VERSION 5.8 ;
BUSBITCHARS "[]" ;
DIVIDERCHAR "/" ;
UNITS
    DATABASE MICRONS 1000 ;
END UNITS

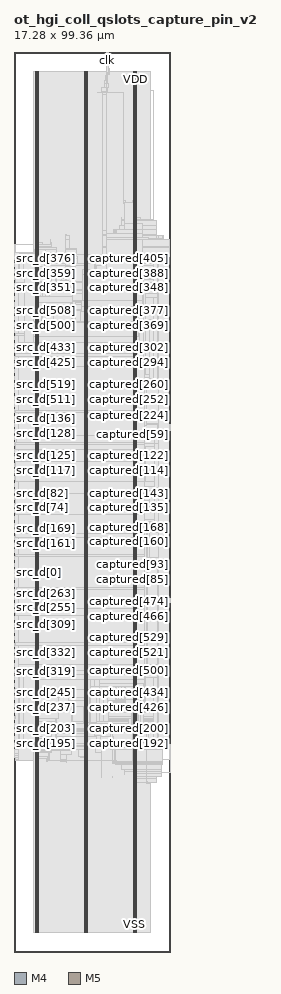
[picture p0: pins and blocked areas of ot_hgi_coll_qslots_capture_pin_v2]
MACRO ot_hgi_coll_qslots_capture_pin_v2
  FOREIGN ot_hgi_coll_qslots_capture_pin_v2 0 0 ;
  CLASS BLOCK ;
  SIZE 17.28 BY 99.36 ;
  PIN capture_slot[0]
    DIRECTION INPUT ;
    USE SIGNAL ;
    PORT
      LAYER M4 ;
        RECT  0 41.808 0.084 41.832 ;
    END
  END capture_slot[0]
  PIN captured[0]
    DIRECTION OUTPUT ;
    USE SIGNAL ;
    PORT
      LAYER M4 ;
        RECT  17.196 42.192 17.28 42.216 ;
    END
  END captured[0]
  PIN captured[100]
    DIRECTION OUTPUT ;
    USE SIGNAL ;
    PORT
      LAYER M4 ;
        RECT  17.196 51.792 17.28 51.816 ;
    END
  END captured[100]
  PIN captured[101]
    DIRECTION OUTPUT ;
    USE SIGNAL ;
    PORT
      LAYER M4 ;
        RECT  17.196 51.888 17.28 51.912 ;
    END
  END captured[101]
  PIN captured[102]
    DIRECTION OUTPUT ;
    USE SIGNAL ;
    PORT
      LAYER M4 ;
        RECT  17.196 51.984 17.28 52.008 ;
    END
  END captured[102]
  PIN captured[103]
    DIRECTION OUTPUT ;
    USE SIGNAL ;
    PORT
      LAYER M4 ;
        RECT  17.196 52.08 17.28 52.104 ;
    END
  END captured[103]
  PIN captured[104]
    DIRECTION OUTPUT ;
    USE SIGNAL ;
    PORT
      LAYER M4 ;
        RECT  17.196 52.176 17.28 52.2 ;
    END
  END captured[104]
  PIN captured[105]
    DIRECTION OUTPUT ;
    USE SIGNAL ;
    PORT
      LAYER M4 ;
        RECT  17.196 52.272 17.28 52.296 ;
    END
  END captured[105]
  PIN captured[106]
    DIRECTION OUTPUT ;
    USE SIGNAL ;
    PORT
      LAYER M4 ;
        RECT  17.196 52.368 17.28 52.392 ;
    END
  END captured[106]
  PIN captured[107]
    DIRECTION OUTPUT ;
    USE SIGNAL ;
    PORT
      LAYER M4 ;
        RECT  17.196 52.464 17.28 52.488 ;
    END
  END captured[107]
  PIN captured[108]
    DIRECTION OUTPUT ;
    USE SIGNAL ;
    PORT
      LAYER M4 ;
        RECT  17.196 52.56 17.28 52.584 ;
    END
  END captured[108]
  PIN captured[109]
    DIRECTION OUTPUT ;
    USE SIGNAL ;
    PORT
      LAYER M4 ;
        RECT  17.196 52.656 17.28 52.68 ;
    END
  END captured[109]
  PIN captured[10]
    DIRECTION OUTPUT ;
    USE SIGNAL ;
    PORT
      LAYER M4 ;
        RECT  17.196 43.152 17.28 43.176 ;
    END
  END captured[10]
  PIN captured[110]
    DIRECTION OUTPUT ;
    USE SIGNAL ;
    PORT
      LAYER M4 ;
        RECT  17.196 52.752 17.28 52.776 ;
    END
  END captured[110]
  PIN captured[111]
    DIRECTION OUTPUT ;
    USE SIGNAL ;
    PORT
      LAYER M4 ;
        RECT  17.196 52.848 17.28 52.872 ;
    END
  END captured[111]
  PIN captured[112]
    DIRECTION OUTPUT ;
    USE SIGNAL ;
    PORT
      LAYER M4 ;
        RECT  17.196 52.944 17.28 52.968 ;
    END
  END captured[112]
  PIN captured[113]
    DIRECTION OUTPUT ;
    USE SIGNAL ;
    PORT
      LAYER M4 ;
        RECT  17.196 53.04 17.28 53.064 ;
    END
  END captured[113]
  PIN captured[114]
    DIRECTION OUTPUT ;
    USE SIGNAL ;
    PORT
      LAYER M4 ;
        RECT  17.196 53.136 17.28 53.16 ;
    END
  END captured[114]
  PIN captured[115]
    DIRECTION OUTPUT ;
    USE SIGNAL ;
    PORT
      LAYER M4 ;
        RECT  17.196 53.232 17.28 53.256 ;
    END
  END captured[115]
  PIN captured[116]
    DIRECTION OUTPUT ;
    USE SIGNAL ;
    PORT
      LAYER M4 ;
        RECT  17.196 53.328 17.28 53.352 ;
    END
  END captured[116]
  PIN captured[117]
    DIRECTION OUTPUT ;
    USE SIGNAL ;
    PORT
      LAYER M4 ;
        RECT  17.196 53.424 17.28 53.448 ;
    END
  END captured[117]
  PIN captured[118]
    DIRECTION OUTPUT ;
    USE SIGNAL ;
    PORT
      LAYER M4 ;
        RECT  17.196 53.52 17.28 53.544 ;
    END
  END captured[118]
  PIN captured[119]
    DIRECTION OUTPUT ;
    USE SIGNAL ;
    PORT
      LAYER M4 ;
        RECT  17.196 53.616 17.28 53.64 ;
    END
  END captured[119]
  PIN captured[11]
    DIRECTION OUTPUT ;
    USE SIGNAL ;
    PORT
      LAYER M4 ;
        RECT  17.196 43.248 17.28 43.272 ;
    END
  END captured[11]
  PIN captured[120]
    DIRECTION OUTPUT ;
    USE SIGNAL ;
    PORT
      LAYER M4 ;
        RECT  17.196 53.712 17.28 53.736 ;
    END
  END captured[120]
  PIN captured[121]
    DIRECTION OUTPUT ;
    USE SIGNAL ;
    PORT
      LAYER M4 ;
        RECT  17.196 53.808 17.28 53.832 ;
    END
  END captured[121]
  PIN captured[122]
    DIRECTION OUTPUT ;
    USE SIGNAL ;
    PORT
      LAYER M4 ;
        RECT  17.196 53.904 17.28 53.928 ;
    END
  END captured[122]
  PIN captured[123]
    DIRECTION OUTPUT ;
    USE SIGNAL ;
    PORT
      LAYER M4 ;
        RECT  17.196 54 17.28 54.024 ;
    END
  END captured[123]
  PIN captured[124]
    DIRECTION OUTPUT ;
    USE SIGNAL ;
    PORT
      LAYER M4 ;
        RECT  17.196 54.096 17.28 54.12 ;
    END
  END captured[124]
  PIN captured[125]
    DIRECTION OUTPUT ;
    USE SIGNAL ;
    PORT
      LAYER M4 ;
        RECT  17.196 54.192 17.28 54.216 ;
    END
  END captured[125]
  PIN captured[126]
    DIRECTION OUTPUT ;
    USE SIGNAL ;
    PORT
      LAYER M4 ;
        RECT  17.196 54.288 17.28 54.312 ;
    END
  END captured[126]
  PIN captured[127]
    DIRECTION OUTPUT ;
    USE SIGNAL ;
    PORT
      LAYER M4 ;
        RECT  17.196 54.384 17.28 54.408 ;
    END
  END captured[127]
  PIN captured[128]
    DIRECTION OUTPUT ;
    USE SIGNAL ;
    PORT
      LAYER M4 ;
        RECT  17.196 48.336 17.28 48.36 ;
    END
  END captured[128]
  PIN captured[129]
    DIRECTION OUTPUT ;
    USE SIGNAL ;
    PORT
      LAYER M4 ;
        RECT  17.196 48.432 17.28 48.456 ;
    END
  END captured[129]
  PIN captured[12]
    DIRECTION OUTPUT ;
    USE SIGNAL ;
    PORT
      LAYER M4 ;
        RECT  17.196 43.344 17.28 43.368 ;
    END
  END captured[12]
  PIN captured[130]
    DIRECTION OUTPUT ;
    USE SIGNAL ;
    PORT
      LAYER M4 ;
        RECT  17.196 48.528 17.28 48.552 ;
    END
  END captured[130]
  PIN captured[131]
    DIRECTION OUTPUT ;
    USE SIGNAL ;
    PORT
      LAYER M4 ;
        RECT  17.196 48.624 17.28 48.648 ;
    END
  END captured[131]
  PIN captured[132]
    DIRECTION OUTPUT ;
    USE SIGNAL ;
    PORT
      LAYER M4 ;
        RECT  17.196 48.72 17.28 48.744 ;
    END
  END captured[132]
  PIN captured[133]
    DIRECTION OUTPUT ;
    USE SIGNAL ;
    PORT
      LAYER M4 ;
        RECT  17.196 48.816 17.28 48.84 ;
    END
  END captured[133]
  PIN captured[134]
    DIRECTION OUTPUT ;
    USE SIGNAL ;
    PORT
      LAYER M4 ;
        RECT  17.196 48.912 17.28 48.936 ;
    END
  END captured[134]
  PIN captured[135]
    DIRECTION OUTPUT ;
    USE SIGNAL ;
    PORT
      LAYER M4 ;
        RECT  17.196 49.008 17.28 49.032 ;
    END
  END captured[135]
  PIN captured[136]
    DIRECTION OUTPUT ;
    USE SIGNAL ;
    PORT
      LAYER M4 ;
        RECT  17.196 49.104 17.28 49.128 ;
    END
  END captured[136]
  PIN captured[137]
    DIRECTION OUTPUT ;
    USE SIGNAL ;
    PORT
      LAYER M4 ;
        RECT  17.196 49.2 17.28 49.224 ;
    END
  END captured[137]
  PIN captured[138]
    DIRECTION OUTPUT ;
    USE SIGNAL ;
    PORT
      LAYER M4 ;
        RECT  17.196 49.296 17.28 49.32 ;
    END
  END captured[138]
  PIN captured[139]
    DIRECTION OUTPUT ;
    USE SIGNAL ;
    PORT
      LAYER M4 ;
        RECT  17.196 49.392 17.28 49.416 ;
    END
  END captured[139]
  PIN captured[13]
    DIRECTION OUTPUT ;
    USE SIGNAL ;
    PORT
      LAYER M4 ;
        RECT  17.196 43.44 17.28 43.464 ;
    END
  END captured[13]
  PIN captured[140]
    DIRECTION OUTPUT ;
    USE SIGNAL ;
    PORT
      LAYER M4 ;
        RECT  17.196 49.488 17.28 49.512 ;
    END
  END captured[140]
  PIN captured[141]
    DIRECTION OUTPUT ;
    USE SIGNAL ;
    PORT
      LAYER M4 ;
        RECT  17.196 49.584 17.28 49.608 ;
    END
  END captured[141]
  PIN captured[142]
    DIRECTION OUTPUT ;
    USE SIGNAL ;
    PORT
      LAYER M4 ;
        RECT  17.196 49.68 17.28 49.704 ;
    END
  END captured[142]
  PIN captured[143]
    DIRECTION OUTPUT ;
    USE SIGNAL ;
    PORT
      LAYER M4 ;
        RECT  17.196 49.776 17.28 49.8 ;
    END
  END captured[143]
  PIN captured[144]
    DIRECTION OUTPUT ;
    USE SIGNAL ;
    PORT
      LAYER M4 ;
        RECT  17.196 49.872 17.28 49.896 ;
    END
  END captured[144]
  PIN captured[145]
    DIRECTION OUTPUT ;
    USE SIGNAL ;
    PORT
      LAYER M4 ;
        RECT  17.196 49.968 17.28 49.992 ;
    END
  END captured[145]
  PIN captured[146]
    DIRECTION OUTPUT ;
    USE SIGNAL ;
    PORT
      LAYER M4 ;
        RECT  17.196 50.064 17.28 50.088 ;
    END
  END captured[146]
  PIN captured[147]
    DIRECTION OUTPUT ;
    USE SIGNAL ;
    PORT
      LAYER M4 ;
        RECT  17.196 50.16 17.28 50.184 ;
    END
  END captured[147]
  PIN captured[148]
    DIRECTION OUTPUT ;
    USE SIGNAL ;
    PORT
      LAYER M4 ;
        RECT  17.196 50.256 17.28 50.28 ;
    END
  END captured[148]
  PIN captured[149]
    DIRECTION OUTPUT ;
    USE SIGNAL ;
    PORT
      LAYER M4 ;
        RECT  17.196 50.352 17.28 50.376 ;
    END
  END captured[149]
  PIN captured[14]
    DIRECTION OUTPUT ;
    USE SIGNAL ;
    PORT
      LAYER M4 ;
        RECT  17.196 43.536 17.28 43.56 ;
    END
  END captured[14]
  PIN captured[150]
    DIRECTION OUTPUT ;
    USE SIGNAL ;
    PORT
      LAYER M4 ;
        RECT  17.196 50.448 17.28 50.472 ;
    END
  END captured[150]
  PIN captured[151]
    DIRECTION OUTPUT ;
    USE SIGNAL ;
    PORT
      LAYER M4 ;
        RECT  17.196 50.544 17.28 50.568 ;
    END
  END captured[151]
  PIN captured[152]
    DIRECTION OUTPUT ;
    USE SIGNAL ;
    PORT
      LAYER M4 ;
        RECT  17.196 50.64 17.28 50.664 ;
    END
  END captured[152]
  PIN captured[153]
    DIRECTION OUTPUT ;
    USE SIGNAL ;
    PORT
      LAYER M4 ;
        RECT  17.196 50.736 17.28 50.76 ;
    END
  END captured[153]
  PIN captured[154]
    DIRECTION OUTPUT ;
    USE SIGNAL ;
    PORT
      LAYER M4 ;
        RECT  17.196 50.832 17.28 50.856 ;
    END
  END captured[154]
  PIN captured[155]
    DIRECTION OUTPUT ;
    USE SIGNAL ;
    PORT
      LAYER M4 ;
        RECT  17.196 50.928 17.28 50.952 ;
    END
  END captured[155]
  PIN captured[156]
    DIRECTION OUTPUT ;
    USE SIGNAL ;
    PORT
      LAYER M4 ;
        RECT  17.196 51.024 17.28 51.048 ;
    END
  END captured[156]
  PIN captured[157]
    DIRECTION OUTPUT ;
    USE SIGNAL ;
    PORT
      LAYER M4 ;
        RECT  17.196 51.12 17.28 51.144 ;
    END
  END captured[157]
  PIN captured[158]
    DIRECTION OUTPUT ;
    USE SIGNAL ;
    PORT
      LAYER M4 ;
        RECT  17.196 51.216 17.28 51.24 ;
    END
  END captured[158]
  PIN captured[159]
    DIRECTION OUTPUT ;
    USE SIGNAL ;
    PORT
      LAYER M4 ;
        RECT  17.196 51.312 17.28 51.336 ;
    END
  END captured[159]
  PIN captured[15]
    DIRECTION OUTPUT ;
    USE SIGNAL ;
    PORT
      LAYER M4 ;
        RECT  17.196 43.632 17.28 43.656 ;
    END
  END captured[15]
  PIN captured[160]
    DIRECTION OUTPUT ;
    USE SIGNAL ;
    PORT
      LAYER M4 ;
        RECT  17.196 45.264 17.28 45.288 ;
    END
  END captured[160]
  PIN captured[161]
    DIRECTION OUTPUT ;
    USE SIGNAL ;
    PORT
      LAYER M4 ;
        RECT  17.196 45.36 17.28 45.384 ;
    END
  END captured[161]
  PIN captured[162]
    DIRECTION OUTPUT ;
    USE SIGNAL ;
    PORT
      LAYER M4 ;
        RECT  17.196 45.456 17.28 45.48 ;
    END
  END captured[162]
  PIN captured[163]
    DIRECTION OUTPUT ;
    USE SIGNAL ;
    PORT
      LAYER M4 ;
        RECT  17.196 45.552 17.28 45.576 ;
    END
  END captured[163]
  PIN captured[164]
    DIRECTION OUTPUT ;
    USE SIGNAL ;
    PORT
      LAYER M4 ;
        RECT  17.196 45.648 17.28 45.672 ;
    END
  END captured[164]
  PIN captured[165]
    DIRECTION OUTPUT ;
    USE SIGNAL ;
    PORT
      LAYER M4 ;
        RECT  17.196 45.744 17.28 45.768 ;
    END
  END captured[165]
  PIN captured[166]
    DIRECTION OUTPUT ;
    USE SIGNAL ;
    PORT
      LAYER M4 ;
        RECT  17.196 45.84 17.28 45.864 ;
    END
  END captured[166]
  PIN captured[167]
    DIRECTION OUTPUT ;
    USE SIGNAL ;
    PORT
      LAYER M4 ;
        RECT  17.196 45.936 17.28 45.96 ;
    END
  END captured[167]
  PIN captured[168]
    DIRECTION OUTPUT ;
    USE SIGNAL ;
    PORT
      LAYER M4 ;
        RECT  17.196 46.032 17.28 46.056 ;
    END
  END captured[168]
  PIN captured[169]
    DIRECTION OUTPUT ;
    USE SIGNAL ;
    PORT
      LAYER M4 ;
        RECT  17.196 46.128 17.28 46.152 ;
    END
  END captured[169]
  PIN captured[16]
    DIRECTION OUTPUT ;
    USE SIGNAL ;
    PORT
      LAYER M4 ;
        RECT  17.196 43.728 17.28 43.752 ;
    END
  END captured[16]
  PIN captured[170]
    DIRECTION OUTPUT ;
    USE SIGNAL ;
    PORT
      LAYER M4 ;
        RECT  17.196 46.224 17.28 46.248 ;
    END
  END captured[170]
  PIN captured[171]
    DIRECTION OUTPUT ;
    USE SIGNAL ;
    PORT
      LAYER M4 ;
        RECT  17.196 46.32 17.28 46.344 ;
    END
  END captured[171]
  PIN captured[172]
    DIRECTION OUTPUT ;
    USE SIGNAL ;
    PORT
      LAYER M4 ;
        RECT  17.196 46.416 17.28 46.44 ;
    END
  END captured[172]
  PIN captured[173]
    DIRECTION OUTPUT ;
    USE SIGNAL ;
    PORT
      LAYER M4 ;
        RECT  17.196 46.512 17.28 46.536 ;
    END
  END captured[173]
  PIN captured[174]
    DIRECTION OUTPUT ;
    USE SIGNAL ;
    PORT
      LAYER M4 ;
        RECT  17.196 46.608 17.28 46.632 ;
    END
  END captured[174]
  PIN captured[175]
    DIRECTION OUTPUT ;
    USE SIGNAL ;
    PORT
      LAYER M4 ;
        RECT  17.196 46.704 17.28 46.728 ;
    END
  END captured[175]
  PIN captured[176]
    DIRECTION OUTPUT ;
    USE SIGNAL ;
    PORT
      LAYER M4 ;
        RECT  17.196 46.8 17.28 46.824 ;
    END
  END captured[176]
  PIN captured[177]
    DIRECTION OUTPUT ;
    USE SIGNAL ;
    PORT
      LAYER M4 ;
        RECT  17.196 46.896 17.28 46.92 ;
    END
  END captured[177]
  PIN captured[178]
    DIRECTION OUTPUT ;
    USE SIGNAL ;
    PORT
      LAYER M4 ;
        RECT  17.196 46.992 17.28 47.016 ;
    END
  END captured[178]
  PIN captured[179]
    DIRECTION OUTPUT ;
    USE SIGNAL ;
    PORT
      LAYER M4 ;
        RECT  17.196 47.088 17.28 47.112 ;
    END
  END captured[179]
  PIN captured[17]
    DIRECTION OUTPUT ;
    USE SIGNAL ;
    PORT
      LAYER M4 ;
        RECT  17.196 43.824 17.28 43.848 ;
    END
  END captured[17]
  PIN captured[180]
    DIRECTION OUTPUT ;
    USE SIGNAL ;
    PORT
      LAYER M4 ;
        RECT  17.196 47.184 17.28 47.208 ;
    END
  END captured[180]
  PIN captured[181]
    DIRECTION OUTPUT ;
    USE SIGNAL ;
    PORT
      LAYER M4 ;
        RECT  17.196 47.28 17.28 47.304 ;
    END
  END captured[181]
  PIN captured[182]
    DIRECTION OUTPUT ;
    USE SIGNAL ;
    PORT
      LAYER M4 ;
        RECT  17.196 47.376 17.28 47.4 ;
    END
  END captured[182]
  PIN captured[183]
    DIRECTION OUTPUT ;
    USE SIGNAL ;
    PORT
      LAYER M4 ;
        RECT  17.196 47.472 17.28 47.496 ;
    END
  END captured[183]
  PIN captured[184]
    DIRECTION OUTPUT ;
    USE SIGNAL ;
    PORT
      LAYER M4 ;
        RECT  17.196 47.568 17.28 47.592 ;
    END
  END captured[184]
  PIN captured[185]
    DIRECTION OUTPUT ;
    USE SIGNAL ;
    PORT
      LAYER M4 ;
        RECT  17.196 47.664 17.28 47.688 ;
    END
  END captured[185]
  PIN captured[186]
    DIRECTION OUTPUT ;
    USE SIGNAL ;
    PORT
      LAYER M4 ;
        RECT  17.196 47.76 17.28 47.784 ;
    END
  END captured[186]
  PIN captured[187]
    DIRECTION OUTPUT ;
    USE SIGNAL ;
    PORT
      LAYER M4 ;
        RECT  17.196 47.856 17.28 47.88 ;
    END
  END captured[187]
  PIN captured[188]
    DIRECTION OUTPUT ;
    USE SIGNAL ;
    PORT
      LAYER M4 ;
        RECT  17.196 47.952 17.28 47.976 ;
    END
  END captured[188]
  PIN captured[189]
    DIRECTION OUTPUT ;
    USE SIGNAL ;
    PORT
      LAYER M4 ;
        RECT  17.196 48.048 17.28 48.072 ;
    END
  END captured[189]
  PIN captured[18]
    DIRECTION OUTPUT ;
    USE SIGNAL ;
    PORT
      LAYER M4 ;
        RECT  17.196 43.92 17.28 43.944 ;
    END
  END captured[18]
  PIN captured[190]
    DIRECTION OUTPUT ;
    USE SIGNAL ;
    PORT
      LAYER M4 ;
        RECT  17.196 48.144 17.28 48.168 ;
    END
  END captured[190]
  PIN captured[191]
    DIRECTION OUTPUT ;
    USE SIGNAL ;
    PORT
      LAYER M4 ;
        RECT  17.196 48.24 17.28 48.264 ;
    END
  END captured[191]
  PIN captured[192]
    DIRECTION OUTPUT ;
    USE SIGNAL ;
    PORT
      LAYER M4 ;
        RECT  17.196 22.992 17.28 23.016 ;
    END
  END captured[192]
  PIN captured[193]
    DIRECTION OUTPUT ;
    USE SIGNAL ;
    PORT
      LAYER M4 ;
        RECT  17.196 23.088 17.28 23.112 ;
    END
  END captured[193]
  PIN captured[194]
    DIRECTION OUTPUT ;
    USE SIGNAL ;
    PORT
      LAYER M4 ;
        RECT  17.196 23.184 17.28 23.208 ;
    END
  END captured[194]
  PIN captured[195]
    DIRECTION OUTPUT ;
    USE SIGNAL ;
    PORT
      LAYER M4 ;
        RECT  17.196 23.28 17.28 23.304 ;
    END
  END captured[195]
  PIN captured[196]
    DIRECTION OUTPUT ;
    USE SIGNAL ;
    PORT
      LAYER M4 ;
        RECT  17.196 23.376 17.28 23.4 ;
    END
  END captured[196]
  PIN captured[197]
    DIRECTION OUTPUT ;
    USE SIGNAL ;
    PORT
      LAYER M4 ;
        RECT  17.196 23.472 17.28 23.496 ;
    END
  END captured[197]
  PIN captured[198]
    DIRECTION OUTPUT ;
    USE SIGNAL ;
    PORT
      LAYER M4 ;
        RECT  17.196 23.568 17.28 23.592 ;
    END
  END captured[198]
  PIN captured[199]
    DIRECTION OUTPUT ;
    USE SIGNAL ;
    PORT
      LAYER M4 ;
        RECT  17.196 23.664 17.28 23.688 ;
    END
  END captured[199]
  PIN captured[19]
    DIRECTION OUTPUT ;
    USE SIGNAL ;
    PORT
      LAYER M4 ;
        RECT  17.196 44.016 17.28 44.04 ;
    END
  END captured[19]
  PIN captured[1]
    DIRECTION OUTPUT ;
    USE SIGNAL ;
    PORT
      LAYER M4 ;
        RECT  17.196 42.288 17.28 42.312 ;
    END
  END captured[1]
  PIN captured[200]
    DIRECTION OUTPUT ;
    USE SIGNAL ;
    PORT
      LAYER M4 ;
        RECT  17.196 23.76 17.28 23.784 ;
    END
  END captured[200]
  PIN captured[201]
    DIRECTION OUTPUT ;
    USE SIGNAL ;
    PORT
      LAYER M4 ;
        RECT  17.196 23.856 17.28 23.88 ;
    END
  END captured[201]
  PIN captured[202]
    DIRECTION OUTPUT ;
    USE SIGNAL ;
    PORT
      LAYER M4 ;
        RECT  17.196 23.952 17.28 23.976 ;
    END
  END captured[202]
  PIN captured[203]
    DIRECTION OUTPUT ;
    USE SIGNAL ;
    PORT
      LAYER M4 ;
        RECT  17.196 24.048 17.28 24.072 ;
    END
  END captured[203]
  PIN captured[204]
    DIRECTION OUTPUT ;
    USE SIGNAL ;
    PORT
      LAYER M4 ;
        RECT  17.196 24.144 17.28 24.168 ;
    END
  END captured[204]
  PIN captured[205]
    DIRECTION OUTPUT ;
    USE SIGNAL ;
    PORT
      LAYER M4 ;
        RECT  17.196 24.24 17.28 24.264 ;
    END
  END captured[205]
  PIN captured[206]
    DIRECTION OUTPUT ;
    USE SIGNAL ;
    PORT
      LAYER M4 ;
        RECT  17.196 24.336 17.28 24.36 ;
    END
  END captured[206]
  PIN captured[207]
    DIRECTION OUTPUT ;
    USE SIGNAL ;
    PORT
      LAYER M4 ;
        RECT  17.196 24.432 17.28 24.456 ;
    END
  END captured[207]
  PIN captured[208]
    DIRECTION OUTPUT ;
    USE SIGNAL ;
    PORT
      LAYER M4 ;
        RECT  17.196 24.528 17.28 24.552 ;
    END
  END captured[208]
  PIN captured[209]
    DIRECTION OUTPUT ;
    USE SIGNAL ;
    PORT
      LAYER M4 ;
        RECT  17.196 24.624 17.28 24.648 ;
    END
  END captured[209]
  PIN captured[20]
    DIRECTION OUTPUT ;
    USE SIGNAL ;
    PORT
      LAYER M4 ;
        RECT  17.196 44.112 17.28 44.136 ;
    END
  END captured[20]
  PIN captured[210]
    DIRECTION OUTPUT ;
    USE SIGNAL ;
    PORT
      LAYER M4 ;
        RECT  17.196 24.72 17.28 24.744 ;
    END
  END captured[210]
  PIN captured[211]
    DIRECTION OUTPUT ;
    USE SIGNAL ;
    PORT
      LAYER M4 ;
        RECT  17.196 24.816 17.28 24.84 ;
    END
  END captured[211]
  PIN captured[212]
    DIRECTION OUTPUT ;
    USE SIGNAL ;
    PORT
      LAYER M4 ;
        RECT  17.196 24.912 17.28 24.936 ;
    END
  END captured[212]
  PIN captured[213]
    DIRECTION OUTPUT ;
    USE SIGNAL ;
    PORT
      LAYER M4 ;
        RECT  17.196 25.008 17.28 25.032 ;
    END
  END captured[213]
  PIN captured[214]
    DIRECTION OUTPUT ;
    USE SIGNAL ;
    PORT
      LAYER M4 ;
        RECT  17.196 25.104 17.28 25.128 ;
    END
  END captured[214]
  PIN captured[215]
    DIRECTION OUTPUT ;
    USE SIGNAL ;
    PORT
      LAYER M4 ;
        RECT  17.196 25.2 17.28 25.224 ;
    END
  END captured[215]
  PIN captured[216]
    DIRECTION OUTPUT ;
    USE SIGNAL ;
    PORT
      LAYER M4 ;
        RECT  17.196 25.296 17.28 25.32 ;
    END
  END captured[216]
  PIN captured[217]
    DIRECTION OUTPUT ;
    USE SIGNAL ;
    PORT
      LAYER M4 ;
        RECT  17.196 25.392 17.28 25.416 ;
    END
  END captured[217]
  PIN captured[218]
    DIRECTION OUTPUT ;
    USE SIGNAL ;
    PORT
      LAYER M4 ;
        RECT  17.196 25.488 17.28 25.512 ;
    END
  END captured[218]
  PIN captured[219]
    DIRECTION OUTPUT ;
    USE SIGNAL ;
    PORT
      LAYER M4 ;
        RECT  17.196 25.584 17.28 25.608 ;
    END
  END captured[219]
  PIN captured[21]
    DIRECTION OUTPUT ;
    USE SIGNAL ;
    PORT
      LAYER M4 ;
        RECT  17.196 44.208 17.28 44.232 ;
    END
  END captured[21]
  PIN captured[220]
    DIRECTION OUTPUT ;
    USE SIGNAL ;
    PORT
      LAYER M4 ;
        RECT  17.196 25.68 17.28 25.704 ;
    END
  END captured[220]
  PIN captured[221]
    DIRECTION OUTPUT ;
    USE SIGNAL ;
    PORT
      LAYER M4 ;
        RECT  17.196 25.776 17.28 25.8 ;
    END
  END captured[221]
  PIN captured[222]
    DIRECTION OUTPUT ;
    USE SIGNAL ;
    PORT
      LAYER M4 ;
        RECT  17.196 25.872 17.28 25.896 ;
    END
  END captured[222]
  PIN captured[223]
    DIRECTION OUTPUT ;
    USE SIGNAL ;
    PORT
      LAYER M4 ;
        RECT  17.196 25.968 17.28 25.992 ;
    END
  END captured[223]
  PIN captured[224]
    DIRECTION OUTPUT ;
    USE SIGNAL ;
    PORT
      LAYER M4 ;
        RECT  17.196 58.32 17.28 58.344 ;
    END
  END captured[224]
  PIN captured[225]
    DIRECTION OUTPUT ;
    USE SIGNAL ;
    PORT
      LAYER M4 ;
        RECT  17.196 58.416 17.28 58.44 ;
    END
  END captured[225]
  PIN captured[226]
    DIRECTION OUTPUT ;
    USE SIGNAL ;
    PORT
      LAYER M4 ;
        RECT  17.196 58.512 17.28 58.536 ;
    END
  END captured[226]
  PIN captured[227]
    DIRECTION OUTPUT ;
    USE SIGNAL ;
    PORT
      LAYER M4 ;
        RECT  17.196 58.608 17.28 58.632 ;
    END
  END captured[227]
  PIN captured[228]
    DIRECTION OUTPUT ;
    USE SIGNAL ;
    PORT
      LAYER M4 ;
        RECT  17.196 58.704 17.28 58.728 ;
    END
  END captured[228]
  PIN captured[229]
    DIRECTION OUTPUT ;
    USE SIGNAL ;
    PORT
      LAYER M4 ;
        RECT  17.196 58.8 17.28 58.824 ;
    END
  END captured[229]
  PIN captured[22]
    DIRECTION OUTPUT ;
    USE SIGNAL ;
    PORT
      LAYER M4 ;
        RECT  17.196 44.304 17.28 44.328 ;
    END
  END captured[22]
  PIN captured[230]
    DIRECTION OUTPUT ;
    USE SIGNAL ;
    PORT
      LAYER M4 ;
        RECT  17.196 58.896 17.28 58.92 ;
    END
  END captured[230]
  PIN captured[231]
    DIRECTION OUTPUT ;
    USE SIGNAL ;
    PORT
      LAYER M4 ;
        RECT  17.196 58.992 17.28 59.016 ;
    END
  END captured[231]
  PIN captured[232]
    DIRECTION OUTPUT ;
    USE SIGNAL ;
    PORT
      LAYER M4 ;
        RECT  17.196 59.088 17.28 59.112 ;
    END
  END captured[232]
  PIN captured[233]
    DIRECTION OUTPUT ;
    USE SIGNAL ;
    PORT
      LAYER M4 ;
        RECT  17.196 59.184 17.28 59.208 ;
    END
  END captured[233]
  PIN captured[234]
    DIRECTION OUTPUT ;
    USE SIGNAL ;
    PORT
      LAYER M4 ;
        RECT  17.196 59.28 17.28 59.304 ;
    END
  END captured[234]
  PIN captured[235]
    DIRECTION OUTPUT ;
    USE SIGNAL ;
    PORT
      LAYER M4 ;
        RECT  17.196 59.376 17.28 59.4 ;
    END
  END captured[235]
  PIN captured[236]
    DIRECTION OUTPUT ;
    USE SIGNAL ;
    PORT
      LAYER M4 ;
        RECT  17.196 59.472 17.28 59.496 ;
    END
  END captured[236]
  PIN captured[237]
    DIRECTION OUTPUT ;
    USE SIGNAL ;
    PORT
      LAYER M4 ;
        RECT  17.196 59.568 17.28 59.592 ;
    END
  END captured[237]
  PIN captured[238]
    DIRECTION OUTPUT ;
    USE SIGNAL ;
    PORT
      LAYER M4 ;
        RECT  17.196 59.664 17.28 59.688 ;
    END
  END captured[238]
  PIN captured[239]
    DIRECTION OUTPUT ;
    USE SIGNAL ;
    PORT
      LAYER M4 ;
        RECT  17.196 59.76 17.28 59.784 ;
    END
  END captured[239]
  PIN captured[23]
    DIRECTION OUTPUT ;
    USE SIGNAL ;
    PORT
      LAYER M4 ;
        RECT  17.196 44.4 17.28 44.424 ;
    END
  END captured[23]
  PIN captured[240]
    DIRECTION OUTPUT ;
    USE SIGNAL ;
    PORT
      LAYER M4 ;
        RECT  17.196 59.856 17.28 59.88 ;
    END
  END captured[240]
  PIN captured[241]
    DIRECTION OUTPUT ;
    USE SIGNAL ;
    PORT
      LAYER M4 ;
        RECT  17.196 59.952 17.28 59.976 ;
    END
  END captured[241]
  PIN captured[242]
    DIRECTION OUTPUT ;
    USE SIGNAL ;
    PORT
      LAYER M4 ;
        RECT  17.196 60.048 17.28 60.072 ;
    END
  END captured[242]
  PIN captured[243]
    DIRECTION OUTPUT ;
    USE SIGNAL ;
    PORT
      LAYER M4 ;
        RECT  17.196 60.144 17.28 60.168 ;
    END
  END captured[243]
  PIN captured[244]
    DIRECTION OUTPUT ;
    USE SIGNAL ;
    PORT
      LAYER M4 ;
        RECT  17.196 60.24 17.28 60.264 ;
    END
  END captured[244]
  PIN captured[245]
    DIRECTION OUTPUT ;
    USE SIGNAL ;
    PORT
      LAYER M4 ;
        RECT  17.196 60.336 17.28 60.36 ;
    END
  END captured[245]
  PIN captured[246]
    DIRECTION OUTPUT ;
    USE SIGNAL ;
    PORT
      LAYER M4 ;
        RECT  17.196 60.432 17.28 60.456 ;
    END
  END captured[246]
  PIN captured[247]
    DIRECTION OUTPUT ;
    USE SIGNAL ;
    PORT
      LAYER M4 ;
        RECT  17.196 60.528 17.28 60.552 ;
    END
  END captured[247]
  PIN captured[248]
    DIRECTION OUTPUT ;
    USE SIGNAL ;
    PORT
      LAYER M4 ;
        RECT  17.196 60.624 17.28 60.648 ;
    END
  END captured[248]
  PIN captured[249]
    DIRECTION OUTPUT ;
    USE SIGNAL ;
    PORT
      LAYER M4 ;
        RECT  17.196 60.72 17.28 60.744 ;
    END
  END captured[249]
  PIN captured[24]
    DIRECTION OUTPUT ;
    USE SIGNAL ;
    PORT
      LAYER M4 ;
        RECT  17.196 44.496 17.28 44.52 ;
    END
  END captured[24]
  PIN captured[250]
    DIRECTION OUTPUT ;
    USE SIGNAL ;
    PORT
      LAYER M4 ;
        RECT  17.196 60.816 17.28 60.84 ;
    END
  END captured[250]
  PIN captured[251]
    DIRECTION OUTPUT ;
    USE SIGNAL ;
    PORT
      LAYER M4 ;
        RECT  17.196 60.912 17.28 60.936 ;
    END
  END captured[251]
  PIN captured[252]
    DIRECTION OUTPUT ;
    USE SIGNAL ;
    PORT
      LAYER M4 ;
        RECT  17.196 61.008 17.28 61.032 ;
    END
  END captured[252]
  PIN captured[253]
    DIRECTION OUTPUT ;
    USE SIGNAL ;
    PORT
      LAYER M4 ;
        RECT  17.196 61.104 17.28 61.128 ;
    END
  END captured[253]
  PIN captured[254]
    DIRECTION OUTPUT ;
    USE SIGNAL ;
    PORT
      LAYER M4 ;
        RECT  17.196 61.2 17.28 61.224 ;
    END
  END captured[254]
  PIN captured[255]
    DIRECTION OUTPUT ;
    USE SIGNAL ;
    PORT
      LAYER M4 ;
        RECT  17.196 61.296 17.28 61.32 ;
    END
  END captured[255]
  PIN captured[256]
    DIRECTION OUTPUT ;
    USE SIGNAL ;
    PORT
      LAYER M4 ;
        RECT  17.196 61.392 17.28 61.416 ;
    END
  END captured[256]
  PIN captured[257]
    DIRECTION OUTPUT ;
    USE SIGNAL ;
    PORT
      LAYER M4 ;
        RECT  17.196 61.488 17.28 61.512 ;
    END
  END captured[257]
  PIN captured[258]
    DIRECTION OUTPUT ;
    USE SIGNAL ;
    PORT
      LAYER M4 ;
        RECT  17.196 61.584 17.28 61.608 ;
    END
  END captured[258]
  PIN captured[259]
    DIRECTION OUTPUT ;
    USE SIGNAL ;
    PORT
      LAYER M4 ;
        RECT  17.196 61.68 17.28 61.704 ;
    END
  END captured[259]
  PIN captured[25]
    DIRECTION OUTPUT ;
    USE SIGNAL ;
    PORT
      LAYER M4 ;
        RECT  17.196 44.592 17.28 44.616 ;
    END
  END captured[25]
  PIN captured[260]
    DIRECTION OUTPUT ;
    USE SIGNAL ;
    PORT
      LAYER M4 ;
        RECT  17.196 61.776 17.28 61.8 ;
    END
  END captured[260]
  PIN captured[261]
    DIRECTION OUTPUT ;
    USE SIGNAL ;
    PORT
      LAYER M4 ;
        RECT  17.196 61.872 17.28 61.896 ;
    END
  END captured[261]
  PIN captured[262]
    DIRECTION OUTPUT ;
    USE SIGNAL ;
    PORT
      LAYER M4 ;
        RECT  17.196 61.968 17.28 61.992 ;
    END
  END captured[262]
  PIN captured[263]
    DIRECTION OUTPUT ;
    USE SIGNAL ;
    PORT
      LAYER M4 ;
        RECT  17.196 62.064 17.28 62.088 ;
    END
  END captured[263]
  PIN captured[264]
    DIRECTION OUTPUT ;
    USE SIGNAL ;
    PORT
      LAYER M4 ;
        RECT  17.196 62.16 17.28 62.184 ;
    END
  END captured[264]
  PIN captured[265]
    DIRECTION OUTPUT ;
    USE SIGNAL ;
    PORT
      LAYER M4 ;
        RECT  17.196 62.256 17.28 62.28 ;
    END
  END captured[265]
  PIN captured[266]
    DIRECTION OUTPUT ;
    USE SIGNAL ;
    PORT
      LAYER M4 ;
        RECT  17.196 62.352 17.28 62.376 ;
    END
  END captured[266]
  PIN captured[267]
    DIRECTION OUTPUT ;
    USE SIGNAL ;
    PORT
      LAYER M4 ;
        RECT  17.196 62.448 17.28 62.472 ;
    END
  END captured[267]
  PIN captured[268]
    DIRECTION OUTPUT ;
    USE SIGNAL ;
    PORT
      LAYER M4 ;
        RECT  17.196 62.544 17.28 62.568 ;
    END
  END captured[268]
  PIN captured[269]
    DIRECTION OUTPUT ;
    USE SIGNAL ;
    PORT
      LAYER M4 ;
        RECT  17.196 62.64 17.28 62.664 ;
    END
  END captured[269]
  PIN captured[26]
    DIRECTION OUTPUT ;
    USE SIGNAL ;
    PORT
      LAYER M4 ;
        RECT  17.196 44.688 17.28 44.712 ;
    END
  END captured[26]
  PIN captured[270]
    DIRECTION OUTPUT ;
    USE SIGNAL ;
    PORT
      LAYER M4 ;
        RECT  17.196 62.736 17.28 62.76 ;
    END
  END captured[270]
  PIN captured[271]
    DIRECTION OUTPUT ;
    USE SIGNAL ;
    PORT
      LAYER M4 ;
        RECT  17.196 62.832 17.28 62.856 ;
    END
  END captured[271]
  PIN captured[272]
    DIRECTION OUTPUT ;
    USE SIGNAL ;
    PORT
      LAYER M4 ;
        RECT  17.196 62.928 17.28 62.952 ;
    END
  END captured[272]
  PIN captured[273]
    DIRECTION OUTPUT ;
    USE SIGNAL ;
    PORT
      LAYER M4 ;
        RECT  17.196 63.024 17.28 63.048 ;
    END
  END captured[273]
  PIN captured[274]
    DIRECTION OUTPUT ;
    USE SIGNAL ;
    PORT
      LAYER M4 ;
        RECT  17.196 63.12 17.28 63.144 ;
    END
  END captured[274]
  PIN captured[275]
    DIRECTION OUTPUT ;
    USE SIGNAL ;
    PORT
      LAYER M4 ;
        RECT  17.196 63.216 17.28 63.24 ;
    END
  END captured[275]
  PIN captured[276]
    DIRECTION OUTPUT ;
    USE SIGNAL ;
    PORT
      LAYER M4 ;
        RECT  17.196 63.312 17.28 63.336 ;
    END
  END captured[276]
  PIN captured[277]
    DIRECTION OUTPUT ;
    USE SIGNAL ;
    PORT
      LAYER M4 ;
        RECT  17.196 63.408 17.28 63.432 ;
    END
  END captured[277]
  PIN captured[278]
    DIRECTION OUTPUT ;
    USE SIGNAL ;
    PORT
      LAYER M4 ;
        RECT  17.196 63.504 17.28 63.528 ;
    END
  END captured[278]
  PIN captured[279]
    DIRECTION OUTPUT ;
    USE SIGNAL ;
    PORT
      LAYER M4 ;
        RECT  17.196 63.6 17.28 63.624 ;
    END
  END captured[279]
  PIN captured[27]
    DIRECTION OUTPUT ;
    USE SIGNAL ;
    PORT
      LAYER M4 ;
        RECT  17.196 44.784 17.28 44.808 ;
    END
  END captured[27]
  PIN captured[280]
    DIRECTION OUTPUT ;
    USE SIGNAL ;
    PORT
      LAYER M4 ;
        RECT  17.196 63.696 17.28 63.72 ;
    END
  END captured[280]
  PIN captured[281]
    DIRECTION OUTPUT ;
    USE SIGNAL ;
    PORT
      LAYER M4 ;
        RECT  17.196 63.792 17.28 63.816 ;
    END
  END captured[281]
  PIN captured[282]
    DIRECTION OUTPUT ;
    USE SIGNAL ;
    PORT
      LAYER M4 ;
        RECT  17.196 63.888 17.28 63.912 ;
    END
  END captured[282]
  PIN captured[283]
    DIRECTION OUTPUT ;
    USE SIGNAL ;
    PORT
      LAYER M4 ;
        RECT  17.196 63.984 17.28 64.008 ;
    END
  END captured[283]
  PIN captured[284]
    DIRECTION OUTPUT ;
    USE SIGNAL ;
    PORT
      LAYER M4 ;
        RECT  17.196 64.08 17.28 64.104 ;
    END
  END captured[284]
  PIN captured[285]
    DIRECTION OUTPUT ;
    USE SIGNAL ;
    PORT
      LAYER M4 ;
        RECT  17.196 64.176 17.28 64.2 ;
    END
  END captured[285]
  PIN captured[286]
    DIRECTION OUTPUT ;
    USE SIGNAL ;
    PORT
      LAYER M4 ;
        RECT  17.196 64.272 17.28 64.296 ;
    END
  END captured[286]
  PIN captured[287]
    DIRECTION OUTPUT ;
    USE SIGNAL ;
    PORT
      LAYER M4 ;
        RECT  17.196 64.368 17.28 64.392 ;
    END
  END captured[287]
  PIN captured[288]
    DIRECTION OUTPUT ;
    USE SIGNAL ;
    PORT
      LAYER M4 ;
        RECT  17.196 64.464 17.28 64.488 ;
    END
  END captured[288]
  PIN captured[289]
    DIRECTION OUTPUT ;
    USE SIGNAL ;
    PORT
      LAYER M4 ;
        RECT  17.196 64.56 17.28 64.584 ;
    END
  END captured[289]
  PIN captured[28]
    DIRECTION OUTPUT ;
    USE SIGNAL ;
    PORT
      LAYER M4 ;
        RECT  17.196 44.88 17.28 44.904 ;
    END
  END captured[28]
  PIN captured[290]
    DIRECTION OUTPUT ;
    USE SIGNAL ;
    PORT
      LAYER M4 ;
        RECT  17.196 64.656 17.28 64.68 ;
    END
  END captured[290]
  PIN captured[291]
    DIRECTION OUTPUT ;
    USE SIGNAL ;
    PORT
      LAYER M4 ;
        RECT  17.196 64.752 17.28 64.776 ;
    END
  END captured[291]
  PIN captured[292]
    DIRECTION OUTPUT ;
    USE SIGNAL ;
    PORT
      LAYER M4 ;
        RECT  17.196 64.848 17.28 64.872 ;
    END
  END captured[292]
  PIN captured[293]
    DIRECTION OUTPUT ;
    USE SIGNAL ;
    PORT
      LAYER M4 ;
        RECT  17.196 64.944 17.28 64.968 ;
    END
  END captured[293]
  PIN captured[294]
    DIRECTION OUTPUT ;
    USE SIGNAL ;
    PORT
      LAYER M4 ;
        RECT  17.196 65.04 17.28 65.064 ;
    END
  END captured[294]
  PIN captured[295]
    DIRECTION OUTPUT ;
    USE SIGNAL ;
    PORT
      LAYER M4 ;
        RECT  17.196 65.136 17.28 65.16 ;
    END
  END captured[295]
  PIN captured[296]
    DIRECTION OUTPUT ;
    USE SIGNAL ;
    PORT
      LAYER M4 ;
        RECT  17.196 65.232 17.28 65.256 ;
    END
  END captured[296]
  PIN captured[297]
    DIRECTION OUTPUT ;
    USE SIGNAL ;
    PORT
      LAYER M4 ;
        RECT  17.196 65.328 17.28 65.352 ;
    END
  END captured[297]
  PIN captured[298]
    DIRECTION OUTPUT ;
    USE SIGNAL ;
    PORT
      LAYER M4 ;
        RECT  17.196 65.424 17.28 65.448 ;
    END
  END captured[298]
  PIN captured[299]
    DIRECTION OUTPUT ;
    USE SIGNAL ;
    PORT
      LAYER M4 ;
        RECT  17.196 65.52 17.28 65.544 ;
    END
  END captured[299]
  PIN captured[29]
    DIRECTION OUTPUT ;
    USE SIGNAL ;
    PORT
      LAYER M4 ;
        RECT  17.196 44.976 17.28 45 ;
    END
  END captured[29]
  PIN captured[2]
    DIRECTION OUTPUT ;
    USE SIGNAL ;
    PORT
      LAYER M4 ;
        RECT  17.196 42.384 17.28 42.408 ;
    END
  END captured[2]
  PIN captured[300]
    DIRECTION OUTPUT ;
    USE SIGNAL ;
    PORT
      LAYER M4 ;
        RECT  17.196 65.616 17.28 65.64 ;
    END
  END captured[300]
  PIN captured[301]
    DIRECTION OUTPUT ;
    USE SIGNAL ;
    PORT
      LAYER M4 ;
        RECT  17.196 65.712 17.28 65.736 ;
    END
  END captured[301]
  PIN captured[302]
    DIRECTION OUTPUT ;
    USE SIGNAL ;
    PORT
      LAYER M4 ;
        RECT  17.196 65.808 17.28 65.832 ;
    END
  END captured[302]
  PIN captured[303]
    DIRECTION OUTPUT ;
    USE SIGNAL ;
    PORT
      LAYER M4 ;
        RECT  17.196 65.904 17.28 65.928 ;
    END
  END captured[303]
  PIN captured[304]
    DIRECTION OUTPUT ;
    USE SIGNAL ;
    PORT
      LAYER M4 ;
        RECT  17.196 66 17.28 66.024 ;
    END
  END captured[304]
  PIN captured[305]
    DIRECTION OUTPUT ;
    USE SIGNAL ;
    PORT
      LAYER M4 ;
        RECT  17.196 66.096 17.28 66.12 ;
    END
  END captured[305]
  PIN captured[306]
    DIRECTION OUTPUT ;
    USE SIGNAL ;
    PORT
      LAYER M4 ;
        RECT  17.196 66.192 17.28 66.216 ;
    END
  END captured[306]
  PIN captured[307]
    DIRECTION OUTPUT ;
    USE SIGNAL ;
    PORT
      LAYER M4 ;
        RECT  17.196 66.288 17.28 66.312 ;
    END
  END captured[307]
  PIN captured[308]
    DIRECTION OUTPUT ;
    USE SIGNAL ;
    PORT
      LAYER M4 ;
        RECT  17.196 66.384 17.28 66.408 ;
    END
  END captured[308]
  PIN captured[309]
    DIRECTION OUTPUT ;
    USE SIGNAL ;
    PORT
      LAYER M4 ;
        RECT  17.196 66.48 17.28 66.504 ;
    END
  END captured[309]
  PIN captured[30]
    DIRECTION OUTPUT ;
    USE SIGNAL ;
    PORT
      LAYER M4 ;
        RECT  17.196 45.072 17.28 45.096 ;
    END
  END captured[30]
  PIN captured[310]
    DIRECTION OUTPUT ;
    USE SIGNAL ;
    PORT
      LAYER M4 ;
        RECT  17.196 66.576 17.28 66.6 ;
    END
  END captured[310]
  PIN captured[311]
    DIRECTION OUTPUT ;
    USE SIGNAL ;
    PORT
      LAYER M4 ;
        RECT  17.196 66.672 17.28 66.696 ;
    END
  END captured[311]
  PIN captured[312]
    DIRECTION OUTPUT ;
    USE SIGNAL ;
    PORT
      LAYER M4 ;
        RECT  17.196 66.768 17.28 66.792 ;
    END
  END captured[312]
  PIN captured[313]
    DIRECTION OUTPUT ;
    USE SIGNAL ;
    PORT
      LAYER M4 ;
        RECT  17.196 66.864 17.28 66.888 ;
    END
  END captured[313]
  PIN captured[314]
    DIRECTION OUTPUT ;
    USE SIGNAL ;
    PORT
      LAYER M4 ;
        RECT  17.196 66.96 17.28 66.984 ;
    END
  END captured[314]
  PIN captured[315]
    DIRECTION OUTPUT ;
    USE SIGNAL ;
    PORT
      LAYER M4 ;
        RECT  17.196 67.056 17.28 67.08 ;
    END
  END captured[315]
  PIN captured[316]
    DIRECTION OUTPUT ;
    USE SIGNAL ;
    PORT
      LAYER M4 ;
        RECT  17.196 67.152 17.28 67.176 ;
    END
  END captured[316]
  PIN captured[317]
    DIRECTION OUTPUT ;
    USE SIGNAL ;
    PORT
      LAYER M4 ;
        RECT  17.196 67.248 17.28 67.272 ;
    END
  END captured[317]
  PIN captured[318]
    DIRECTION OUTPUT ;
    USE SIGNAL ;
    PORT
      LAYER M4 ;
        RECT  17.196 67.344 17.28 67.368 ;
    END
  END captured[318]
  PIN captured[319]
    DIRECTION OUTPUT ;
    USE SIGNAL ;
    PORT
      LAYER M4 ;
        RECT  17.196 67.44 17.28 67.464 ;
    END
  END captured[319]
  PIN captured[31]
    DIRECTION OUTPUT ;
    USE SIGNAL ;
    PORT
      LAYER M4 ;
        RECT  17.196 45.168 17.28 45.192 ;
    END
  END captured[31]
  PIN captured[320]
    DIRECTION OUTPUT ;
    USE SIGNAL ;
    PORT
      LAYER M4 ;
        RECT  17.196 70.608 17.28 70.632 ;
    END
  END captured[320]
  PIN captured[321]
    DIRECTION OUTPUT ;
    USE SIGNAL ;
    PORT
      LAYER M4 ;
        RECT  17.196 70.704 17.28 70.728 ;
    END
  END captured[321]
  PIN captured[322]
    DIRECTION OUTPUT ;
    USE SIGNAL ;
    PORT
      LAYER M4 ;
        RECT  17.196 70.8 17.28 70.824 ;
    END
  END captured[322]
  PIN captured[323]
    DIRECTION OUTPUT ;
    USE SIGNAL ;
    PORT
      LAYER M4 ;
        RECT  17.196 70.896 17.28 70.92 ;
    END
  END captured[323]
  PIN captured[324]
    DIRECTION OUTPUT ;
    USE SIGNAL ;
    PORT
      LAYER M4 ;
        RECT  17.196 70.992 17.28 71.016 ;
    END
  END captured[324]
  PIN captured[325]
    DIRECTION OUTPUT ;
    USE SIGNAL ;
    PORT
      LAYER M4 ;
        RECT  17.196 71.088 17.28 71.112 ;
    END
  END captured[325]
  PIN captured[326]
    DIRECTION OUTPUT ;
    USE SIGNAL ;
    PORT
      LAYER M4 ;
        RECT  17.196 71.184 17.28 71.208 ;
    END
  END captured[326]
  PIN captured[327]
    DIRECTION OUTPUT ;
    USE SIGNAL ;
    PORT
      LAYER M4 ;
        RECT  17.196 71.28 17.28 71.304 ;
    END
  END captured[327]
  PIN captured[328]
    DIRECTION OUTPUT ;
    USE SIGNAL ;
    PORT
      LAYER M4 ;
        RECT  17.196 71.376 17.28 71.4 ;
    END
  END captured[328]
  PIN captured[329]
    DIRECTION OUTPUT ;
    USE SIGNAL ;
    PORT
      LAYER M4 ;
        RECT  17.196 71.472 17.28 71.496 ;
    END
  END captured[329]
  PIN captured[32]
    DIRECTION OUTPUT ;
    USE SIGNAL ;
    PORT
      LAYER M4 ;
        RECT  17.196 54.48 17.28 54.504 ;
    END
  END captured[32]
  PIN captured[330]
    DIRECTION OUTPUT ;
    USE SIGNAL ;
    PORT
      LAYER M4 ;
        RECT  17.196 71.568 17.28 71.592 ;
    END
  END captured[330]
  PIN captured[331]
    DIRECTION OUTPUT ;
    USE SIGNAL ;
    PORT
      LAYER M4 ;
        RECT  17.196 71.664 17.28 71.688 ;
    END
  END captured[331]
  PIN captured[332]
    DIRECTION OUTPUT ;
    USE SIGNAL ;
    PORT
      LAYER M4 ;
        RECT  17.196 71.76 17.28 71.784 ;
    END
  END captured[332]
  PIN captured[333]
    DIRECTION OUTPUT ;
    USE SIGNAL ;
    PORT
      LAYER M4 ;
        RECT  17.196 71.856 17.28 71.88 ;
    END
  END captured[333]
  PIN captured[334]
    DIRECTION OUTPUT ;
    USE SIGNAL ;
    PORT
      LAYER M4 ;
        RECT  17.196 71.952 17.28 71.976 ;
    END
  END captured[334]
  PIN captured[335]
    DIRECTION OUTPUT ;
    USE SIGNAL ;
    PORT
      LAYER M4 ;
        RECT  17.196 72.048 17.28 72.072 ;
    END
  END captured[335]
  PIN captured[336]
    DIRECTION OUTPUT ;
    USE SIGNAL ;
    PORT
      LAYER M4 ;
        RECT  17.196 72.144 17.28 72.168 ;
    END
  END captured[336]
  PIN captured[337]
    DIRECTION OUTPUT ;
    USE SIGNAL ;
    PORT
      LAYER M4 ;
        RECT  17.196 72.24 17.28 72.264 ;
    END
  END captured[337]
  PIN captured[338]
    DIRECTION OUTPUT ;
    USE SIGNAL ;
    PORT
      LAYER M4 ;
        RECT  17.196 72.336 17.28 72.36 ;
    END
  END captured[338]
  PIN captured[339]
    DIRECTION OUTPUT ;
    USE SIGNAL ;
    PORT
      LAYER M4 ;
        RECT  17.196 72.432 17.28 72.456 ;
    END
  END captured[339]
  PIN captured[33]
    DIRECTION OUTPUT ;
    USE SIGNAL ;
    PORT
      LAYER M4 ;
        RECT  17.196 54.576 17.28 54.6 ;
    END
  END captured[33]
  PIN captured[340]
    DIRECTION OUTPUT ;
    USE SIGNAL ;
    PORT
      LAYER M4 ;
        RECT  17.196 72.528 17.28 72.552 ;
    END
  END captured[340]
  PIN captured[341]
    DIRECTION OUTPUT ;
    USE SIGNAL ;
    PORT
      LAYER M4 ;
        RECT  17.196 72.624 17.28 72.648 ;
    END
  END captured[341]
  PIN captured[342]
    DIRECTION OUTPUT ;
    USE SIGNAL ;
    PORT
      LAYER M4 ;
        RECT  17.196 72.72 17.28 72.744 ;
    END
  END captured[342]
  PIN captured[343]
    DIRECTION OUTPUT ;
    USE SIGNAL ;
    PORT
      LAYER M4 ;
        RECT  17.196 72.816 17.28 72.84 ;
    END
  END captured[343]
  PIN captured[344]
    DIRECTION OUTPUT ;
    USE SIGNAL ;
    PORT
      LAYER M4 ;
        RECT  17.196 72.912 17.28 72.936 ;
    END
  END captured[344]
  PIN captured[345]
    DIRECTION OUTPUT ;
    USE SIGNAL ;
    PORT
      LAYER M4 ;
        RECT  17.196 73.008 17.28 73.032 ;
    END
  END captured[345]
  PIN captured[346]
    DIRECTION OUTPUT ;
    USE SIGNAL ;
    PORT
      LAYER M4 ;
        RECT  17.196 73.104 17.28 73.128 ;
    END
  END captured[346]
  PIN captured[347]
    DIRECTION OUTPUT ;
    USE SIGNAL ;
    PORT
      LAYER M4 ;
        RECT  17.196 73.2 17.28 73.224 ;
    END
  END captured[347]
  PIN captured[348]
    DIRECTION OUTPUT ;
    USE SIGNAL ;
    PORT
      LAYER M4 ;
        RECT  17.196 73.296 17.28 73.32 ;
    END
  END captured[348]
  PIN captured[349]
    DIRECTION OUTPUT ;
    USE SIGNAL ;
    PORT
      LAYER M4 ;
        RECT  17.196 73.392 17.28 73.416 ;
    END
  END captured[349]
  PIN captured[34]
    DIRECTION OUTPUT ;
    USE SIGNAL ;
    PORT
      LAYER M4 ;
        RECT  17.196 54.672 17.28 54.696 ;
    END
  END captured[34]
  PIN captured[350]
    DIRECTION OUTPUT ;
    USE SIGNAL ;
    PORT
      LAYER M4 ;
        RECT  17.196 73.488 17.28 73.512 ;
    END
  END captured[350]
  PIN captured[351]
    DIRECTION OUTPUT ;
    USE SIGNAL ;
    PORT
      LAYER M4 ;
        RECT  17.196 73.584 17.28 73.608 ;
    END
  END captured[351]
  PIN captured[352]
    DIRECTION OUTPUT ;
    USE SIGNAL ;
    PORT
      LAYER M4 ;
        RECT  17.196 67.536 17.28 67.56 ;
    END
  END captured[352]
  PIN captured[353]
    DIRECTION OUTPUT ;
    USE SIGNAL ;
    PORT
      LAYER M4 ;
        RECT  17.196 67.632 17.28 67.656 ;
    END
  END captured[353]
  PIN captured[354]
    DIRECTION OUTPUT ;
    USE SIGNAL ;
    PORT
      LAYER M4 ;
        RECT  17.196 67.728 17.28 67.752 ;
    END
  END captured[354]
  PIN captured[355]
    DIRECTION OUTPUT ;
    USE SIGNAL ;
    PORT
      LAYER M4 ;
        RECT  17.196 67.824 17.28 67.848 ;
    END
  END captured[355]
  PIN captured[356]
    DIRECTION OUTPUT ;
    USE SIGNAL ;
    PORT
      LAYER M4 ;
        RECT  17.196 67.92 17.28 67.944 ;
    END
  END captured[356]
  PIN captured[357]
    DIRECTION OUTPUT ;
    USE SIGNAL ;
    PORT
      LAYER M4 ;
        RECT  17.196 68.016 17.28 68.04 ;
    END
  END captured[357]
  PIN captured[358]
    DIRECTION OUTPUT ;
    USE SIGNAL ;
    PORT
      LAYER M4 ;
        RECT  17.196 68.112 17.28 68.136 ;
    END
  END captured[358]
  PIN captured[359]
    DIRECTION OUTPUT ;
    USE SIGNAL ;
    PORT
      LAYER M4 ;
        RECT  17.196 68.208 17.28 68.232 ;
    END
  END captured[359]
  PIN captured[35]
    DIRECTION OUTPUT ;
    USE SIGNAL ;
    PORT
      LAYER M4 ;
        RECT  17.196 54.768 17.28 54.792 ;
    END
  END captured[35]
  PIN captured[360]
    DIRECTION OUTPUT ;
    USE SIGNAL ;
    PORT
      LAYER M4 ;
        RECT  17.196 68.304 17.28 68.328 ;
    END
  END captured[360]
  PIN captured[361]
    DIRECTION OUTPUT ;
    USE SIGNAL ;
    PORT
      LAYER M4 ;
        RECT  17.196 68.4 17.28 68.424 ;
    END
  END captured[361]
  PIN captured[362]
    DIRECTION OUTPUT ;
    USE SIGNAL ;
    PORT
      LAYER M4 ;
        RECT  17.196 68.496 17.28 68.52 ;
    END
  END captured[362]
  PIN captured[363]
    DIRECTION OUTPUT ;
    USE SIGNAL ;
    PORT
      LAYER M4 ;
        RECT  17.196 68.592 17.28 68.616 ;
    END
  END captured[363]
  PIN captured[364]
    DIRECTION OUTPUT ;
    USE SIGNAL ;
    PORT
      LAYER M4 ;
        RECT  17.196 68.688 17.28 68.712 ;
    END
  END captured[364]
  PIN captured[365]
    DIRECTION OUTPUT ;
    USE SIGNAL ;
    PORT
      LAYER M4 ;
        RECT  17.196 68.784 17.28 68.808 ;
    END
  END captured[365]
  PIN captured[366]
    DIRECTION OUTPUT ;
    USE SIGNAL ;
    PORT
      LAYER M4 ;
        RECT  17.196 68.88 17.28 68.904 ;
    END
  END captured[366]
  PIN captured[367]
    DIRECTION OUTPUT ;
    USE SIGNAL ;
    PORT
      LAYER M4 ;
        RECT  17.196 68.976 17.28 69 ;
    END
  END captured[367]
  PIN captured[368]
    DIRECTION OUTPUT ;
    USE SIGNAL ;
    PORT
      LAYER M4 ;
        RECT  17.196 69.072 17.28 69.096 ;
    END
  END captured[368]
  PIN captured[369]
    DIRECTION OUTPUT ;
    USE SIGNAL ;
    PORT
      LAYER M4 ;
        RECT  17.196 69.168 17.28 69.192 ;
    END
  END captured[369]
  PIN captured[36]
    DIRECTION OUTPUT ;
    USE SIGNAL ;
    PORT
      LAYER M4 ;
        RECT  17.196 54.864 17.28 54.888 ;
    END
  END captured[36]
  PIN captured[370]
    DIRECTION OUTPUT ;
    USE SIGNAL ;
    PORT
      LAYER M4 ;
        RECT  17.196 69.264 17.28 69.288 ;
    END
  END captured[370]
  PIN captured[371]
    DIRECTION OUTPUT ;
    USE SIGNAL ;
    PORT
      LAYER M4 ;
        RECT  17.196 69.36 17.28 69.384 ;
    END
  END captured[371]
  PIN captured[372]
    DIRECTION OUTPUT ;
    USE SIGNAL ;
    PORT
      LAYER M4 ;
        RECT  17.196 69.456 17.28 69.48 ;
    END
  END captured[372]
  PIN captured[373]
    DIRECTION OUTPUT ;
    USE SIGNAL ;
    PORT
      LAYER M4 ;
        RECT  17.196 69.552 17.28 69.576 ;
    END
  END captured[373]
  PIN captured[374]
    DIRECTION OUTPUT ;
    USE SIGNAL ;
    PORT
      LAYER M4 ;
        RECT  17.196 69.648 17.28 69.672 ;
    END
  END captured[374]
  PIN captured[375]
    DIRECTION OUTPUT ;
    USE SIGNAL ;
    PORT
      LAYER M4 ;
        RECT  17.196 69.744 17.28 69.768 ;
    END
  END captured[375]
  PIN captured[376]
    DIRECTION OUTPUT ;
    USE SIGNAL ;
    PORT
      LAYER M4 ;
        RECT  17.196 69.84 17.28 69.864 ;
    END
  END captured[376]
  PIN captured[377]
    DIRECTION OUTPUT ;
    USE SIGNAL ;
    PORT
      LAYER M4 ;
        RECT  17.196 69.936 17.28 69.96 ;
    END
  END captured[377]
  PIN captured[378]
    DIRECTION OUTPUT ;
    USE SIGNAL ;
    PORT
      LAYER M4 ;
        RECT  17.196 70.032 17.28 70.056 ;
    END
  END captured[378]
  PIN captured[379]
    DIRECTION OUTPUT ;
    USE SIGNAL ;
    PORT
      LAYER M4 ;
        RECT  17.196 70.128 17.28 70.152 ;
    END
  END captured[379]
  PIN captured[37]
    DIRECTION OUTPUT ;
    USE SIGNAL ;
    PORT
      LAYER M4 ;
        RECT  17.196 54.96 17.28 54.984 ;
    END
  END captured[37]
  PIN captured[380]
    DIRECTION OUTPUT ;
    USE SIGNAL ;
    PORT
      LAYER M4 ;
        RECT  17.196 70.224 17.28 70.248 ;
    END
  END captured[380]
  PIN captured[381]
    DIRECTION OUTPUT ;
    USE SIGNAL ;
    PORT
      LAYER M4 ;
        RECT  17.196 70.32 17.28 70.344 ;
    END
  END captured[381]
  PIN captured[382]
    DIRECTION OUTPUT ;
    USE SIGNAL ;
    PORT
      LAYER M4 ;
        RECT  17.196 70.416 17.28 70.44 ;
    END
  END captured[382]
  PIN captured[383]
    DIRECTION OUTPUT ;
    USE SIGNAL ;
    PORT
      LAYER M4 ;
        RECT  17.196 70.512 17.28 70.536 ;
    END
  END captured[383]
  PIN captured[384]
    DIRECTION OUTPUT ;
    USE SIGNAL ;
    PORT
      LAYER M4 ;
        RECT  17.196 73.68 17.28 73.704 ;
    END
  END captured[384]
  PIN captured[385]
    DIRECTION OUTPUT ;
    USE SIGNAL ;
    PORT
      LAYER M4 ;
        RECT  17.196 73.776 17.28 73.8 ;
    END
  END captured[385]
  PIN captured[386]
    DIRECTION OUTPUT ;
    USE SIGNAL ;
    PORT
      LAYER M4 ;
        RECT  17.196 73.872 17.28 73.896 ;
    END
  END captured[386]
  PIN captured[387]
    DIRECTION OUTPUT ;
    USE SIGNAL ;
    PORT
      LAYER M4 ;
        RECT  17.196 73.968 17.28 73.992 ;
    END
  END captured[387]
  PIN captured[388]
    DIRECTION OUTPUT ;
    USE SIGNAL ;
    PORT
      LAYER M4 ;
        RECT  17.196 74.064 17.28 74.088 ;
    END
  END captured[388]
  PIN captured[389]
    DIRECTION OUTPUT ;
    USE SIGNAL ;
    PORT
      LAYER M4 ;
        RECT  17.196 74.16 17.28 74.184 ;
    END
  END captured[389]
  PIN captured[38]
    DIRECTION OUTPUT ;
    USE SIGNAL ;
    PORT
      LAYER M4 ;
        RECT  17.196 55.056 17.28 55.08 ;
    END
  END captured[38]
  PIN captured[390]
    DIRECTION OUTPUT ;
    USE SIGNAL ;
    PORT
      LAYER M4 ;
        RECT  17.196 74.256 17.28 74.28 ;
    END
  END captured[390]
  PIN captured[391]
    DIRECTION OUTPUT ;
    USE SIGNAL ;
    PORT
      LAYER M4 ;
        RECT  17.196 74.352 17.28 74.376 ;
    END
  END captured[391]
  PIN captured[392]
    DIRECTION OUTPUT ;
    USE SIGNAL ;
    PORT
      LAYER M4 ;
        RECT  17.196 74.448 17.28 74.472 ;
    END
  END captured[392]
  PIN captured[393]
    DIRECTION OUTPUT ;
    USE SIGNAL ;
    PORT
      LAYER M4 ;
        RECT  17.196 74.544 17.28 74.568 ;
    END
  END captured[393]
  PIN captured[394]
    DIRECTION OUTPUT ;
    USE SIGNAL ;
    PORT
      LAYER M4 ;
        RECT  17.196 74.64 17.28 74.664 ;
    END
  END captured[394]
  PIN captured[395]
    DIRECTION OUTPUT ;
    USE SIGNAL ;
    PORT
      LAYER M4 ;
        RECT  17.196 74.736 17.28 74.76 ;
    END
  END captured[395]
  PIN captured[396]
    DIRECTION OUTPUT ;
    USE SIGNAL ;
    PORT
      LAYER M4 ;
        RECT  17.196 74.832 17.28 74.856 ;
    END
  END captured[396]
  PIN captured[397]
    DIRECTION OUTPUT ;
    USE SIGNAL ;
    PORT
      LAYER M4 ;
        RECT  17.196 74.928 17.28 74.952 ;
    END
  END captured[397]
  PIN captured[398]
    DIRECTION OUTPUT ;
    USE SIGNAL ;
    PORT
      LAYER M4 ;
        RECT  17.196 75.024 17.28 75.048 ;
    END
  END captured[398]
  PIN captured[399]
    DIRECTION OUTPUT ;
    USE SIGNAL ;
    PORT
      LAYER M4 ;
        RECT  17.196 75.12 17.28 75.144 ;
    END
  END captured[399]
  PIN captured[39]
    DIRECTION OUTPUT ;
    USE SIGNAL ;
    PORT
      LAYER M4 ;
        RECT  17.196 55.152 17.28 55.176 ;
    END
  END captured[39]
  PIN captured[3]
    DIRECTION OUTPUT ;
    USE SIGNAL ;
    PORT
      LAYER M4 ;
        RECT  17.196 42.48 17.28 42.504 ;
    END
  END captured[3]
  PIN captured[400]
    DIRECTION OUTPUT ;
    USE SIGNAL ;
    PORT
      LAYER M4 ;
        RECT  17.196 75.216 17.28 75.24 ;
    END
  END captured[400]
  PIN captured[401]
    DIRECTION OUTPUT ;
    USE SIGNAL ;
    PORT
      LAYER M4 ;
        RECT  17.196 75.312 17.28 75.336 ;
    END
  END captured[401]
  PIN captured[402]
    DIRECTION OUTPUT ;
    USE SIGNAL ;
    PORT
      LAYER M4 ;
        RECT  17.196 75.408 17.28 75.432 ;
    END
  END captured[402]
  PIN captured[403]
    DIRECTION OUTPUT ;
    USE SIGNAL ;
    PORT
      LAYER M4 ;
        RECT  17.196 75.504 17.28 75.528 ;
    END
  END captured[403]
  PIN captured[404]
    DIRECTION OUTPUT ;
    USE SIGNAL ;
    PORT
      LAYER M4 ;
        RECT  17.196 75.6 17.28 75.624 ;
    END
  END captured[404]
  PIN captured[405]
    DIRECTION OUTPUT ;
    USE SIGNAL ;
    PORT
      LAYER M4 ;
        RECT  17.196 75.696 17.28 75.72 ;
    END
  END captured[405]
  PIN captured[406]
    DIRECTION OUTPUT ;
    USE SIGNAL ;
    PORT
      LAYER M4 ;
        RECT  17.196 75.792 17.28 75.816 ;
    END
  END captured[406]
  PIN captured[407]
    DIRECTION OUTPUT ;
    USE SIGNAL ;
    PORT
      LAYER M4 ;
        RECT  17.196 75.888 17.28 75.912 ;
    END
  END captured[407]
  PIN captured[408]
    DIRECTION OUTPUT ;
    USE SIGNAL ;
    PORT
      LAYER M4 ;
        RECT  17.196 75.984 17.28 76.008 ;
    END
  END captured[408]
  PIN captured[409]
    DIRECTION OUTPUT ;
    USE SIGNAL ;
    PORT
      LAYER M4 ;
        RECT  17.196 76.08 17.28 76.104 ;
    END
  END captured[409]
  PIN captured[40]
    DIRECTION OUTPUT ;
    USE SIGNAL ;
    PORT
      LAYER M4 ;
        RECT  17.196 55.248 17.28 55.272 ;
    END
  END captured[40]
  PIN captured[410]
    DIRECTION OUTPUT ;
    USE SIGNAL ;
    PORT
      LAYER M4 ;
        RECT  17.196 76.176 17.28 76.2 ;
    END
  END captured[410]
  PIN captured[411]
    DIRECTION OUTPUT ;
    USE SIGNAL ;
    PORT
      LAYER M4 ;
        RECT  17.196 76.272 17.28 76.296 ;
    END
  END captured[411]
  PIN captured[412]
    DIRECTION OUTPUT ;
    USE SIGNAL ;
    PORT
      LAYER M4 ;
        RECT  17.196 76.368 17.28 76.392 ;
    END
  END captured[412]
  PIN captured[413]
    DIRECTION OUTPUT ;
    USE SIGNAL ;
    PORT
      LAYER M4 ;
        RECT  17.196 76.464 17.28 76.488 ;
    END
  END captured[413]
  PIN captured[414]
    DIRECTION OUTPUT ;
    USE SIGNAL ;
    PORT
      LAYER M4 ;
        RECT  17.196 76.56 17.28 76.584 ;
    END
  END captured[414]
  PIN captured[415]
    DIRECTION OUTPUT ;
    USE SIGNAL ;
    PORT
      LAYER M4 ;
        RECT  17.196 76.656 17.28 76.68 ;
    END
  END captured[415]
  PIN captured[416]
    DIRECTION OUTPUT ;
    USE SIGNAL ;
    PORT
      LAYER M4 ;
        RECT  17.196 26.064 17.28 26.088 ;
    END
  END captured[416]
  PIN captured[417]
    DIRECTION OUTPUT ;
    USE SIGNAL ;
    PORT
      LAYER M4 ;
        RECT  17.196 26.16 17.28 26.184 ;
    END
  END captured[417]
  PIN captured[418]
    DIRECTION OUTPUT ;
    USE SIGNAL ;
    PORT
      LAYER M4 ;
        RECT  17.196 26.256 17.28 26.28 ;
    END
  END captured[418]
  PIN captured[419]
    DIRECTION OUTPUT ;
    USE SIGNAL ;
    PORT
      LAYER M4 ;
        RECT  17.196 26.352 17.28 26.376 ;
    END
  END captured[419]
  PIN captured[41]
    DIRECTION OUTPUT ;
    USE SIGNAL ;
    PORT
      LAYER M4 ;
        RECT  17.196 55.344 17.28 55.368 ;
    END
  END captured[41]
  PIN captured[420]
    DIRECTION OUTPUT ;
    USE SIGNAL ;
    PORT
      LAYER M4 ;
        RECT  17.196 26.448 17.28 26.472 ;
    END
  END captured[420]
  PIN captured[421]
    DIRECTION OUTPUT ;
    USE SIGNAL ;
    PORT
      LAYER M4 ;
        RECT  17.196 26.544 17.28 26.568 ;
    END
  END captured[421]
  PIN captured[422]
    DIRECTION OUTPUT ;
    USE SIGNAL ;
    PORT
      LAYER M4 ;
        RECT  17.196 26.64 17.28 26.664 ;
    END
  END captured[422]
  PIN captured[423]
    DIRECTION OUTPUT ;
    USE SIGNAL ;
    PORT
      LAYER M4 ;
        RECT  17.196 26.736 17.28 26.76 ;
    END
  END captured[423]
  PIN captured[424]
    DIRECTION OUTPUT ;
    USE SIGNAL ;
    PORT
      LAYER M4 ;
        RECT  17.196 26.832 17.28 26.856 ;
    END
  END captured[424]
  PIN captured[425]
    DIRECTION OUTPUT ;
    USE SIGNAL ;
    PORT
      LAYER M4 ;
        RECT  17.196 26.928 17.28 26.952 ;
    END
  END captured[425]
  PIN captured[426]
    DIRECTION OUTPUT ;
    USE SIGNAL ;
    PORT
      LAYER M4 ;
        RECT  17.196 27.024 17.28 27.048 ;
    END
  END captured[426]
  PIN captured[427]
    DIRECTION OUTPUT ;
    USE SIGNAL ;
    PORT
      LAYER M4 ;
        RECT  17.196 27.12 17.28 27.144 ;
    END
  END captured[427]
  PIN captured[428]
    DIRECTION OUTPUT ;
    USE SIGNAL ;
    PORT
      LAYER M4 ;
        RECT  17.196 27.216 17.28 27.24 ;
    END
  END captured[428]
  PIN captured[429]
    DIRECTION OUTPUT ;
    USE SIGNAL ;
    PORT
      LAYER M4 ;
        RECT  17.196 27.312 17.28 27.336 ;
    END
  END captured[429]
  PIN captured[42]
    DIRECTION OUTPUT ;
    USE SIGNAL ;
    PORT
      LAYER M4 ;
        RECT  17.196 55.44 17.28 55.464 ;
    END
  END captured[42]
  PIN captured[430]
    DIRECTION OUTPUT ;
    USE SIGNAL ;
    PORT
      LAYER M4 ;
        RECT  17.196 27.408 17.28 27.432 ;
    END
  END captured[430]
  PIN captured[431]
    DIRECTION OUTPUT ;
    USE SIGNAL ;
    PORT
      LAYER M4 ;
        RECT  17.196 27.504 17.28 27.528 ;
    END
  END captured[431]
  PIN captured[432]
    DIRECTION OUTPUT ;
    USE SIGNAL ;
    PORT
      LAYER M4 ;
        RECT  17.196 27.6 17.28 27.624 ;
    END
  END captured[432]
  PIN captured[433]
    DIRECTION OUTPUT ;
    USE SIGNAL ;
    PORT
      LAYER M4 ;
        RECT  17.196 27.696 17.28 27.72 ;
    END
  END captured[433]
  PIN captured[434]
    DIRECTION OUTPUT ;
    USE SIGNAL ;
    PORT
      LAYER M4 ;
        RECT  17.196 27.792 17.28 27.816 ;
    END
  END captured[434]
  PIN captured[435]
    DIRECTION OUTPUT ;
    USE SIGNAL ;
    PORT
      LAYER M4 ;
        RECT  17.196 27.888 17.28 27.912 ;
    END
  END captured[435]
  PIN captured[436]
    DIRECTION OUTPUT ;
    USE SIGNAL ;
    PORT
      LAYER M4 ;
        RECT  17.196 27.984 17.28 28.008 ;
    END
  END captured[436]
  PIN captured[437]
    DIRECTION OUTPUT ;
    USE SIGNAL ;
    PORT
      LAYER M4 ;
        RECT  17.196 28.08 17.28 28.104 ;
    END
  END captured[437]
  PIN captured[438]
    DIRECTION OUTPUT ;
    USE SIGNAL ;
    PORT
      LAYER M4 ;
        RECT  17.196 28.176 17.28 28.2 ;
    END
  END captured[438]
  PIN captured[439]
    DIRECTION OUTPUT ;
    USE SIGNAL ;
    PORT
      LAYER M4 ;
        RECT  17.196 28.272 17.28 28.296 ;
    END
  END captured[439]
  PIN captured[43]
    DIRECTION OUTPUT ;
    USE SIGNAL ;
    PORT
      LAYER M4 ;
        RECT  17.196 55.536 17.28 55.56 ;
    END
  END captured[43]
  PIN captured[440]
    DIRECTION OUTPUT ;
    USE SIGNAL ;
    PORT
      LAYER M4 ;
        RECT  17.196 28.368 17.28 28.392 ;
    END
  END captured[440]
  PIN captured[441]
    DIRECTION OUTPUT ;
    USE SIGNAL ;
    PORT
      LAYER M4 ;
        RECT  17.196 28.464 17.28 28.488 ;
    END
  END captured[441]
  PIN captured[442]
    DIRECTION OUTPUT ;
    USE SIGNAL ;
    PORT
      LAYER M4 ;
        RECT  17.196 28.56 17.28 28.584 ;
    END
  END captured[442]
  PIN captured[443]
    DIRECTION OUTPUT ;
    USE SIGNAL ;
    PORT
      LAYER M4 ;
        RECT  17.196 28.656 17.28 28.68 ;
    END
  END captured[443]
  PIN captured[444]
    DIRECTION OUTPUT ;
    USE SIGNAL ;
    PORT
      LAYER M4 ;
        RECT  17.196 28.752 17.28 28.776 ;
    END
  END captured[444]
  PIN captured[445]
    DIRECTION OUTPUT ;
    USE SIGNAL ;
    PORT
      LAYER M4 ;
        RECT  17.196 28.848 17.28 28.872 ;
    END
  END captured[445]
  PIN captured[446]
    DIRECTION OUTPUT ;
    USE SIGNAL ;
    PORT
      LAYER M4 ;
        RECT  17.196 28.944 17.28 28.968 ;
    END
  END captured[446]
  PIN captured[447]
    DIRECTION OUTPUT ;
    USE SIGNAL ;
    PORT
      LAYER M4 ;
        RECT  17.196 29.04 17.28 29.064 ;
    END
  END captured[447]
  PIN captured[448]
    DIRECTION OUTPUT ;
    USE SIGNAL ;
    PORT
      LAYER M4 ;
        RECT  17.196 35.28 17.28 35.304 ;
    END
  END captured[448]
  PIN captured[449]
    DIRECTION OUTPUT ;
    USE SIGNAL ;
    PORT
      LAYER M4 ;
        RECT  17.196 35.376 17.28 35.4 ;
    END
  END captured[449]
  PIN captured[44]
    DIRECTION OUTPUT ;
    USE SIGNAL ;
    PORT
      LAYER M4 ;
        RECT  17.196 55.632 17.28 55.656 ;
    END
  END captured[44]
  PIN captured[450]
    DIRECTION OUTPUT ;
    USE SIGNAL ;
    PORT
      LAYER M4 ;
        RECT  17.196 35.472 17.28 35.496 ;
    END
  END captured[450]
  PIN captured[451]
    DIRECTION OUTPUT ;
    USE SIGNAL ;
    PORT
      LAYER M4 ;
        RECT  17.196 35.568 17.28 35.592 ;
    END
  END captured[451]
  PIN captured[452]
    DIRECTION OUTPUT ;
    USE SIGNAL ;
    PORT
      LAYER M4 ;
        RECT  17.196 35.664 17.28 35.688 ;
    END
  END captured[452]
  PIN captured[453]
    DIRECTION OUTPUT ;
    USE SIGNAL ;
    PORT
      LAYER M4 ;
        RECT  17.196 35.76 17.28 35.784 ;
    END
  END captured[453]
  PIN captured[454]
    DIRECTION OUTPUT ;
    USE SIGNAL ;
    PORT
      LAYER M4 ;
        RECT  17.196 35.856 17.28 35.88 ;
    END
  END captured[454]
  PIN captured[455]
    DIRECTION OUTPUT ;
    USE SIGNAL ;
    PORT
      LAYER M4 ;
        RECT  17.196 35.952 17.28 35.976 ;
    END
  END captured[455]
  PIN captured[456]
    DIRECTION OUTPUT ;
    USE SIGNAL ;
    PORT
      LAYER M4 ;
        RECT  17.196 36.048 17.28 36.072 ;
    END
  END captured[456]
  PIN captured[457]
    DIRECTION OUTPUT ;
    USE SIGNAL ;
    PORT
      LAYER M4 ;
        RECT  17.196 36.144 17.28 36.168 ;
    END
  END captured[457]
  PIN captured[458]
    DIRECTION OUTPUT ;
    USE SIGNAL ;
    PORT
      LAYER M4 ;
        RECT  17.196 36.24 17.28 36.264 ;
    END
  END captured[458]
  PIN captured[459]
    DIRECTION OUTPUT ;
    USE SIGNAL ;
    PORT
      LAYER M4 ;
        RECT  17.196 36.336 17.28 36.36 ;
    END
  END captured[459]
  PIN captured[45]
    DIRECTION OUTPUT ;
    USE SIGNAL ;
    PORT
      LAYER M4 ;
        RECT  17.196 55.728 17.28 55.752 ;
    END
  END captured[45]
  PIN captured[460]
    DIRECTION OUTPUT ;
    USE SIGNAL ;
    PORT
      LAYER M4 ;
        RECT  17.196 36.432 17.28 36.456 ;
    END
  END captured[460]
  PIN captured[461]
    DIRECTION OUTPUT ;
    USE SIGNAL ;
    PORT
      LAYER M4 ;
        RECT  17.196 36.528 17.28 36.552 ;
    END
  END captured[461]
  PIN captured[462]
    DIRECTION OUTPUT ;
    USE SIGNAL ;
    PORT
      LAYER M4 ;
        RECT  17.196 36.624 17.28 36.648 ;
    END
  END captured[462]
  PIN captured[463]
    DIRECTION OUTPUT ;
    USE SIGNAL ;
    PORT
      LAYER M4 ;
        RECT  17.196 36.72 17.28 36.744 ;
    END
  END captured[463]
  PIN captured[464]
    DIRECTION OUTPUT ;
    USE SIGNAL ;
    PORT
      LAYER M4 ;
        RECT  17.196 36.816 17.28 36.84 ;
    END
  END captured[464]
  PIN captured[465]
    DIRECTION OUTPUT ;
    USE SIGNAL ;
    PORT
      LAYER M4 ;
        RECT  17.196 36.912 17.28 36.936 ;
    END
  END captured[465]
  PIN captured[466]
    DIRECTION OUTPUT ;
    USE SIGNAL ;
    PORT
      LAYER M4 ;
        RECT  17.196 37.008 17.28 37.032 ;
    END
  END captured[466]
  PIN captured[467]
    DIRECTION OUTPUT ;
    USE SIGNAL ;
    PORT
      LAYER M4 ;
        RECT  17.196 37.104 17.28 37.128 ;
    END
  END captured[467]
  PIN captured[468]
    DIRECTION OUTPUT ;
    USE SIGNAL ;
    PORT
      LAYER M4 ;
        RECT  17.196 37.2 17.28 37.224 ;
    END
  END captured[468]
  PIN captured[469]
    DIRECTION OUTPUT ;
    USE SIGNAL ;
    PORT
      LAYER M4 ;
        RECT  17.196 37.296 17.28 37.32 ;
    END
  END captured[469]
  PIN captured[46]
    DIRECTION OUTPUT ;
    USE SIGNAL ;
    PORT
      LAYER M4 ;
        RECT  17.196 55.824 17.28 55.848 ;
    END
  END captured[46]
  PIN captured[470]
    DIRECTION OUTPUT ;
    USE SIGNAL ;
    PORT
      LAYER M4 ;
        RECT  17.196 37.392 17.28 37.416 ;
    END
  END captured[470]
  PIN captured[471]
    DIRECTION OUTPUT ;
    USE SIGNAL ;
    PORT
      LAYER M4 ;
        RECT  17.196 37.488 17.28 37.512 ;
    END
  END captured[471]
  PIN captured[472]
    DIRECTION OUTPUT ;
    USE SIGNAL ;
    PORT
      LAYER M4 ;
        RECT  17.196 37.584 17.28 37.608 ;
    END
  END captured[472]
  PIN captured[473]
    DIRECTION OUTPUT ;
    USE SIGNAL ;
    PORT
      LAYER M4 ;
        RECT  17.196 37.68 17.28 37.704 ;
    END
  END captured[473]
  PIN captured[474]
    DIRECTION OUTPUT ;
    USE SIGNAL ;
    PORT
      LAYER M4 ;
        RECT  17.196 37.776 17.28 37.8 ;
    END
  END captured[474]
  PIN captured[475]
    DIRECTION OUTPUT ;
    USE SIGNAL ;
    PORT
      LAYER M4 ;
        RECT  17.196 37.872 17.28 37.896 ;
    END
  END captured[475]
  PIN captured[476]
    DIRECTION OUTPUT ;
    USE SIGNAL ;
    PORT
      LAYER M4 ;
        RECT  17.196 37.968 17.28 37.992 ;
    END
  END captured[476]
  PIN captured[477]
    DIRECTION OUTPUT ;
    USE SIGNAL ;
    PORT
      LAYER M4 ;
        RECT  17.196 38.064 17.28 38.088 ;
    END
  END captured[477]
  PIN captured[478]
    DIRECTION OUTPUT ;
    USE SIGNAL ;
    PORT
      LAYER M4 ;
        RECT  17.196 38.16 17.28 38.184 ;
    END
  END captured[478]
  PIN captured[479]
    DIRECTION OUTPUT ;
    USE SIGNAL ;
    PORT
      LAYER M4 ;
        RECT  17.196 38.256 17.28 38.28 ;
    END
  END captured[479]
  PIN captured[47]
    DIRECTION OUTPUT ;
    USE SIGNAL ;
    PORT
      LAYER M4 ;
        RECT  17.196 55.92 17.28 55.944 ;
    END
  END captured[47]
  PIN captured[480]
    DIRECTION OUTPUT ;
    USE SIGNAL ;
    PORT
      LAYER M4 ;
        RECT  17.196 29.136 17.28 29.16 ;
    END
  END captured[480]
  PIN captured[481]
    DIRECTION OUTPUT ;
    USE SIGNAL ;
    PORT
      LAYER M4 ;
        RECT  17.196 29.232 17.28 29.256 ;
    END
  END captured[481]
  PIN captured[482]
    DIRECTION OUTPUT ;
    USE SIGNAL ;
    PORT
      LAYER M4 ;
        RECT  17.196 29.328 17.28 29.352 ;
    END
  END captured[482]
  PIN captured[483]
    DIRECTION OUTPUT ;
    USE SIGNAL ;
    PORT
      LAYER M4 ;
        RECT  17.196 29.424 17.28 29.448 ;
    END
  END captured[483]
  PIN captured[484]
    DIRECTION OUTPUT ;
    USE SIGNAL ;
    PORT
      LAYER M4 ;
        RECT  17.196 29.52 17.28 29.544 ;
    END
  END captured[484]
  PIN captured[485]
    DIRECTION OUTPUT ;
    USE SIGNAL ;
    PORT
      LAYER M4 ;
        RECT  17.196 29.616 17.28 29.64 ;
    END
  END captured[485]
  PIN captured[486]
    DIRECTION OUTPUT ;
    USE SIGNAL ;
    PORT
      LAYER M4 ;
        RECT  17.196 29.712 17.28 29.736 ;
    END
  END captured[486]
  PIN captured[487]
    DIRECTION OUTPUT ;
    USE SIGNAL ;
    PORT
      LAYER M4 ;
        RECT  17.196 29.808 17.28 29.832 ;
    END
  END captured[487]
  PIN captured[488]
    DIRECTION OUTPUT ;
    USE SIGNAL ;
    PORT
      LAYER M4 ;
        RECT  17.196 29.904 17.28 29.928 ;
    END
  END captured[488]
  PIN captured[489]
    DIRECTION OUTPUT ;
    USE SIGNAL ;
    PORT
      LAYER M4 ;
        RECT  17.196 30 17.28 30.024 ;
    END
  END captured[489]
  PIN captured[48]
    DIRECTION OUTPUT ;
    USE SIGNAL ;
    PORT
      LAYER M4 ;
        RECT  17.196 56.016 17.28 56.04 ;
    END
  END captured[48]
  PIN captured[490]
    DIRECTION OUTPUT ;
    USE SIGNAL ;
    PORT
      LAYER M4 ;
        RECT  17.196 30.096 17.28 30.12 ;
    END
  END captured[490]
  PIN captured[491]
    DIRECTION OUTPUT ;
    USE SIGNAL ;
    PORT
      LAYER M4 ;
        RECT  17.196 30.192 17.28 30.216 ;
    END
  END captured[491]
  PIN captured[492]
    DIRECTION OUTPUT ;
    USE SIGNAL ;
    PORT
      LAYER M4 ;
        RECT  17.196 30.288 17.28 30.312 ;
    END
  END captured[492]
  PIN captured[493]
    DIRECTION OUTPUT ;
    USE SIGNAL ;
    PORT
      LAYER M4 ;
        RECT  17.196 30.384 17.28 30.408 ;
    END
  END captured[493]
  PIN captured[494]
    DIRECTION OUTPUT ;
    USE SIGNAL ;
    PORT
      LAYER M4 ;
        RECT  17.196 30.48 17.28 30.504 ;
    END
  END captured[494]
  PIN captured[495]
    DIRECTION OUTPUT ;
    USE SIGNAL ;
    PORT
      LAYER M4 ;
        RECT  17.196 30.576 17.28 30.6 ;
    END
  END captured[495]
  PIN captured[496]
    DIRECTION OUTPUT ;
    USE SIGNAL ;
    PORT
      LAYER M4 ;
        RECT  17.196 30.672 17.28 30.696 ;
    END
  END captured[496]
  PIN captured[497]
    DIRECTION OUTPUT ;
    USE SIGNAL ;
    PORT
      LAYER M4 ;
        RECT  17.196 30.768 17.28 30.792 ;
    END
  END captured[497]
  PIN captured[498]
    DIRECTION OUTPUT ;
    USE SIGNAL ;
    PORT
      LAYER M4 ;
        RECT  17.196 30.864 17.28 30.888 ;
    END
  END captured[498]
  PIN captured[499]
    DIRECTION OUTPUT ;
    USE SIGNAL ;
    PORT
      LAYER M4 ;
        RECT  17.196 30.96 17.28 30.984 ;
    END
  END captured[499]
  PIN captured[49]
    DIRECTION OUTPUT ;
    USE SIGNAL ;
    PORT
      LAYER M4 ;
        RECT  17.196 56.112 17.28 56.136 ;
    END
  END captured[49]
  PIN captured[4]
    DIRECTION OUTPUT ;
    USE SIGNAL ;
    PORT
      LAYER M4 ;
        RECT  17.196 42.576 17.28 42.6 ;
    END
  END captured[4]
  PIN captured[500]
    DIRECTION OUTPUT ;
    USE SIGNAL ;
    PORT
      LAYER M4 ;
        RECT  17.196 31.056 17.28 31.08 ;
    END
  END captured[500]
  PIN captured[501]
    DIRECTION OUTPUT ;
    USE SIGNAL ;
    PORT
      LAYER M4 ;
        RECT  17.196 31.152 17.28 31.176 ;
    END
  END captured[501]
  PIN captured[502]
    DIRECTION OUTPUT ;
    USE SIGNAL ;
    PORT
      LAYER M4 ;
        RECT  17.196 31.248 17.28 31.272 ;
    END
  END captured[502]
  PIN captured[503]
    DIRECTION OUTPUT ;
    USE SIGNAL ;
    PORT
      LAYER M4 ;
        RECT  17.196 31.344 17.28 31.368 ;
    END
  END captured[503]
  PIN captured[504]
    DIRECTION OUTPUT ;
    USE SIGNAL ;
    PORT
      LAYER M4 ;
        RECT  17.196 31.44 17.28 31.464 ;
    END
  END captured[504]
  PIN captured[505]
    DIRECTION OUTPUT ;
    USE SIGNAL ;
    PORT
      LAYER M4 ;
        RECT  17.196 31.536 17.28 31.56 ;
    END
  END captured[505]
  PIN captured[506]
    DIRECTION OUTPUT ;
    USE SIGNAL ;
    PORT
      LAYER M4 ;
        RECT  17.196 31.632 17.28 31.656 ;
    END
  END captured[506]
  PIN captured[507]
    DIRECTION OUTPUT ;
    USE SIGNAL ;
    PORT
      LAYER M4 ;
        RECT  17.196 31.728 17.28 31.752 ;
    END
  END captured[507]
  PIN captured[508]
    DIRECTION OUTPUT ;
    USE SIGNAL ;
    PORT
      LAYER M4 ;
        RECT  17.196 31.824 17.28 31.848 ;
    END
  END captured[508]
  PIN captured[509]
    DIRECTION OUTPUT ;
    USE SIGNAL ;
    PORT
      LAYER M4 ;
        RECT  17.196 31.92 17.28 31.944 ;
    END
  END captured[509]
  PIN captured[50]
    DIRECTION OUTPUT ;
    USE SIGNAL ;
    PORT
      LAYER M4 ;
        RECT  17.196 56.208 17.28 56.232 ;
    END
  END captured[50]
  PIN captured[510]
    DIRECTION OUTPUT ;
    USE SIGNAL ;
    PORT
      LAYER M4 ;
        RECT  17.196 32.016 17.28 32.04 ;
    END
  END captured[510]
  PIN captured[511]
    DIRECTION OUTPUT ;
    USE SIGNAL ;
    PORT
      LAYER M4 ;
        RECT  17.196 32.112 17.28 32.136 ;
    END
  END captured[511]
  PIN captured[512]
    DIRECTION OUTPUT ;
    USE SIGNAL ;
    PORT
      LAYER M4 ;
        RECT  17.196 32.208 17.28 32.232 ;
    END
  END captured[512]
  PIN captured[513]
    DIRECTION OUTPUT ;
    USE SIGNAL ;
    PORT
      LAYER M4 ;
        RECT  17.196 32.304 17.28 32.328 ;
    END
  END captured[513]
  PIN captured[514]
    DIRECTION OUTPUT ;
    USE SIGNAL ;
    PORT
      LAYER M4 ;
        RECT  17.196 32.4 17.28 32.424 ;
    END
  END captured[514]
  PIN captured[515]
    DIRECTION OUTPUT ;
    USE SIGNAL ;
    PORT
      LAYER M4 ;
        RECT  17.196 32.496 17.28 32.52 ;
    END
  END captured[515]
  PIN captured[516]
    DIRECTION OUTPUT ;
    USE SIGNAL ;
    PORT
      LAYER M4 ;
        RECT  17.196 32.592 17.28 32.616 ;
    END
  END captured[516]
  PIN captured[517]
    DIRECTION OUTPUT ;
    USE SIGNAL ;
    PORT
      LAYER M4 ;
        RECT  17.196 32.688 17.28 32.712 ;
    END
  END captured[517]
  PIN captured[518]
    DIRECTION OUTPUT ;
    USE SIGNAL ;
    PORT
      LAYER M4 ;
        RECT  17.196 32.784 17.28 32.808 ;
    END
  END captured[518]
  PIN captured[519]
    DIRECTION OUTPUT ;
    USE SIGNAL ;
    PORT
      LAYER M4 ;
        RECT  17.196 32.88 17.28 32.904 ;
    END
  END captured[519]
  PIN captured[51]
    DIRECTION OUTPUT ;
    USE SIGNAL ;
    PORT
      LAYER M4 ;
        RECT  17.196 56.304 17.28 56.328 ;
    END
  END captured[51]
  PIN captured[520]
    DIRECTION OUTPUT ;
    USE SIGNAL ;
    PORT
      LAYER M4 ;
        RECT  17.196 32.976 17.28 33 ;
    END
  END captured[520]
  PIN captured[521]
    DIRECTION OUTPUT ;
    USE SIGNAL ;
    PORT
      LAYER M4 ;
        RECT  17.196 33.072 17.28 33.096 ;
    END
  END captured[521]
  PIN captured[522]
    DIRECTION OUTPUT ;
    USE SIGNAL ;
    PORT
      LAYER M4 ;
        RECT  17.196 33.168 17.28 33.192 ;
    END
  END captured[522]
  PIN captured[523]
    DIRECTION OUTPUT ;
    USE SIGNAL ;
    PORT
      LAYER M4 ;
        RECT  17.196 33.264 17.28 33.288 ;
    END
  END captured[523]
  PIN captured[524]
    DIRECTION OUTPUT ;
    USE SIGNAL ;
    PORT
      LAYER M4 ;
        RECT  17.196 33.36 17.28 33.384 ;
    END
  END captured[524]
  PIN captured[525]
    DIRECTION OUTPUT ;
    USE SIGNAL ;
    PORT
      LAYER M4 ;
        RECT  17.196 33.456 17.28 33.48 ;
    END
  END captured[525]
  PIN captured[526]
    DIRECTION OUTPUT ;
    USE SIGNAL ;
    PORT
      LAYER M4 ;
        RECT  17.196 33.552 17.28 33.576 ;
    END
  END captured[526]
  PIN captured[527]
    DIRECTION OUTPUT ;
    USE SIGNAL ;
    PORT
      LAYER M4 ;
        RECT  17.196 33.648 17.28 33.672 ;
    END
  END captured[527]
  PIN captured[528]
    DIRECTION OUTPUT ;
    USE SIGNAL ;
    PORT
      LAYER M4 ;
        RECT  17.196 33.744 17.28 33.768 ;
    END
  END captured[528]
  PIN captured[529]
    DIRECTION OUTPUT ;
    USE SIGNAL ;
    PORT
      LAYER M4 ;
        RECT  17.196 33.84 17.28 33.864 ;
    END
  END captured[529]
  PIN captured[52]
    DIRECTION OUTPUT ;
    USE SIGNAL ;
    PORT
      LAYER M4 ;
        RECT  17.196 56.4 17.28 56.424 ;
    END
  END captured[52]
  PIN captured[530]
    DIRECTION OUTPUT ;
    USE SIGNAL ;
    PORT
      LAYER M4 ;
        RECT  17.196 33.936 17.28 33.96 ;
    END
  END captured[530]
  PIN captured[531]
    DIRECTION OUTPUT ;
    USE SIGNAL ;
    PORT
      LAYER M4 ;
        RECT  17.196 34.032 17.28 34.056 ;
    END
  END captured[531]
  PIN captured[532]
    DIRECTION OUTPUT ;
    USE SIGNAL ;
    PORT
      LAYER M4 ;
        RECT  17.196 34.128 17.28 34.152 ;
    END
  END captured[532]
  PIN captured[533]
    DIRECTION OUTPUT ;
    USE SIGNAL ;
    PORT
      LAYER M4 ;
        RECT  17.196 34.224 17.28 34.248 ;
    END
  END captured[533]
  PIN captured[534]
    DIRECTION OUTPUT ;
    USE SIGNAL ;
    PORT
      LAYER M4 ;
        RECT  17.196 34.32 17.28 34.344 ;
    END
  END captured[534]
  PIN captured[535]
    DIRECTION OUTPUT ;
    USE SIGNAL ;
    PORT
      LAYER M4 ;
        RECT  17.196 34.416 17.28 34.44 ;
    END
  END captured[535]
  PIN captured[536]
    DIRECTION OUTPUT ;
    USE SIGNAL ;
    PORT
      LAYER M4 ;
        RECT  17.196 34.512 17.28 34.536 ;
    END
  END captured[536]
  PIN captured[537]
    DIRECTION OUTPUT ;
    USE SIGNAL ;
    PORT
      LAYER M4 ;
        RECT  17.196 34.608 17.28 34.632 ;
    END
  END captured[537]
  PIN captured[538]
    DIRECTION OUTPUT ;
    USE SIGNAL ;
    PORT
      LAYER M4 ;
        RECT  17.196 34.704 17.28 34.728 ;
    END
  END captured[538]
  PIN captured[539]
    DIRECTION OUTPUT ;
    USE SIGNAL ;
    PORT
      LAYER M4 ;
        RECT  17.196 34.8 17.28 34.824 ;
    END
  END captured[539]
  PIN captured[53]
    DIRECTION OUTPUT ;
    USE SIGNAL ;
    PORT
      LAYER M4 ;
        RECT  17.196 56.496 17.28 56.52 ;
    END
  END captured[53]
  PIN captured[540]
    DIRECTION OUTPUT ;
    USE SIGNAL ;
    PORT
      LAYER M4 ;
        RECT  17.196 34.896 17.28 34.92 ;
    END
  END captured[540]
  PIN captured[541]
    DIRECTION OUTPUT ;
    USE SIGNAL ;
    PORT
      LAYER M4 ;
        RECT  17.196 34.992 17.28 35.016 ;
    END
  END captured[541]
  PIN captured[542]
    DIRECTION OUTPUT ;
    USE SIGNAL ;
    PORT
      LAYER M4 ;
        RECT  17.196 35.088 17.28 35.112 ;
    END
  END captured[542]
  PIN captured[543]
    DIRECTION OUTPUT ;
    USE SIGNAL ;
    PORT
      LAYER M4 ;
        RECT  17.196 35.184 17.28 35.208 ;
    END
  END captured[543]
  PIN captured[544]
    DIRECTION OUTPUT ;
    USE SIGNAL ;
    PORT
      LAYER M4 ;
        RECT  17.196 38.352 17.28 38.376 ;
    END
  END captured[544]
  PIN captured[54]
    DIRECTION OUTPUT ;
    USE SIGNAL ;
    PORT
      LAYER M4 ;
        RECT  17.196 56.592 17.28 56.616 ;
    END
  END captured[54]
  PIN captured[55]
    DIRECTION OUTPUT ;
    USE SIGNAL ;
    PORT
      LAYER M4 ;
        RECT  17.196 56.688 17.28 56.712 ;
    END
  END captured[55]
  PIN captured[56]
    DIRECTION OUTPUT ;
    USE SIGNAL ;
    PORT
      LAYER M4 ;
        RECT  17.196 56.784 17.28 56.808 ;
    END
  END captured[56]
  PIN captured[57]
    DIRECTION OUTPUT ;
    USE SIGNAL ;
    PORT
      LAYER M4 ;
        RECT  17.196 56.88 17.28 56.904 ;
    END
  END captured[57]
  PIN captured[58]
    DIRECTION OUTPUT ;
    USE SIGNAL ;
    PORT
      LAYER M4 ;
        RECT  17.196 56.976 17.28 57 ;
    END
  END captured[58]
  PIN captured[59]
    DIRECTION OUTPUT ;
    USE SIGNAL ;
    PORT
      LAYER M4 ;
        RECT  17.196 57.072 17.28 57.096 ;
    END
  END captured[59]
  PIN captured[5]
    DIRECTION OUTPUT ;
    USE SIGNAL ;
    PORT
      LAYER M4 ;
        RECT  17.196 42.672 17.28 42.696 ;
    END
  END captured[5]
  PIN captured[60]
    DIRECTION OUTPUT ;
    USE SIGNAL ;
    PORT
      LAYER M4 ;
        RECT  17.196 57.168 17.28 57.192 ;
    END
  END captured[60]
  PIN captured[61]
    DIRECTION OUTPUT ;
    USE SIGNAL ;
    PORT
      LAYER M4 ;
        RECT  17.196 57.264 17.28 57.288 ;
    END
  END captured[61]
  PIN captured[62]
    DIRECTION OUTPUT ;
    USE SIGNAL ;
    PORT
      LAYER M4 ;
        RECT  17.196 57.36 17.28 57.384 ;
    END
  END captured[62]
  PIN captured[63]
    DIRECTION OUTPUT ;
    USE SIGNAL ;
    PORT
      LAYER M4 ;
        RECT  17.196 57.456 17.28 57.48 ;
    END
  END captured[63]
  PIN captured[64]
    DIRECTION OUTPUT ;
    USE SIGNAL ;
    PORT
      LAYER M4 ;
        RECT  17.196 39.12 17.28 39.144 ;
    END
  END captured[64]
  PIN captured[65]
    DIRECTION OUTPUT ;
    USE SIGNAL ;
    PORT
      LAYER M4 ;
        RECT  17.196 39.216 17.28 39.24 ;
    END
  END captured[65]
  PIN captured[66]
    DIRECTION OUTPUT ;
    USE SIGNAL ;
    PORT
      LAYER M4 ;
        RECT  17.196 39.312 17.28 39.336 ;
    END
  END captured[66]
  PIN captured[67]
    DIRECTION OUTPUT ;
    USE SIGNAL ;
    PORT
      LAYER M4 ;
        RECT  17.196 39.408 17.28 39.432 ;
    END
  END captured[67]
  PIN captured[68]
    DIRECTION OUTPUT ;
    USE SIGNAL ;
    PORT
      LAYER M4 ;
        RECT  17.196 39.504 17.28 39.528 ;
    END
  END captured[68]
  PIN captured[69]
    DIRECTION OUTPUT ;
    USE SIGNAL ;
    PORT
      LAYER M4 ;
        RECT  17.196 39.6 17.28 39.624 ;
    END
  END captured[69]
  PIN captured[6]
    DIRECTION OUTPUT ;
    USE SIGNAL ;
    PORT
      LAYER M4 ;
        RECT  17.196 42.768 17.28 42.792 ;
    END
  END captured[6]
  PIN captured[70]
    DIRECTION OUTPUT ;
    USE SIGNAL ;
    PORT
      LAYER M4 ;
        RECT  17.196 39.696 17.28 39.72 ;
    END
  END captured[70]
  PIN captured[71]
    DIRECTION OUTPUT ;
    USE SIGNAL ;
    PORT
      LAYER M4 ;
        RECT  17.196 39.792 17.28 39.816 ;
    END
  END captured[71]
  PIN captured[72]
    DIRECTION OUTPUT ;
    USE SIGNAL ;
    PORT
      LAYER M4 ;
        RECT  17.196 39.888 17.28 39.912 ;
    END
  END captured[72]
  PIN captured[73]
    DIRECTION OUTPUT ;
    USE SIGNAL ;
    PORT
      LAYER M4 ;
        RECT  17.196 39.984 17.28 40.008 ;
    END
  END captured[73]
  PIN captured[74]
    DIRECTION OUTPUT ;
    USE SIGNAL ;
    PORT
      LAYER M4 ;
        RECT  17.196 40.08 17.28 40.104 ;
    END
  END captured[74]
  PIN captured[75]
    DIRECTION OUTPUT ;
    USE SIGNAL ;
    PORT
      LAYER M4 ;
        RECT  17.196 40.176 17.28 40.2 ;
    END
  END captured[75]
  PIN captured[76]
    DIRECTION OUTPUT ;
    USE SIGNAL ;
    PORT
      LAYER M4 ;
        RECT  17.196 40.272 17.28 40.296 ;
    END
  END captured[76]
  PIN captured[77]
    DIRECTION OUTPUT ;
    USE SIGNAL ;
    PORT
      LAYER M4 ;
        RECT  17.196 40.368 17.28 40.392 ;
    END
  END captured[77]
  PIN captured[78]
    DIRECTION OUTPUT ;
    USE SIGNAL ;
    PORT
      LAYER M4 ;
        RECT  17.196 40.464 17.28 40.488 ;
    END
  END captured[78]
  PIN captured[79]
    DIRECTION OUTPUT ;
    USE SIGNAL ;
    PORT
      LAYER M4 ;
        RECT  17.196 40.56 17.28 40.584 ;
    END
  END captured[79]
  PIN captured[7]
    DIRECTION OUTPUT ;
    USE SIGNAL ;
    PORT
      LAYER M4 ;
        RECT  17.196 42.864 17.28 42.888 ;
    END
  END captured[7]
  PIN captured[80]
    DIRECTION OUTPUT ;
    USE SIGNAL ;
    PORT
      LAYER M4 ;
        RECT  17.196 40.656 17.28 40.68 ;
    END
  END captured[80]
  PIN captured[81]
    DIRECTION OUTPUT ;
    USE SIGNAL ;
    PORT
      LAYER M4 ;
        RECT  17.196 40.752 17.28 40.776 ;
    END
  END captured[81]
  PIN captured[82]
    DIRECTION OUTPUT ;
    USE SIGNAL ;
    PORT
      LAYER M4 ;
        RECT  17.196 40.848 17.28 40.872 ;
    END
  END captured[82]
  PIN captured[83]
    DIRECTION OUTPUT ;
    USE SIGNAL ;
    PORT
      LAYER M4 ;
        RECT  17.196 40.944 17.28 40.968 ;
    END
  END captured[83]
  PIN captured[84]
    DIRECTION OUTPUT ;
    USE SIGNAL ;
    PORT
      LAYER M4 ;
        RECT  17.196 41.04 17.28 41.064 ;
    END
  END captured[84]
  PIN captured[85]
    DIRECTION OUTPUT ;
    USE SIGNAL ;
    PORT
      LAYER M4 ;
        RECT  17.196 41.136 17.28 41.16 ;
    END
  END captured[85]
  PIN captured[86]
    DIRECTION OUTPUT ;
    USE SIGNAL ;
    PORT
      LAYER M4 ;
        RECT  17.196 41.232 17.28 41.256 ;
    END
  END captured[86]
  PIN captured[87]
    DIRECTION OUTPUT ;
    USE SIGNAL ;
    PORT
      LAYER M4 ;
        RECT  17.196 41.328 17.28 41.352 ;
    END
  END captured[87]
  PIN captured[88]
    DIRECTION OUTPUT ;
    USE SIGNAL ;
    PORT
      LAYER M4 ;
        RECT  17.196 41.424 17.28 41.448 ;
    END
  END captured[88]
  PIN captured[89]
    DIRECTION OUTPUT ;
    USE SIGNAL ;
    PORT
      LAYER M4 ;
        RECT  17.196 41.52 17.28 41.544 ;
    END
  END captured[89]
  PIN captured[8]
    DIRECTION OUTPUT ;
    USE SIGNAL ;
    PORT
      LAYER M4 ;
        RECT  17.196 42.96 17.28 42.984 ;
    END
  END captured[8]
  PIN captured[90]
    DIRECTION OUTPUT ;
    USE SIGNAL ;
    PORT
      LAYER M4 ;
        RECT  17.196 41.616 17.28 41.64 ;
    END
  END captured[90]
  PIN captured[91]
    DIRECTION OUTPUT ;
    USE SIGNAL ;
    PORT
      LAYER M4 ;
        RECT  17.196 41.712 17.28 41.736 ;
    END
  END captured[91]
  PIN captured[92]
    DIRECTION OUTPUT ;
    USE SIGNAL ;
    PORT
      LAYER M4 ;
        RECT  17.196 41.808 17.28 41.832 ;
    END
  END captured[92]
  PIN captured[93]
    DIRECTION OUTPUT ;
    USE SIGNAL ;
    PORT
      LAYER M4 ;
        RECT  17.196 41.904 17.28 41.928 ;
    END
  END captured[93]
  PIN captured[94]
    DIRECTION OUTPUT ;
    USE SIGNAL ;
    PORT
      LAYER M4 ;
        RECT  17.196 42 17.28 42.024 ;
    END
  END captured[94]
  PIN captured[95]
    DIRECTION OUTPUT ;
    USE SIGNAL ;
    PORT
      LAYER M4 ;
        RECT  17.196 42.096 17.28 42.12 ;
    END
  END captured[95]
  PIN captured[96]
    DIRECTION OUTPUT ;
    USE SIGNAL ;
    PORT
      LAYER M4 ;
        RECT  17.196 51.408 17.28 51.432 ;
    END
  END captured[96]
  PIN captured[97]
    DIRECTION OUTPUT ;
    USE SIGNAL ;
    PORT
      LAYER M4 ;
        RECT  17.196 51.504 17.28 51.528 ;
    END
  END captured[97]
  PIN captured[98]
    DIRECTION OUTPUT ;
    USE SIGNAL ;
    PORT
      LAYER M4 ;
        RECT  17.196 51.6 17.28 51.624 ;
    END
  END captured[98]
  PIN captured[99]
    DIRECTION OUTPUT ;
    USE SIGNAL ;
    PORT
      LAYER M4 ;
        RECT  17.196 51.696 17.28 51.72 ;
    END
  END captured[99]
  PIN captured[9]
    DIRECTION OUTPUT ;
    USE SIGNAL ;
    PORT
      LAYER M4 ;
        RECT  17.196 43.056 17.28 43.08 ;
    END
  END captured[9]
  PIN captured_slot[0]
    DIRECTION OUTPUT ;
    USE SIGNAL ;
    PORT
      LAYER M4 ;
        RECT  17.196 38.448 17.28 38.472 ;
    END
  END captured_slot[0]
  PIN clk
    DIRECTION INPUT ;
    USE SIGNAL ;
    PORT
      LAYER M5 ;
        RECT  10.224 99.276 10.248 99.36 ;
    END
  END clk
  PIN fault
    DIRECTION OUTPUT ;
    USE SIGNAL ;
    PORT
      LAYER M5 ;
        RECT  10.32 99.276 10.344 99.36 ;
    END
  END fault
  PIN rst_n
    DIRECTION INPUT ;
    USE SIGNAL ;
    PORT
      LAYER M5 ;
        RECT  10.416 99.276 10.44 99.36 ;
    END
  END rst_n
  PIN src_d[0]
    DIRECTION INPUT ;
    USE SIGNAL ;
    PORT
      LAYER M4 ;
        RECT  0 41.904 0.084 41.928 ;
    END
  END src_d[0]
  PIN src_d[100]
    DIRECTION INPUT ;
    USE SIGNAL ;
    PORT
      LAYER M4 ;
        RECT  0 51.504 0.084 51.528 ;
    END
  END src_d[100]
  PIN src_d[101]
    DIRECTION INPUT ;
    USE SIGNAL ;
    PORT
      LAYER M4 ;
        RECT  0 51.6 0.084 51.624 ;
    END
  END src_d[101]
  PIN src_d[102]
    DIRECTION INPUT ;
    USE SIGNAL ;
    PORT
      LAYER M4 ;
        RECT  0 51.696 0.084 51.72 ;
    END
  END src_d[102]
  PIN src_d[103]
    DIRECTION INPUT ;
    USE SIGNAL ;
    PORT
      LAYER M4 ;
        RECT  0 51.792 0.084 51.816 ;
    END
  END src_d[103]
  PIN src_d[104]
    DIRECTION INPUT ;
    USE SIGNAL ;
    PORT
      LAYER M4 ;
        RECT  0 51.888 0.084 51.912 ;
    END
  END src_d[104]
  PIN src_d[105]
    DIRECTION INPUT ;
    USE SIGNAL ;
    PORT
      LAYER M4 ;
        RECT  0 51.984 0.084 52.008 ;
    END
  END src_d[105]
  PIN src_d[106]
    DIRECTION INPUT ;
    USE SIGNAL ;
    PORT
      LAYER M4 ;
        RECT  0 52.08 0.084 52.104 ;
    END
  END src_d[106]
  PIN src_d[107]
    DIRECTION INPUT ;
    USE SIGNAL ;
    PORT
      LAYER M4 ;
        RECT  0 52.176 0.084 52.2 ;
    END
  END src_d[107]
  PIN src_d[108]
    DIRECTION INPUT ;
    USE SIGNAL ;
    PORT
      LAYER M4 ;
        RECT  0 52.272 0.084 52.296 ;
    END
  END src_d[108]
  PIN src_d[109]
    DIRECTION INPUT ;
    USE SIGNAL ;
    PORT
      LAYER M4 ;
        RECT  0 52.368 0.084 52.392 ;
    END
  END src_d[109]
  PIN src_d[10]
    DIRECTION INPUT ;
    USE SIGNAL ;
    PORT
      LAYER M4 ;
        RECT  0 42.864 0.084 42.888 ;
    END
  END src_d[10]
  PIN src_d[110]
    DIRECTION INPUT ;
    USE SIGNAL ;
    PORT
      LAYER M4 ;
        RECT  0 52.464 0.084 52.488 ;
    END
  END src_d[110]
  PIN src_d[111]
    DIRECTION INPUT ;
    USE SIGNAL ;
    PORT
      LAYER M4 ;
        RECT  0 52.56 0.084 52.584 ;
    END
  END src_d[111]
  PIN src_d[112]
    DIRECTION INPUT ;
    USE SIGNAL ;
    PORT
      LAYER M4 ;
        RECT  0 52.656 0.084 52.68 ;
    END
  END src_d[112]
  PIN src_d[113]
    DIRECTION INPUT ;
    USE SIGNAL ;
    PORT
      LAYER M4 ;
        RECT  0 52.752 0.084 52.776 ;
    END
  END src_d[113]
  PIN src_d[114]
    DIRECTION INPUT ;
    USE SIGNAL ;
    PORT
      LAYER M4 ;
        RECT  0 52.848 0.084 52.872 ;
    END
  END src_d[114]
  PIN src_d[115]
    DIRECTION INPUT ;
    USE SIGNAL ;
    PORT
      LAYER M4 ;
        RECT  0 52.944 0.084 52.968 ;
    END
  END src_d[115]
  PIN src_d[116]
    DIRECTION INPUT ;
    USE SIGNAL ;
    PORT
      LAYER M4 ;
        RECT  0 53.04 0.084 53.064 ;
    END
  END src_d[116]
  PIN src_d[117]
    DIRECTION INPUT ;
    USE SIGNAL ;
    PORT
      LAYER M4 ;
        RECT  0 53.136 0.084 53.16 ;
    END
  END src_d[117]
  PIN src_d[118]
    DIRECTION INPUT ;
    USE SIGNAL ;
    PORT
      LAYER M4 ;
        RECT  0 53.232 0.084 53.256 ;
    END
  END src_d[118]
  PIN src_d[119]
    DIRECTION INPUT ;
    USE SIGNAL ;
    PORT
      LAYER M4 ;
        RECT  0 53.328 0.084 53.352 ;
    END
  END src_d[119]
  PIN src_d[11]
    DIRECTION INPUT ;
    USE SIGNAL ;
    PORT
      LAYER M4 ;
        RECT  0 42.96 0.084 42.984 ;
    END
  END src_d[11]
  PIN src_d[120]
    DIRECTION INPUT ;
    USE SIGNAL ;
    PORT
      LAYER M4 ;
        RECT  0 53.424 0.084 53.448 ;
    END
  END src_d[120]
  PIN src_d[121]
    DIRECTION INPUT ;
    USE SIGNAL ;
    PORT
      LAYER M4 ;
        RECT  0 53.52 0.084 53.544 ;
    END
  END src_d[121]
  PIN src_d[122]
    DIRECTION INPUT ;
    USE SIGNAL ;
    PORT
      LAYER M4 ;
        RECT  0 53.616 0.084 53.64 ;
    END
  END src_d[122]
  PIN src_d[123]
    DIRECTION INPUT ;
    USE SIGNAL ;
    PORT
      LAYER M4 ;
        RECT  0 53.712 0.084 53.736 ;
    END
  END src_d[123]
  PIN src_d[124]
    DIRECTION INPUT ;
    USE SIGNAL ;
    PORT
      LAYER M4 ;
        RECT  0 53.808 0.084 53.832 ;
    END
  END src_d[124]
  PIN src_d[125]
    DIRECTION INPUT ;
    USE SIGNAL ;
    PORT
      LAYER M4 ;
        RECT  0 53.904 0.084 53.928 ;
    END
  END src_d[125]
  PIN src_d[126]
    DIRECTION INPUT ;
    USE SIGNAL ;
    PORT
      LAYER M4 ;
        RECT  0 54 0.084 54.024 ;
    END
  END src_d[126]
  PIN src_d[127]
    DIRECTION INPUT ;
    USE SIGNAL ;
    PORT
      LAYER M4 ;
        RECT  0 57.168 0.084 57.192 ;
    END
  END src_d[127]
  PIN src_d[128]
    DIRECTION INPUT ;
    USE SIGNAL ;
    PORT
      LAYER M4 ;
        RECT  0 57.264 0.084 57.288 ;
    END
  END src_d[128]
  PIN src_d[129]
    DIRECTION INPUT ;
    USE SIGNAL ;
    PORT
      LAYER M4 ;
        RECT  0 57.36 0.084 57.384 ;
    END
  END src_d[129]
  PIN src_d[12]
    DIRECTION INPUT ;
    USE SIGNAL ;
    PORT
      LAYER M4 ;
        RECT  0 43.056 0.084 43.08 ;
    END
  END src_d[12]
  PIN src_d[130]
    DIRECTION INPUT ;
    USE SIGNAL ;
    PORT
      LAYER M4 ;
        RECT  0 57.456 0.084 57.48 ;
    END
  END src_d[130]
  PIN src_d[131]
    DIRECTION INPUT ;
    USE SIGNAL ;
    PORT
      LAYER M4 ;
        RECT  0 57.552 0.084 57.576 ;
    END
  END src_d[131]
  PIN src_d[132]
    DIRECTION INPUT ;
    USE SIGNAL ;
    PORT
      LAYER M4 ;
        RECT  0 57.648 0.084 57.672 ;
    END
  END src_d[132]
  PIN src_d[133]
    DIRECTION INPUT ;
    USE SIGNAL ;
    PORT
      LAYER M4 ;
        RECT  0 57.744 0.084 57.768 ;
    END
  END src_d[133]
  PIN src_d[134]
    DIRECTION INPUT ;
    USE SIGNAL ;
    PORT
      LAYER M4 ;
        RECT  0 57.84 0.084 57.864 ;
    END
  END src_d[134]
  PIN src_d[135]
    DIRECTION INPUT ;
    USE SIGNAL ;
    PORT
      LAYER M4 ;
        RECT  0 57.936 0.084 57.96 ;
    END
  END src_d[135]
  PIN src_d[136]
    DIRECTION INPUT ;
    USE SIGNAL ;
    PORT
      LAYER M4 ;
        RECT  0 58.032 0.084 58.056 ;
    END
  END src_d[136]
  PIN src_d[137]
    DIRECTION INPUT ;
    USE SIGNAL ;
    PORT
      LAYER M4 ;
        RECT  0 58.128 0.084 58.152 ;
    END
  END src_d[137]
  PIN src_d[138]
    DIRECTION INPUT ;
    USE SIGNAL ;
    PORT
      LAYER M4 ;
        RECT  0 58.224 0.084 58.248 ;
    END
  END src_d[138]
  PIN src_d[139]
    DIRECTION INPUT ;
    USE SIGNAL ;
    PORT
      LAYER M4 ;
        RECT  0 58.32 0.084 58.344 ;
    END
  END src_d[139]
  PIN src_d[13]
    DIRECTION INPUT ;
    USE SIGNAL ;
    PORT
      LAYER M4 ;
        RECT  0 43.152 0.084 43.176 ;
    END
  END src_d[13]
  PIN src_d[140]
    DIRECTION INPUT ;
    USE SIGNAL ;
    PORT
      LAYER M4 ;
        RECT  0 58.416 0.084 58.44 ;
    END
  END src_d[140]
  PIN src_d[141]
    DIRECTION INPUT ;
    USE SIGNAL ;
    PORT
      LAYER M4 ;
        RECT  0 58.512 0.084 58.536 ;
    END
  END src_d[141]
  PIN src_d[142]
    DIRECTION INPUT ;
    USE SIGNAL ;
    PORT
      LAYER M4 ;
        RECT  0 58.608 0.084 58.632 ;
    END
  END src_d[142]
  PIN src_d[143]
    DIRECTION INPUT ;
    USE SIGNAL ;
    PORT
      LAYER M4 ;
        RECT  0 58.704 0.084 58.728 ;
    END
  END src_d[143]
  PIN src_d[144]
    DIRECTION INPUT ;
    USE SIGNAL ;
    PORT
      LAYER M4 ;
        RECT  0 58.8 0.084 58.824 ;
    END
  END src_d[144]
  PIN src_d[145]
    DIRECTION INPUT ;
    USE SIGNAL ;
    PORT
      LAYER M4 ;
        RECT  0 58.896 0.084 58.92 ;
    END
  END src_d[145]
  PIN src_d[146]
    DIRECTION INPUT ;
    USE SIGNAL ;
    PORT
      LAYER M4 ;
        RECT  0 58.992 0.084 59.016 ;
    END
  END src_d[146]
  PIN src_d[147]
    DIRECTION INPUT ;
    USE SIGNAL ;
    PORT
      LAYER M4 ;
        RECT  0 59.088 0.084 59.112 ;
    END
  END src_d[147]
  PIN src_d[148]
    DIRECTION INPUT ;
    USE SIGNAL ;
    PORT
      LAYER M4 ;
        RECT  0 59.184 0.084 59.208 ;
    END
  END src_d[148]
  PIN src_d[149]
    DIRECTION INPUT ;
    USE SIGNAL ;
    PORT
      LAYER M4 ;
        RECT  0 59.28 0.084 59.304 ;
    END
  END src_d[149]
  PIN src_d[14]
    DIRECTION INPUT ;
    USE SIGNAL ;
    PORT
      LAYER M4 ;
        RECT  0 43.248 0.084 43.272 ;
    END
  END src_d[14]
  PIN src_d[150]
    DIRECTION INPUT ;
    USE SIGNAL ;
    PORT
      LAYER M4 ;
        RECT  0 59.376 0.084 59.4 ;
    END
  END src_d[150]
  PIN src_d[151]
    DIRECTION INPUT ;
    USE SIGNAL ;
    PORT
      LAYER M4 ;
        RECT  0 59.472 0.084 59.496 ;
    END
  END src_d[151]
  PIN src_d[152]
    DIRECTION INPUT ;
    USE SIGNAL ;
    PORT
      LAYER M4 ;
        RECT  0 59.568 0.084 59.592 ;
    END
  END src_d[152]
  PIN src_d[153]
    DIRECTION INPUT ;
    USE SIGNAL ;
    PORT
      LAYER M4 ;
        RECT  0 59.664 0.084 59.688 ;
    END
  END src_d[153]
  PIN src_d[154]
    DIRECTION INPUT ;
    USE SIGNAL ;
    PORT
      LAYER M4 ;
        RECT  0 59.76 0.084 59.784 ;
    END
  END src_d[154]
  PIN src_d[155]
    DIRECTION INPUT ;
    USE SIGNAL ;
    PORT
      LAYER M4 ;
        RECT  0 59.856 0.084 59.88 ;
    END
  END src_d[155]
  PIN src_d[156]
    DIRECTION INPUT ;
    USE SIGNAL ;
    PORT
      LAYER M4 ;
        RECT  0 59.952 0.084 59.976 ;
    END
  END src_d[156]
  PIN src_d[157]
    DIRECTION INPUT ;
    USE SIGNAL ;
    PORT
      LAYER M4 ;
        RECT  0 60.048 0.084 60.072 ;
    END
  END src_d[157]
  PIN src_d[158]
    DIRECTION INPUT ;
    USE SIGNAL ;
    PORT
      LAYER M4 ;
        RECT  0 60.144 0.084 60.168 ;
    END
  END src_d[158]
  PIN src_d[159]
    DIRECTION INPUT ;
    USE SIGNAL ;
    PORT
      LAYER M4 ;
        RECT  0 44.88 0.084 44.904 ;
    END
  END src_d[159]
  PIN src_d[15]
    DIRECTION INPUT ;
    USE SIGNAL ;
    PORT
      LAYER M4 ;
        RECT  0 43.344 0.084 43.368 ;
    END
  END src_d[15]
  PIN src_d[160]
    DIRECTION INPUT ;
    USE SIGNAL ;
    PORT
      LAYER M4 ;
        RECT  0 44.976 0.084 45 ;
    END
  END src_d[160]
  PIN src_d[161]
    DIRECTION INPUT ;
    USE SIGNAL ;
    PORT
      LAYER M4 ;
        RECT  0 45.072 0.084 45.096 ;
    END
  END src_d[161]
  PIN src_d[162]
    DIRECTION INPUT ;
    USE SIGNAL ;
    PORT
      LAYER M4 ;
        RECT  0 45.168 0.084 45.192 ;
    END
  END src_d[162]
  PIN src_d[163]
    DIRECTION INPUT ;
    USE SIGNAL ;
    PORT
      LAYER M4 ;
        RECT  0 45.264 0.084 45.288 ;
    END
  END src_d[163]
  PIN src_d[164]
    DIRECTION INPUT ;
    USE SIGNAL ;
    PORT
      LAYER M4 ;
        RECT  0 45.36 0.084 45.384 ;
    END
  END src_d[164]
  PIN src_d[165]
    DIRECTION INPUT ;
    USE SIGNAL ;
    PORT
      LAYER M4 ;
        RECT  0 45.456 0.084 45.48 ;
    END
  END src_d[165]
  PIN src_d[166]
    DIRECTION INPUT ;
    USE SIGNAL ;
    PORT
      LAYER M4 ;
        RECT  0 45.552 0.084 45.576 ;
    END
  END src_d[166]
  PIN src_d[167]
    DIRECTION INPUT ;
    USE SIGNAL ;
    PORT
      LAYER M4 ;
        RECT  0 45.648 0.084 45.672 ;
    END
  END src_d[167]
  PIN src_d[168]
    DIRECTION INPUT ;
    USE SIGNAL ;
    PORT
      LAYER M4 ;
        RECT  0 45.744 0.084 45.768 ;
    END
  END src_d[168]
  PIN src_d[169]
    DIRECTION INPUT ;
    USE SIGNAL ;
    PORT
      LAYER M4 ;
        RECT  0 45.84 0.084 45.864 ;
    END
  END src_d[169]
  PIN src_d[16]
    DIRECTION INPUT ;
    USE SIGNAL ;
    PORT
      LAYER M4 ;
        RECT  0 43.44 0.084 43.464 ;
    END
  END src_d[16]
  PIN src_d[170]
    DIRECTION INPUT ;
    USE SIGNAL ;
    PORT
      LAYER M4 ;
        RECT  0 45.936 0.084 45.96 ;
    END
  END src_d[170]
  PIN src_d[171]
    DIRECTION INPUT ;
    USE SIGNAL ;
    PORT
      LAYER M4 ;
        RECT  0 46.032 0.084 46.056 ;
    END
  END src_d[171]
  PIN src_d[172]
    DIRECTION INPUT ;
    USE SIGNAL ;
    PORT
      LAYER M4 ;
        RECT  0 46.128 0.084 46.152 ;
    END
  END src_d[172]
  PIN src_d[173]
    DIRECTION INPUT ;
    USE SIGNAL ;
    PORT
      LAYER M4 ;
        RECT  0 46.224 0.084 46.248 ;
    END
  END src_d[173]
  PIN src_d[174]
    DIRECTION INPUT ;
    USE SIGNAL ;
    PORT
      LAYER M4 ;
        RECT  0 46.32 0.084 46.344 ;
    END
  END src_d[174]
  PIN src_d[175]
    DIRECTION INPUT ;
    USE SIGNAL ;
    PORT
      LAYER M4 ;
        RECT  0 46.416 0.084 46.44 ;
    END
  END src_d[175]
  PIN src_d[176]
    DIRECTION INPUT ;
    USE SIGNAL ;
    PORT
      LAYER M4 ;
        RECT  0 46.512 0.084 46.536 ;
    END
  END src_d[176]
  PIN src_d[177]
    DIRECTION INPUT ;
    USE SIGNAL ;
    PORT
      LAYER M4 ;
        RECT  0 46.608 0.084 46.632 ;
    END
  END src_d[177]
  PIN src_d[178]
    DIRECTION INPUT ;
    USE SIGNAL ;
    PORT
      LAYER M4 ;
        RECT  0 46.704 0.084 46.728 ;
    END
  END src_d[178]
  PIN src_d[179]
    DIRECTION INPUT ;
    USE SIGNAL ;
    PORT
      LAYER M4 ;
        RECT  0 46.8 0.084 46.824 ;
    END
  END src_d[179]
  PIN src_d[17]
    DIRECTION INPUT ;
    USE SIGNAL ;
    PORT
      LAYER M4 ;
        RECT  0 43.536 0.084 43.56 ;
    END
  END src_d[17]
  PIN src_d[180]
    DIRECTION INPUT ;
    USE SIGNAL ;
    PORT
      LAYER M4 ;
        RECT  0 46.896 0.084 46.92 ;
    END
  END src_d[180]
  PIN src_d[181]
    DIRECTION INPUT ;
    USE SIGNAL ;
    PORT
      LAYER M4 ;
        RECT  0 46.992 0.084 47.016 ;
    END
  END src_d[181]
  PIN src_d[182]
    DIRECTION INPUT ;
    USE SIGNAL ;
    PORT
      LAYER M4 ;
        RECT  0 47.088 0.084 47.112 ;
    END
  END src_d[182]
  PIN src_d[183]
    DIRECTION INPUT ;
    USE SIGNAL ;
    PORT
      LAYER M4 ;
        RECT  0 47.184 0.084 47.208 ;
    END
  END src_d[183]
  PIN src_d[184]
    DIRECTION INPUT ;
    USE SIGNAL ;
    PORT
      LAYER M4 ;
        RECT  0 47.28 0.084 47.304 ;
    END
  END src_d[184]
  PIN src_d[185]
    DIRECTION INPUT ;
    USE SIGNAL ;
    PORT
      LAYER M4 ;
        RECT  0 47.376 0.084 47.4 ;
    END
  END src_d[185]
  PIN src_d[186]
    DIRECTION INPUT ;
    USE SIGNAL ;
    PORT
      LAYER M4 ;
        RECT  0 47.472 0.084 47.496 ;
    END
  END src_d[186]
  PIN src_d[187]
    DIRECTION INPUT ;
    USE SIGNAL ;
    PORT
      LAYER M4 ;
        RECT  0 47.568 0.084 47.592 ;
    END
  END src_d[187]
  PIN src_d[188]
    DIRECTION INPUT ;
    USE SIGNAL ;
    PORT
      LAYER M4 ;
        RECT  0 47.664 0.084 47.688 ;
    END
  END src_d[188]
  PIN src_d[189]
    DIRECTION INPUT ;
    USE SIGNAL ;
    PORT
      LAYER M4 ;
        RECT  0 47.76 0.084 47.784 ;
    END
  END src_d[189]
  PIN src_d[18]
    DIRECTION INPUT ;
    USE SIGNAL ;
    PORT
      LAYER M4 ;
        RECT  0 43.632 0.084 43.656 ;
    END
  END src_d[18]
  PIN src_d[190]
    DIRECTION INPUT ;
    USE SIGNAL ;
    PORT
      LAYER M4 ;
        RECT  0 47.856 0.084 47.88 ;
    END
  END src_d[190]
  PIN src_d[191]
    DIRECTION INPUT ;
    USE SIGNAL ;
    PORT
      LAYER M4 ;
        RECT  0 22.608 0.084 22.632 ;
    END
  END src_d[191]
  PIN src_d[192]
    DIRECTION INPUT ;
    USE SIGNAL ;
    PORT
      LAYER M4 ;
        RECT  0 22.704 0.084 22.728 ;
    END
  END src_d[192]
  PIN src_d[193]
    DIRECTION INPUT ;
    USE SIGNAL ;
    PORT
      LAYER M4 ;
        RECT  0 22.8 0.084 22.824 ;
    END
  END src_d[193]
  PIN src_d[194]
    DIRECTION INPUT ;
    USE SIGNAL ;
    PORT
      LAYER M4 ;
        RECT  0 22.896 0.084 22.92 ;
    END
  END src_d[194]
  PIN src_d[195]
    DIRECTION INPUT ;
    USE SIGNAL ;
    PORT
      LAYER M4 ;
        RECT  0 22.992 0.084 23.016 ;
    END
  END src_d[195]
  PIN src_d[196]
    DIRECTION INPUT ;
    USE SIGNAL ;
    PORT
      LAYER M4 ;
        RECT  0 23.088 0.084 23.112 ;
    END
  END src_d[196]
  PIN src_d[197]
    DIRECTION INPUT ;
    USE SIGNAL ;
    PORT
      LAYER M4 ;
        RECT  0 23.184 0.084 23.208 ;
    END
  END src_d[197]
  PIN src_d[198]
    DIRECTION INPUT ;
    USE SIGNAL ;
    PORT
      LAYER M4 ;
        RECT  0 23.28 0.084 23.304 ;
    END
  END src_d[198]
  PIN src_d[199]
    DIRECTION INPUT ;
    USE SIGNAL ;
    PORT
      LAYER M4 ;
        RECT  0 23.376 0.084 23.4 ;
    END
  END src_d[199]
  PIN src_d[19]
    DIRECTION INPUT ;
    USE SIGNAL ;
    PORT
      LAYER M4 ;
        RECT  0 43.728 0.084 43.752 ;
    END
  END src_d[19]
  PIN src_d[1]
    DIRECTION INPUT ;
    USE SIGNAL ;
    PORT
      LAYER M4 ;
        RECT  0 42 0.084 42.024 ;
    END
  END src_d[1]
  PIN src_d[200]
    DIRECTION INPUT ;
    USE SIGNAL ;
    PORT
      LAYER M4 ;
        RECT  0 23.472 0.084 23.496 ;
    END
  END src_d[200]
  PIN src_d[201]
    DIRECTION INPUT ;
    USE SIGNAL ;
    PORT
      LAYER M4 ;
        RECT  0 23.568 0.084 23.592 ;
    END
  END src_d[201]
  PIN src_d[202]
    DIRECTION INPUT ;
    USE SIGNAL ;
    PORT
      LAYER M4 ;
        RECT  0 23.664 0.084 23.688 ;
    END
  END src_d[202]
  PIN src_d[203]
    DIRECTION INPUT ;
    USE SIGNAL ;
    PORT
      LAYER M4 ;
        RECT  0 23.76 0.084 23.784 ;
    END
  END src_d[203]
  PIN src_d[204]
    DIRECTION INPUT ;
    USE SIGNAL ;
    PORT
      LAYER M4 ;
        RECT  0 23.856 0.084 23.88 ;
    END
  END src_d[204]
  PIN src_d[205]
    DIRECTION INPUT ;
    USE SIGNAL ;
    PORT
      LAYER M4 ;
        RECT  0 23.952 0.084 23.976 ;
    END
  END src_d[205]
  PIN src_d[206]
    DIRECTION INPUT ;
    USE SIGNAL ;
    PORT
      LAYER M4 ;
        RECT  0 24.048 0.084 24.072 ;
    END
  END src_d[206]
  PIN src_d[207]
    DIRECTION INPUT ;
    USE SIGNAL ;
    PORT
      LAYER M4 ;
        RECT  0 24.144 0.084 24.168 ;
    END
  END src_d[207]
  PIN src_d[208]
    DIRECTION INPUT ;
    USE SIGNAL ;
    PORT
      LAYER M4 ;
        RECT  0 24.24 0.084 24.264 ;
    END
  END src_d[208]
  PIN src_d[209]
    DIRECTION INPUT ;
    USE SIGNAL ;
    PORT
      LAYER M4 ;
        RECT  0 24.336 0.084 24.36 ;
    END
  END src_d[209]
  PIN src_d[20]
    DIRECTION INPUT ;
    USE SIGNAL ;
    PORT
      LAYER M4 ;
        RECT  0 43.824 0.084 43.848 ;
    END
  END src_d[20]
  PIN src_d[210]
    DIRECTION INPUT ;
    USE SIGNAL ;
    PORT
      LAYER M4 ;
        RECT  0 24.432 0.084 24.456 ;
    END
  END src_d[210]
  PIN src_d[211]
    DIRECTION INPUT ;
    USE SIGNAL ;
    PORT
      LAYER M4 ;
        RECT  0 24.528 0.084 24.552 ;
    END
  END src_d[211]
  PIN src_d[212]
    DIRECTION INPUT ;
    USE SIGNAL ;
    PORT
      LAYER M4 ;
        RECT  0 24.624 0.084 24.648 ;
    END
  END src_d[212]
  PIN src_d[213]
    DIRECTION INPUT ;
    USE SIGNAL ;
    PORT
      LAYER M4 ;
        RECT  0 24.72 0.084 24.744 ;
    END
  END src_d[213]
  PIN src_d[214]
    DIRECTION INPUT ;
    USE SIGNAL ;
    PORT
      LAYER M4 ;
        RECT  0 24.816 0.084 24.84 ;
    END
  END src_d[214]
  PIN src_d[215]
    DIRECTION INPUT ;
    USE SIGNAL ;
    PORT
      LAYER M4 ;
        RECT  0 24.912 0.084 24.936 ;
    END
  END src_d[215]
  PIN src_d[216]
    DIRECTION INPUT ;
    USE SIGNAL ;
    PORT
      LAYER M4 ;
        RECT  0 25.008 0.084 25.032 ;
    END
  END src_d[216]
  PIN src_d[217]
    DIRECTION INPUT ;
    USE SIGNAL ;
    PORT
      LAYER M4 ;
        RECT  0 25.104 0.084 25.128 ;
    END
  END src_d[217]
  PIN src_d[218]
    DIRECTION INPUT ;
    USE SIGNAL ;
    PORT
      LAYER M4 ;
        RECT  0 25.2 0.084 25.224 ;
    END
  END src_d[218]
  PIN src_d[219]
    DIRECTION INPUT ;
    USE SIGNAL ;
    PORT
      LAYER M4 ;
        RECT  0 25.296 0.084 25.32 ;
    END
  END src_d[219]
  PIN src_d[21]
    DIRECTION INPUT ;
    USE SIGNAL ;
    PORT
      LAYER M4 ;
        RECT  0 43.92 0.084 43.944 ;
    END
  END src_d[21]
  PIN src_d[220]
    DIRECTION INPUT ;
    USE SIGNAL ;
    PORT
      LAYER M4 ;
        RECT  0 25.392 0.084 25.416 ;
    END
  END src_d[220]
  PIN src_d[221]
    DIRECTION INPUT ;
    USE SIGNAL ;
    PORT
      LAYER M4 ;
        RECT  0 25.488 0.084 25.512 ;
    END
  END src_d[221]
  PIN src_d[222]
    DIRECTION INPUT ;
    USE SIGNAL ;
    PORT
      LAYER M4 ;
        RECT  0 25.584 0.084 25.608 ;
    END
  END src_d[222]
  PIN src_d[223]
    DIRECTION INPUT ;
    USE SIGNAL ;
    PORT
      LAYER M4 ;
        RECT  0 25.68 0.084 25.704 ;
    END
  END src_d[223]
  PIN src_d[224]
    DIRECTION INPUT ;
    USE SIGNAL ;
    PORT
      LAYER M4 ;
        RECT  0 25.776 0.084 25.8 ;
    END
  END src_d[224]
  PIN src_d[225]
    DIRECTION INPUT ;
    USE SIGNAL ;
    PORT
      LAYER M4 ;
        RECT  0 25.872 0.084 25.896 ;
    END
  END src_d[225]
  PIN src_d[226]
    DIRECTION INPUT ;
    USE SIGNAL ;
    PORT
      LAYER M4 ;
        RECT  0 25.968 0.084 25.992 ;
    END
  END src_d[226]
  PIN src_d[227]
    DIRECTION INPUT ;
    USE SIGNAL ;
    PORT
      LAYER M4 ;
        RECT  0 26.064 0.084 26.088 ;
    END
  END src_d[227]
  PIN src_d[228]
    DIRECTION INPUT ;
    USE SIGNAL ;
    PORT
      LAYER M4 ;
        RECT  0 26.16 0.084 26.184 ;
    END
  END src_d[228]
  PIN src_d[229]
    DIRECTION INPUT ;
    USE SIGNAL ;
    PORT
      LAYER M4 ;
        RECT  0 26.256 0.084 26.28 ;
    END
  END src_d[229]
  PIN src_d[22]
    DIRECTION INPUT ;
    USE SIGNAL ;
    PORT
      LAYER M4 ;
        RECT  0 44.016 0.084 44.04 ;
    END
  END src_d[22]
  PIN src_d[230]
    DIRECTION INPUT ;
    USE SIGNAL ;
    PORT
      LAYER M4 ;
        RECT  0 26.352 0.084 26.376 ;
    END
  END src_d[230]
  PIN src_d[231]
    DIRECTION INPUT ;
    USE SIGNAL ;
    PORT
      LAYER M4 ;
        RECT  0 26.448 0.084 26.472 ;
    END
  END src_d[231]
  PIN src_d[232]
    DIRECTION INPUT ;
    USE SIGNAL ;
    PORT
      LAYER M4 ;
        RECT  0 26.544 0.084 26.568 ;
    END
  END src_d[232]
  PIN src_d[233]
    DIRECTION INPUT ;
    USE SIGNAL ;
    PORT
      LAYER M4 ;
        RECT  0 26.64 0.084 26.664 ;
    END
  END src_d[233]
  PIN src_d[234]
    DIRECTION INPUT ;
    USE SIGNAL ;
    PORT
      LAYER M4 ;
        RECT  0 26.736 0.084 26.76 ;
    END
  END src_d[234]
  PIN src_d[235]
    DIRECTION INPUT ;
    USE SIGNAL ;
    PORT
      LAYER M4 ;
        RECT  0 26.832 0.084 26.856 ;
    END
  END src_d[235]
  PIN src_d[236]
    DIRECTION INPUT ;
    USE SIGNAL ;
    PORT
      LAYER M4 ;
        RECT  0 26.928 0.084 26.952 ;
    END
  END src_d[236]
  PIN src_d[237]
    DIRECTION INPUT ;
    USE SIGNAL ;
    PORT
      LAYER M4 ;
        RECT  0 27.024 0.084 27.048 ;
    END
  END src_d[237]
  PIN src_d[238]
    DIRECTION INPUT ;
    USE SIGNAL ;
    PORT
      LAYER M4 ;
        RECT  0 27.12 0.084 27.144 ;
    END
  END src_d[238]
  PIN src_d[239]
    DIRECTION INPUT ;
    USE SIGNAL ;
    PORT
      LAYER M4 ;
        RECT  0 27.216 0.084 27.24 ;
    END
  END src_d[239]
  PIN src_d[23]
    DIRECTION INPUT ;
    USE SIGNAL ;
    PORT
      LAYER M4 ;
        RECT  0 44.112 0.084 44.136 ;
    END
  END src_d[23]
  PIN src_d[240]
    DIRECTION INPUT ;
    USE SIGNAL ;
    PORT
      LAYER M4 ;
        RECT  0 27.312 0.084 27.336 ;
    END
  END src_d[240]
  PIN src_d[241]
    DIRECTION INPUT ;
    USE SIGNAL ;
    PORT
      LAYER M4 ;
        RECT  0 27.408 0.084 27.432 ;
    END
  END src_d[241]
  PIN src_d[242]
    DIRECTION INPUT ;
    USE SIGNAL ;
    PORT
      LAYER M4 ;
        RECT  0 27.504 0.084 27.528 ;
    END
  END src_d[242]
  PIN src_d[243]
    DIRECTION INPUT ;
    USE SIGNAL ;
    PORT
      LAYER M4 ;
        RECT  0 27.6 0.084 27.624 ;
    END
  END src_d[243]
  PIN src_d[244]
    DIRECTION INPUT ;
    USE SIGNAL ;
    PORT
      LAYER M4 ;
        RECT  0 27.696 0.084 27.72 ;
    END
  END src_d[244]
  PIN src_d[245]
    DIRECTION INPUT ;
    USE SIGNAL ;
    PORT
      LAYER M4 ;
        RECT  0 27.792 0.084 27.816 ;
    END
  END src_d[245]
  PIN src_d[246]
    DIRECTION INPUT ;
    USE SIGNAL ;
    PORT
      LAYER M4 ;
        RECT  0 27.888 0.084 27.912 ;
    END
  END src_d[246]
  PIN src_d[247]
    DIRECTION INPUT ;
    USE SIGNAL ;
    PORT
      LAYER M4 ;
        RECT  0 27.984 0.084 28.008 ;
    END
  END src_d[247]
  PIN src_d[248]
    DIRECTION INPUT ;
    USE SIGNAL ;
    PORT
      LAYER M4 ;
        RECT  0 28.08 0.084 28.104 ;
    END
  END src_d[248]
  PIN src_d[249]
    DIRECTION INPUT ;
    USE SIGNAL ;
    PORT
      LAYER M4 ;
        RECT  0 28.176 0.084 28.2 ;
    END
  END src_d[249]
  PIN src_d[24]
    DIRECTION INPUT ;
    USE SIGNAL ;
    PORT
      LAYER M4 ;
        RECT  0 44.208 0.084 44.232 ;
    END
  END src_d[24]
  PIN src_d[250]
    DIRECTION INPUT ;
    USE SIGNAL ;
    PORT
      LAYER M4 ;
        RECT  0 28.272 0.084 28.296 ;
    END
  END src_d[250]
  PIN src_d[251]
    DIRECTION INPUT ;
    USE SIGNAL ;
    PORT
      LAYER M4 ;
        RECT  0 28.368 0.084 28.392 ;
    END
  END src_d[251]
  PIN src_d[252]
    DIRECTION INPUT ;
    USE SIGNAL ;
    PORT
      LAYER M4 ;
        RECT  0 28.464 0.084 28.488 ;
    END
  END src_d[252]
  PIN src_d[253]
    DIRECTION INPUT ;
    USE SIGNAL ;
    PORT
      LAYER M4 ;
        RECT  0 28.56 0.084 28.584 ;
    END
  END src_d[253]
  PIN src_d[254]
    DIRECTION INPUT ;
    USE SIGNAL ;
    PORT
      LAYER M4 ;
        RECT  0 28.656 0.084 28.68 ;
    END
  END src_d[254]
  PIN src_d[255]
    DIRECTION INPUT ;
    USE SIGNAL ;
    PORT
      LAYER M4 ;
        RECT  0 37.968 0.084 37.992 ;
    END
  END src_d[255]
  PIN src_d[256]
    DIRECTION INPUT ;
    USE SIGNAL ;
    PORT
      LAYER M4 ;
        RECT  0 38.064 0.084 38.088 ;
    END
  END src_d[256]
  PIN src_d[257]
    DIRECTION INPUT ;
    USE SIGNAL ;
    PORT
      LAYER M4 ;
        RECT  0 38.16 0.084 38.184 ;
    END
  END src_d[257]
  PIN src_d[258]
    DIRECTION INPUT ;
    USE SIGNAL ;
    PORT
      LAYER M4 ;
        RECT  0 38.256 0.084 38.28 ;
    END
  END src_d[258]
  PIN src_d[259]
    DIRECTION INPUT ;
    USE SIGNAL ;
    PORT
      LAYER M4 ;
        RECT  0 38.352 0.084 38.376 ;
    END
  END src_d[259]
  PIN src_d[25]
    DIRECTION INPUT ;
    USE SIGNAL ;
    PORT
      LAYER M4 ;
        RECT  0 44.304 0.084 44.328 ;
    END
  END src_d[25]
  PIN src_d[260]
    DIRECTION INPUT ;
    USE SIGNAL ;
    PORT
      LAYER M4 ;
        RECT  0 38.448 0.084 38.472 ;
    END
  END src_d[260]
  PIN src_d[261]
    DIRECTION INPUT ;
    USE SIGNAL ;
    PORT
      LAYER M4 ;
        RECT  0 38.544 0.084 38.568 ;
    END
  END src_d[261]
  PIN src_d[262]
    DIRECTION INPUT ;
    USE SIGNAL ;
    PORT
      LAYER M4 ;
        RECT  0 38.64 0.084 38.664 ;
    END
  END src_d[262]
  PIN src_d[263]
    DIRECTION INPUT ;
    USE SIGNAL ;
    PORT
      LAYER M4 ;
        RECT  0 38.736 0.084 38.76 ;
    END
  END src_d[263]
  PIN src_d[264]
    DIRECTION INPUT ;
    USE SIGNAL ;
    PORT
      LAYER M4 ;
        RECT  0 38.832 0.084 38.856 ;
    END
  END src_d[264]
  PIN src_d[265]
    DIRECTION INPUT ;
    USE SIGNAL ;
    PORT
      LAYER M4 ;
        RECT  0 38.928 0.084 38.952 ;
    END
  END src_d[265]
  PIN src_d[266]
    DIRECTION INPUT ;
    USE SIGNAL ;
    PORT
      LAYER M4 ;
        RECT  0 39.024 0.084 39.048 ;
    END
  END src_d[266]
  PIN src_d[267]
    DIRECTION INPUT ;
    USE SIGNAL ;
    PORT
      LAYER M4 ;
        RECT  0 39.12 0.084 39.144 ;
    END
  END src_d[267]
  PIN src_d[268]
    DIRECTION INPUT ;
    USE SIGNAL ;
    PORT
      LAYER M4 ;
        RECT  0 39.216 0.084 39.24 ;
    END
  END src_d[268]
  PIN src_d[269]
    DIRECTION INPUT ;
    USE SIGNAL ;
    PORT
      LAYER M4 ;
        RECT  0 39.312 0.084 39.336 ;
    END
  END src_d[269]
  PIN src_d[26]
    DIRECTION INPUT ;
    USE SIGNAL ;
    PORT
      LAYER M4 ;
        RECT  0 44.4 0.084 44.424 ;
    END
  END src_d[26]
  PIN src_d[270]
    DIRECTION INPUT ;
    USE SIGNAL ;
    PORT
      LAYER M4 ;
        RECT  0 39.408 0.084 39.432 ;
    END
  END src_d[270]
  PIN src_d[271]
    DIRECTION INPUT ;
    USE SIGNAL ;
    PORT
      LAYER M4 ;
        RECT  0 39.504 0.084 39.528 ;
    END
  END src_d[271]
  PIN src_d[272]
    DIRECTION INPUT ;
    USE SIGNAL ;
    PORT
      LAYER M4 ;
        RECT  0 39.6 0.084 39.624 ;
    END
  END src_d[272]
  PIN src_d[273]
    DIRECTION INPUT ;
    USE SIGNAL ;
    PORT
      LAYER M4 ;
        RECT  0 39.696 0.084 39.72 ;
    END
  END src_d[273]
  PIN src_d[274]
    DIRECTION INPUT ;
    USE SIGNAL ;
    PORT
      LAYER M4 ;
        RECT  0 39.792 0.084 39.816 ;
    END
  END src_d[274]
  PIN src_d[275]
    DIRECTION INPUT ;
    USE SIGNAL ;
    PORT
      LAYER M4 ;
        RECT  0 39.888 0.084 39.912 ;
    END
  END src_d[275]
  PIN src_d[276]
    DIRECTION INPUT ;
    USE SIGNAL ;
    PORT
      LAYER M4 ;
        RECT  0 39.984 0.084 40.008 ;
    END
  END src_d[276]
  PIN src_d[277]
    DIRECTION INPUT ;
    USE SIGNAL ;
    PORT
      LAYER M4 ;
        RECT  0 40.08 0.084 40.104 ;
    END
  END src_d[277]
  PIN src_d[278]
    DIRECTION INPUT ;
    USE SIGNAL ;
    PORT
      LAYER M4 ;
        RECT  0 40.176 0.084 40.2 ;
    END
  END src_d[278]
  PIN src_d[279]
    DIRECTION INPUT ;
    USE SIGNAL ;
    PORT
      LAYER M4 ;
        RECT  0 40.272 0.084 40.296 ;
    END
  END src_d[279]
  PIN src_d[27]
    DIRECTION INPUT ;
    USE SIGNAL ;
    PORT
      LAYER M4 ;
        RECT  0 44.496 0.084 44.52 ;
    END
  END src_d[27]
  PIN src_d[280]
    DIRECTION INPUT ;
    USE SIGNAL ;
    PORT
      LAYER M4 ;
        RECT  0 40.368 0.084 40.392 ;
    END
  END src_d[280]
  PIN src_d[281]
    DIRECTION INPUT ;
    USE SIGNAL ;
    PORT
      LAYER M4 ;
        RECT  0 40.464 0.084 40.488 ;
    END
  END src_d[281]
  PIN src_d[282]
    DIRECTION INPUT ;
    USE SIGNAL ;
    PORT
      LAYER M4 ;
        RECT  0 40.56 0.084 40.584 ;
    END
  END src_d[282]
  PIN src_d[283]
    DIRECTION INPUT ;
    USE SIGNAL ;
    PORT
      LAYER M4 ;
        RECT  0 40.656 0.084 40.68 ;
    END
  END src_d[283]
  PIN src_d[284]
    DIRECTION INPUT ;
    USE SIGNAL ;
    PORT
      LAYER M4 ;
        RECT  0 40.752 0.084 40.776 ;
    END
  END src_d[284]
  PIN src_d[285]
    DIRECTION INPUT ;
    USE SIGNAL ;
    PORT
      LAYER M4 ;
        RECT  0 40.848 0.084 40.872 ;
    END
  END src_d[285]
  PIN src_d[286]
    DIRECTION INPUT ;
    USE SIGNAL ;
    PORT
      LAYER M4 ;
        RECT  0 40.944 0.084 40.968 ;
    END
  END src_d[286]
  PIN src_d[287]
    DIRECTION INPUT ;
    USE SIGNAL ;
    PORT
      LAYER M4 ;
        RECT  0 34.896 0.084 34.92 ;
    END
  END src_d[287]
  PIN src_d[288]
    DIRECTION INPUT ;
    USE SIGNAL ;
    PORT
      LAYER M4 ;
        RECT  0 34.992 0.084 35.016 ;
    END
  END src_d[288]
  PIN src_d[289]
    DIRECTION INPUT ;
    USE SIGNAL ;
    PORT
      LAYER M4 ;
        RECT  0 35.088 0.084 35.112 ;
    END
  END src_d[289]
  PIN src_d[28]
    DIRECTION INPUT ;
    USE SIGNAL ;
    PORT
      LAYER M4 ;
        RECT  0 44.592 0.084 44.616 ;
    END
  END src_d[28]
  PIN src_d[290]
    DIRECTION INPUT ;
    USE SIGNAL ;
    PORT
      LAYER M4 ;
        RECT  0 35.184 0.084 35.208 ;
    END
  END src_d[290]
  PIN src_d[291]
    DIRECTION INPUT ;
    USE SIGNAL ;
    PORT
      LAYER M4 ;
        RECT  0 35.28 0.084 35.304 ;
    END
  END src_d[291]
  PIN src_d[292]
    DIRECTION INPUT ;
    USE SIGNAL ;
    PORT
      LAYER M4 ;
        RECT  0 35.376 0.084 35.4 ;
    END
  END src_d[292]
  PIN src_d[293]
    DIRECTION INPUT ;
    USE SIGNAL ;
    PORT
      LAYER M4 ;
        RECT  0 35.472 0.084 35.496 ;
    END
  END src_d[293]
  PIN src_d[294]
    DIRECTION INPUT ;
    USE SIGNAL ;
    PORT
      LAYER M4 ;
        RECT  0 35.568 0.084 35.592 ;
    END
  END src_d[294]
  PIN src_d[295]
    DIRECTION INPUT ;
    USE SIGNAL ;
    PORT
      LAYER M4 ;
        RECT  0 35.664 0.084 35.688 ;
    END
  END src_d[295]
  PIN src_d[296]
    DIRECTION INPUT ;
    USE SIGNAL ;
    PORT
      LAYER M4 ;
        RECT  0 35.76 0.084 35.784 ;
    END
  END src_d[296]
  PIN src_d[297]
    DIRECTION INPUT ;
    USE SIGNAL ;
    PORT
      LAYER M4 ;
        RECT  0 35.856 0.084 35.88 ;
    END
  END src_d[297]
  PIN src_d[298]
    DIRECTION INPUT ;
    USE SIGNAL ;
    PORT
      LAYER M4 ;
        RECT  0 35.952 0.084 35.976 ;
    END
  END src_d[298]
  PIN src_d[299]
    DIRECTION INPUT ;
    USE SIGNAL ;
    PORT
      LAYER M4 ;
        RECT  0 36.048 0.084 36.072 ;
    END
  END src_d[299]
  PIN src_d[29]
    DIRECTION INPUT ;
    USE SIGNAL ;
    PORT
      LAYER M4 ;
        RECT  0 44.688 0.084 44.712 ;
    END
  END src_d[29]
  PIN src_d[2]
    DIRECTION INPUT ;
    USE SIGNAL ;
    PORT
      LAYER M4 ;
        RECT  0 42.096 0.084 42.12 ;
    END
  END src_d[2]
  PIN src_d[300]
    DIRECTION INPUT ;
    USE SIGNAL ;
    PORT
      LAYER M4 ;
        RECT  0 36.144 0.084 36.168 ;
    END
  END src_d[300]
  PIN src_d[301]
    DIRECTION INPUT ;
    USE SIGNAL ;
    PORT
      LAYER M4 ;
        RECT  0 36.24 0.084 36.264 ;
    END
  END src_d[301]
  PIN src_d[302]
    DIRECTION INPUT ;
    USE SIGNAL ;
    PORT
      LAYER M4 ;
        RECT  0 36.336 0.084 36.36 ;
    END
  END src_d[302]
  PIN src_d[303]
    DIRECTION INPUT ;
    USE SIGNAL ;
    PORT
      LAYER M4 ;
        RECT  0 36.432 0.084 36.456 ;
    END
  END src_d[303]
  PIN src_d[304]
    DIRECTION INPUT ;
    USE SIGNAL ;
    PORT
      LAYER M4 ;
        RECT  0 36.528 0.084 36.552 ;
    END
  END src_d[304]
  PIN src_d[305]
    DIRECTION INPUT ;
    USE SIGNAL ;
    PORT
      LAYER M4 ;
        RECT  0 36.624 0.084 36.648 ;
    END
  END src_d[305]
  PIN src_d[306]
    DIRECTION INPUT ;
    USE SIGNAL ;
    PORT
      LAYER M4 ;
        RECT  0 36.72 0.084 36.744 ;
    END
  END src_d[306]
  PIN src_d[307]
    DIRECTION INPUT ;
    USE SIGNAL ;
    PORT
      LAYER M4 ;
        RECT  0 36.816 0.084 36.84 ;
    END
  END src_d[307]
  PIN src_d[308]
    DIRECTION INPUT ;
    USE SIGNAL ;
    PORT
      LAYER M4 ;
        RECT  0 36.912 0.084 36.936 ;
    END
  END src_d[308]
  PIN src_d[309]
    DIRECTION INPUT ;
    USE SIGNAL ;
    PORT
      LAYER M4 ;
        RECT  0 37.008 0.084 37.032 ;
    END
  END src_d[309]
  PIN src_d[30]
    DIRECTION INPUT ;
    USE SIGNAL ;
    PORT
      LAYER M4 ;
        RECT  0 44.784 0.084 44.808 ;
    END
  END src_d[30]
  PIN src_d[310]
    DIRECTION INPUT ;
    USE SIGNAL ;
    PORT
      LAYER M4 ;
        RECT  0 37.104 0.084 37.128 ;
    END
  END src_d[310]
  PIN src_d[311]
    DIRECTION INPUT ;
    USE SIGNAL ;
    PORT
      LAYER M4 ;
        RECT  0 37.2 0.084 37.224 ;
    END
  END src_d[311]
  PIN src_d[312]
    DIRECTION INPUT ;
    USE SIGNAL ;
    PORT
      LAYER M4 ;
        RECT  0 37.296 0.084 37.32 ;
    END
  END src_d[312]
  PIN src_d[313]
    DIRECTION INPUT ;
    USE SIGNAL ;
    PORT
      LAYER M4 ;
        RECT  0 37.392 0.084 37.416 ;
    END
  END src_d[313]
  PIN src_d[314]
    DIRECTION INPUT ;
    USE SIGNAL ;
    PORT
      LAYER M4 ;
        RECT  0 37.488 0.084 37.512 ;
    END
  END src_d[314]
  PIN src_d[315]
    DIRECTION INPUT ;
    USE SIGNAL ;
    PORT
      LAYER M4 ;
        RECT  0 37.584 0.084 37.608 ;
    END
  END src_d[315]
  PIN src_d[316]
    DIRECTION INPUT ;
    USE SIGNAL ;
    PORT
      LAYER M4 ;
        RECT  0 37.68 0.084 37.704 ;
    END
  END src_d[316]
  PIN src_d[317]
    DIRECTION INPUT ;
    USE SIGNAL ;
    PORT
      LAYER M4 ;
        RECT  0 37.776 0.084 37.8 ;
    END
  END src_d[317]
  PIN src_d[318]
    DIRECTION INPUT ;
    USE SIGNAL ;
    PORT
      LAYER M4 ;
        RECT  0 37.872 0.084 37.896 ;
    END
  END src_d[318]
  PIN src_d[319]
    DIRECTION INPUT ;
    USE SIGNAL ;
    PORT
      LAYER M4 ;
        RECT  0 31.824 0.084 31.848 ;
    END
  END src_d[319]
  PIN src_d[31]
    DIRECTION INPUT ;
    USE SIGNAL ;
    PORT
      LAYER M4 ;
        RECT  0 54.096 0.084 54.12 ;
    END
  END src_d[31]
  PIN src_d[320]
    DIRECTION INPUT ;
    USE SIGNAL ;
    PORT
      LAYER M4 ;
        RECT  0 31.92 0.084 31.944 ;
    END
  END src_d[320]
  PIN src_d[321]
    DIRECTION INPUT ;
    USE SIGNAL ;
    PORT
      LAYER M4 ;
        RECT  0 32.016 0.084 32.04 ;
    END
  END src_d[321]
  PIN src_d[322]
    DIRECTION INPUT ;
    USE SIGNAL ;
    PORT
      LAYER M4 ;
        RECT  0 32.112 0.084 32.136 ;
    END
  END src_d[322]
  PIN src_d[323]
    DIRECTION INPUT ;
    USE SIGNAL ;
    PORT
      LAYER M4 ;
        RECT  0 32.208 0.084 32.232 ;
    END
  END src_d[323]
  PIN src_d[324]
    DIRECTION INPUT ;
    USE SIGNAL ;
    PORT
      LAYER M4 ;
        RECT  0 32.304 0.084 32.328 ;
    END
  END src_d[324]
  PIN src_d[325]
    DIRECTION INPUT ;
    USE SIGNAL ;
    PORT
      LAYER M4 ;
        RECT  0 32.4 0.084 32.424 ;
    END
  END src_d[325]
  PIN src_d[326]
    DIRECTION INPUT ;
    USE SIGNAL ;
    PORT
      LAYER M4 ;
        RECT  0 32.496 0.084 32.52 ;
    END
  END src_d[326]
  PIN src_d[327]
    DIRECTION INPUT ;
    USE SIGNAL ;
    PORT
      LAYER M4 ;
        RECT  0 32.592 0.084 32.616 ;
    END
  END src_d[327]
  PIN src_d[328]
    DIRECTION INPUT ;
    USE SIGNAL ;
    PORT
      LAYER M4 ;
        RECT  0 32.688 0.084 32.712 ;
    END
  END src_d[328]
  PIN src_d[329]
    DIRECTION INPUT ;
    USE SIGNAL ;
    PORT
      LAYER M4 ;
        RECT  0 32.784 0.084 32.808 ;
    END
  END src_d[329]
  PIN src_d[32]
    DIRECTION INPUT ;
    USE SIGNAL ;
    PORT
      LAYER M4 ;
        RECT  0 54.192 0.084 54.216 ;
    END
  END src_d[32]
  PIN src_d[330]
    DIRECTION INPUT ;
    USE SIGNAL ;
    PORT
      LAYER M4 ;
        RECT  0 32.88 0.084 32.904 ;
    END
  END src_d[330]
  PIN src_d[331]
    DIRECTION INPUT ;
    USE SIGNAL ;
    PORT
      LAYER M4 ;
        RECT  0 32.976 0.084 33 ;
    END
  END src_d[331]
  PIN src_d[332]
    DIRECTION INPUT ;
    USE SIGNAL ;
    PORT
      LAYER M4 ;
        RECT  0 33.072 0.084 33.096 ;
    END
  END src_d[332]
  PIN src_d[333]
    DIRECTION INPUT ;
    USE SIGNAL ;
    PORT
      LAYER M4 ;
        RECT  0 33.168 0.084 33.192 ;
    END
  END src_d[333]
  PIN src_d[334]
    DIRECTION INPUT ;
    USE SIGNAL ;
    PORT
      LAYER M4 ;
        RECT  0 33.264 0.084 33.288 ;
    END
  END src_d[334]
  PIN src_d[335]
    DIRECTION INPUT ;
    USE SIGNAL ;
    PORT
      LAYER M4 ;
        RECT  0 33.36 0.084 33.384 ;
    END
  END src_d[335]
  PIN src_d[336]
    DIRECTION INPUT ;
    USE SIGNAL ;
    PORT
      LAYER M4 ;
        RECT  0 33.456 0.084 33.48 ;
    END
  END src_d[336]
  PIN src_d[337]
    DIRECTION INPUT ;
    USE SIGNAL ;
    PORT
      LAYER M4 ;
        RECT  0 33.552 0.084 33.576 ;
    END
  END src_d[337]
  PIN src_d[338]
    DIRECTION INPUT ;
    USE SIGNAL ;
    PORT
      LAYER M4 ;
        RECT  0 33.648 0.084 33.672 ;
    END
  END src_d[338]
  PIN src_d[339]
    DIRECTION INPUT ;
    USE SIGNAL ;
    PORT
      LAYER M4 ;
        RECT  0 33.744 0.084 33.768 ;
    END
  END src_d[339]
  PIN src_d[33]
    DIRECTION INPUT ;
    USE SIGNAL ;
    PORT
      LAYER M4 ;
        RECT  0 54.288 0.084 54.312 ;
    END
  END src_d[33]
  PIN src_d[340]
    DIRECTION INPUT ;
    USE SIGNAL ;
    PORT
      LAYER M4 ;
        RECT  0 33.84 0.084 33.864 ;
    END
  END src_d[340]
  PIN src_d[341]
    DIRECTION INPUT ;
    USE SIGNAL ;
    PORT
      LAYER M4 ;
        RECT  0 33.936 0.084 33.96 ;
    END
  END src_d[341]
  PIN src_d[342]
    DIRECTION INPUT ;
    USE SIGNAL ;
    PORT
      LAYER M4 ;
        RECT  0 34.032 0.084 34.056 ;
    END
  END src_d[342]
  PIN src_d[343]
    DIRECTION INPUT ;
    USE SIGNAL ;
    PORT
      LAYER M4 ;
        RECT  0 34.128 0.084 34.152 ;
    END
  END src_d[343]
  PIN src_d[344]
    DIRECTION INPUT ;
    USE SIGNAL ;
    PORT
      LAYER M4 ;
        RECT  0 34.224 0.084 34.248 ;
    END
  END src_d[344]
  PIN src_d[345]
    DIRECTION INPUT ;
    USE SIGNAL ;
    PORT
      LAYER M4 ;
        RECT  0 34.32 0.084 34.344 ;
    END
  END src_d[345]
  PIN src_d[346]
    DIRECTION INPUT ;
    USE SIGNAL ;
    PORT
      LAYER M4 ;
        RECT  0 34.416 0.084 34.44 ;
    END
  END src_d[346]
  PIN src_d[347]
    DIRECTION INPUT ;
    USE SIGNAL ;
    PORT
      LAYER M4 ;
        RECT  0 34.512 0.084 34.536 ;
    END
  END src_d[347]
  PIN src_d[348]
    DIRECTION INPUT ;
    USE SIGNAL ;
    PORT
      LAYER M4 ;
        RECT  0 34.608 0.084 34.632 ;
    END
  END src_d[348]
  PIN src_d[349]
    DIRECTION INPUT ;
    USE SIGNAL ;
    PORT
      LAYER M4 ;
        RECT  0 34.704 0.084 34.728 ;
    END
  END src_d[349]
  PIN src_d[34]
    DIRECTION INPUT ;
    USE SIGNAL ;
    PORT
      LAYER M4 ;
        RECT  0 54.384 0.084 54.408 ;
    END
  END src_d[34]
  PIN src_d[350]
    DIRECTION INPUT ;
    USE SIGNAL ;
    PORT
      LAYER M4 ;
        RECT  0 34.8 0.084 34.824 ;
    END
  END src_d[350]
  PIN src_d[351]
    DIRECTION INPUT ;
    USE SIGNAL ;
    PORT
      LAYER M4 ;
        RECT  0 73.296 0.084 73.32 ;
    END
  END src_d[351]
  PIN src_d[352]
    DIRECTION INPUT ;
    USE SIGNAL ;
    PORT
      LAYER M4 ;
        RECT  0 73.392 0.084 73.416 ;
    END
  END src_d[352]
  PIN src_d[353]
    DIRECTION INPUT ;
    USE SIGNAL ;
    PORT
      LAYER M4 ;
        RECT  0 73.488 0.084 73.512 ;
    END
  END src_d[353]
  PIN src_d[354]
    DIRECTION INPUT ;
    USE SIGNAL ;
    PORT
      LAYER M4 ;
        RECT  0 73.584 0.084 73.608 ;
    END
  END src_d[354]
  PIN src_d[355]
    DIRECTION INPUT ;
    USE SIGNAL ;
    PORT
      LAYER M4 ;
        RECT  0 73.68 0.084 73.704 ;
    END
  END src_d[355]
  PIN src_d[356]
    DIRECTION INPUT ;
    USE SIGNAL ;
    PORT
      LAYER M4 ;
        RECT  0 73.776 0.084 73.8 ;
    END
  END src_d[356]
  PIN src_d[357]
    DIRECTION INPUT ;
    USE SIGNAL ;
    PORT
      LAYER M4 ;
        RECT  0 73.872 0.084 73.896 ;
    END
  END src_d[357]
  PIN src_d[358]
    DIRECTION INPUT ;
    USE SIGNAL ;
    PORT
      LAYER M4 ;
        RECT  0 73.968 0.084 73.992 ;
    END
  END src_d[358]
  PIN src_d[359]
    DIRECTION INPUT ;
    USE SIGNAL ;
    PORT
      LAYER M4 ;
        RECT  0 74.064 0.084 74.088 ;
    END
  END src_d[359]
  PIN src_d[35]
    DIRECTION INPUT ;
    USE SIGNAL ;
    PORT
      LAYER M4 ;
        RECT  0 54.48 0.084 54.504 ;
    END
  END src_d[35]
  PIN src_d[360]
    DIRECTION INPUT ;
    USE SIGNAL ;
    PORT
      LAYER M4 ;
        RECT  0 74.16 0.084 74.184 ;
    END
  END src_d[360]
  PIN src_d[361]
    DIRECTION INPUT ;
    USE SIGNAL ;
    PORT
      LAYER M4 ;
        RECT  0 74.256 0.084 74.28 ;
    END
  END src_d[361]
  PIN src_d[362]
    DIRECTION INPUT ;
    USE SIGNAL ;
    PORT
      LAYER M4 ;
        RECT  0 74.352 0.084 74.376 ;
    END
  END src_d[362]
  PIN src_d[363]
    DIRECTION INPUT ;
    USE SIGNAL ;
    PORT
      LAYER M4 ;
        RECT  0 74.448 0.084 74.472 ;
    END
  END src_d[363]
  PIN src_d[364]
    DIRECTION INPUT ;
    USE SIGNAL ;
    PORT
      LAYER M4 ;
        RECT  0 74.544 0.084 74.568 ;
    END
  END src_d[364]
  PIN src_d[365]
    DIRECTION INPUT ;
    USE SIGNAL ;
    PORT
      LAYER M4 ;
        RECT  0 74.64 0.084 74.664 ;
    END
  END src_d[365]
  PIN src_d[366]
    DIRECTION INPUT ;
    USE SIGNAL ;
    PORT
      LAYER M4 ;
        RECT  0 74.736 0.084 74.76 ;
    END
  END src_d[366]
  PIN src_d[367]
    DIRECTION INPUT ;
    USE SIGNAL ;
    PORT
      LAYER M4 ;
        RECT  0 74.832 0.084 74.856 ;
    END
  END src_d[367]
  PIN src_d[368]
    DIRECTION INPUT ;
    USE SIGNAL ;
    PORT
      LAYER M4 ;
        RECT  0 74.928 0.084 74.952 ;
    END
  END src_d[368]
  PIN src_d[369]
    DIRECTION INPUT ;
    USE SIGNAL ;
    PORT
      LAYER M4 ;
        RECT  0 75.024 0.084 75.048 ;
    END
  END src_d[369]
  PIN src_d[36]
    DIRECTION INPUT ;
    USE SIGNAL ;
    PORT
      LAYER M4 ;
        RECT  0 54.576 0.084 54.6 ;
    END
  END src_d[36]
  PIN src_d[370]
    DIRECTION INPUT ;
    USE SIGNAL ;
    PORT
      LAYER M4 ;
        RECT  0 75.12 0.084 75.144 ;
    END
  END src_d[370]
  PIN src_d[371]
    DIRECTION INPUT ;
    USE SIGNAL ;
    PORT
      LAYER M4 ;
        RECT  0 75.216 0.084 75.24 ;
    END
  END src_d[371]
  PIN src_d[372]
    DIRECTION INPUT ;
    USE SIGNAL ;
    PORT
      LAYER M4 ;
        RECT  0 75.312 0.084 75.336 ;
    END
  END src_d[372]
  PIN src_d[373]
    DIRECTION INPUT ;
    USE SIGNAL ;
    PORT
      LAYER M4 ;
        RECT  0 75.408 0.084 75.432 ;
    END
  END src_d[373]
  PIN src_d[374]
    DIRECTION INPUT ;
    USE SIGNAL ;
    PORT
      LAYER M4 ;
        RECT  0 75.504 0.084 75.528 ;
    END
  END src_d[374]
  PIN src_d[375]
    DIRECTION INPUT ;
    USE SIGNAL ;
    PORT
      LAYER M4 ;
        RECT  0 75.6 0.084 75.624 ;
    END
  END src_d[375]
  PIN src_d[376]
    DIRECTION INPUT ;
    USE SIGNAL ;
    PORT
      LAYER M4 ;
        RECT  0 75.696 0.084 75.72 ;
    END
  END src_d[376]
  PIN src_d[377]
    DIRECTION INPUT ;
    USE SIGNAL ;
    PORT
      LAYER M4 ;
        RECT  0 75.792 0.084 75.816 ;
    END
  END src_d[377]
  PIN src_d[378]
    DIRECTION INPUT ;
    USE SIGNAL ;
    PORT
      LAYER M4 ;
        RECT  0 75.888 0.084 75.912 ;
    END
  END src_d[378]
  PIN src_d[379]
    DIRECTION INPUT ;
    USE SIGNAL ;
    PORT
      LAYER M4 ;
        RECT  0 75.984 0.084 76.008 ;
    END
  END src_d[379]
  PIN src_d[37]
    DIRECTION INPUT ;
    USE SIGNAL ;
    PORT
      LAYER M4 ;
        RECT  0 54.672 0.084 54.696 ;
    END
  END src_d[37]
  PIN src_d[380]
    DIRECTION INPUT ;
    USE SIGNAL ;
    PORT
      LAYER M4 ;
        RECT  0 76.08 0.084 76.104 ;
    END
  END src_d[380]
  PIN src_d[381]
    DIRECTION INPUT ;
    USE SIGNAL ;
    PORT
      LAYER M4 ;
        RECT  0 76.176 0.084 76.2 ;
    END
  END src_d[381]
  PIN src_d[382]
    DIRECTION INPUT ;
    USE SIGNAL ;
    PORT
      LAYER M4 ;
        RECT  0 76.272 0.084 76.296 ;
    END
  END src_d[382]
  PIN src_d[383]
    DIRECTION INPUT ;
    USE SIGNAL ;
    PORT
      LAYER M4 ;
        RECT  0 28.752 0.084 28.776 ;
    END
  END src_d[383]
  PIN src_d[384]
    DIRECTION INPUT ;
    USE SIGNAL ;
    PORT
      LAYER M4 ;
        RECT  0 28.848 0.084 28.872 ;
    END
  END src_d[384]
  PIN src_d[385]
    DIRECTION INPUT ;
    USE SIGNAL ;
    PORT
      LAYER M4 ;
        RECT  0 28.944 0.084 28.968 ;
    END
  END src_d[385]
  PIN src_d[386]
    DIRECTION INPUT ;
    USE SIGNAL ;
    PORT
      LAYER M4 ;
        RECT  0 29.04 0.084 29.064 ;
    END
  END src_d[386]
  PIN src_d[387]
    DIRECTION INPUT ;
    USE SIGNAL ;
    PORT
      LAYER M4 ;
        RECT  0 29.136 0.084 29.16 ;
    END
  END src_d[387]
  PIN src_d[388]
    DIRECTION INPUT ;
    USE SIGNAL ;
    PORT
      LAYER M4 ;
        RECT  0 29.232 0.084 29.256 ;
    END
  END src_d[388]
  PIN src_d[389]
    DIRECTION INPUT ;
    USE SIGNAL ;
    PORT
      LAYER M4 ;
        RECT  0 29.328 0.084 29.352 ;
    END
  END src_d[389]
  PIN src_d[38]
    DIRECTION INPUT ;
    USE SIGNAL ;
    PORT
      LAYER M4 ;
        RECT  0 54.768 0.084 54.792 ;
    END
  END src_d[38]
  PIN src_d[390]
    DIRECTION INPUT ;
    USE SIGNAL ;
    PORT
      LAYER M4 ;
        RECT  0 29.424 0.084 29.448 ;
    END
  END src_d[390]
  PIN src_d[391]
    DIRECTION INPUT ;
    USE SIGNAL ;
    PORT
      LAYER M4 ;
        RECT  0 29.52 0.084 29.544 ;
    END
  END src_d[391]
  PIN src_d[392]
    DIRECTION INPUT ;
    USE SIGNAL ;
    PORT
      LAYER M4 ;
        RECT  0 29.616 0.084 29.64 ;
    END
  END src_d[392]
  PIN src_d[393]
    DIRECTION INPUT ;
    USE SIGNAL ;
    PORT
      LAYER M4 ;
        RECT  0 29.712 0.084 29.736 ;
    END
  END src_d[393]
  PIN src_d[394]
    DIRECTION INPUT ;
    USE SIGNAL ;
    PORT
      LAYER M4 ;
        RECT  0 29.808 0.084 29.832 ;
    END
  END src_d[394]
  PIN src_d[395]
    DIRECTION INPUT ;
    USE SIGNAL ;
    PORT
      LAYER M4 ;
        RECT  0 29.904 0.084 29.928 ;
    END
  END src_d[395]
  PIN src_d[396]
    DIRECTION INPUT ;
    USE SIGNAL ;
    PORT
      LAYER M4 ;
        RECT  0 30 0.084 30.024 ;
    END
  END src_d[396]
  PIN src_d[397]
    DIRECTION INPUT ;
    USE SIGNAL ;
    PORT
      LAYER M4 ;
        RECT  0 30.096 0.084 30.12 ;
    END
  END src_d[397]
  PIN src_d[398]
    DIRECTION INPUT ;
    USE SIGNAL ;
    PORT
      LAYER M4 ;
        RECT  0 30.192 0.084 30.216 ;
    END
  END src_d[398]
  PIN src_d[399]
    DIRECTION INPUT ;
    USE SIGNAL ;
    PORT
      LAYER M4 ;
        RECT  0 30.288 0.084 30.312 ;
    END
  END src_d[399]
  PIN src_d[39]
    DIRECTION INPUT ;
    USE SIGNAL ;
    PORT
      LAYER M4 ;
        RECT  0 54.864 0.084 54.888 ;
    END
  END src_d[39]
  PIN src_d[3]
    DIRECTION INPUT ;
    USE SIGNAL ;
    PORT
      LAYER M4 ;
        RECT  0 42.192 0.084 42.216 ;
    END
  END src_d[3]
  PIN src_d[400]
    DIRECTION INPUT ;
    USE SIGNAL ;
    PORT
      LAYER M4 ;
        RECT  0 30.384 0.084 30.408 ;
    END
  END src_d[400]
  PIN src_d[401]
    DIRECTION INPUT ;
    USE SIGNAL ;
    PORT
      LAYER M4 ;
        RECT  0 30.48 0.084 30.504 ;
    END
  END src_d[401]
  PIN src_d[402]
    DIRECTION INPUT ;
    USE SIGNAL ;
    PORT
      LAYER M4 ;
        RECT  0 30.576 0.084 30.6 ;
    END
  END src_d[402]
  PIN src_d[403]
    DIRECTION INPUT ;
    USE SIGNAL ;
    PORT
      LAYER M4 ;
        RECT  0 30.672 0.084 30.696 ;
    END
  END src_d[403]
  PIN src_d[404]
    DIRECTION INPUT ;
    USE SIGNAL ;
    PORT
      LAYER M4 ;
        RECT  0 30.768 0.084 30.792 ;
    END
  END src_d[404]
  PIN src_d[405]
    DIRECTION INPUT ;
    USE SIGNAL ;
    PORT
      LAYER M4 ;
        RECT  0 30.864 0.084 30.888 ;
    END
  END src_d[405]
  PIN src_d[406]
    DIRECTION INPUT ;
    USE SIGNAL ;
    PORT
      LAYER M4 ;
        RECT  0 30.96 0.084 30.984 ;
    END
  END src_d[406]
  PIN src_d[407]
    DIRECTION INPUT ;
    USE SIGNAL ;
    PORT
      LAYER M4 ;
        RECT  0 31.056 0.084 31.08 ;
    END
  END src_d[407]
  PIN src_d[408]
    DIRECTION INPUT ;
    USE SIGNAL ;
    PORT
      LAYER M4 ;
        RECT  0 31.152 0.084 31.176 ;
    END
  END src_d[408]
  PIN src_d[409]
    DIRECTION INPUT ;
    USE SIGNAL ;
    PORT
      LAYER M4 ;
        RECT  0 31.248 0.084 31.272 ;
    END
  END src_d[409]
  PIN src_d[40]
    DIRECTION INPUT ;
    USE SIGNAL ;
    PORT
      LAYER M4 ;
        RECT  0 54.96 0.084 54.984 ;
    END
  END src_d[40]
  PIN src_d[410]
    DIRECTION INPUT ;
    USE SIGNAL ;
    PORT
      LAYER M4 ;
        RECT  0 31.344 0.084 31.368 ;
    END
  END src_d[410]
  PIN src_d[411]
    DIRECTION INPUT ;
    USE SIGNAL ;
    PORT
      LAYER M4 ;
        RECT  0 31.44 0.084 31.464 ;
    END
  END src_d[411]
  PIN src_d[412]
    DIRECTION INPUT ;
    USE SIGNAL ;
    PORT
      LAYER M4 ;
        RECT  0 31.536 0.084 31.56 ;
    END
  END src_d[412]
  PIN src_d[413]
    DIRECTION INPUT ;
    USE SIGNAL ;
    PORT
      LAYER M4 ;
        RECT  0 31.632 0.084 31.656 ;
    END
  END src_d[413]
  PIN src_d[414]
    DIRECTION INPUT ;
    USE SIGNAL ;
    PORT
      LAYER M4 ;
        RECT  0 31.728 0.084 31.752 ;
    END
  END src_d[414]
  PIN src_d[415]
    DIRECTION INPUT ;
    USE SIGNAL ;
    PORT
      LAYER M4 ;
        RECT  0 64.08 0.084 64.104 ;
    END
  END src_d[415]
  PIN src_d[416]
    DIRECTION INPUT ;
    USE SIGNAL ;
    PORT
      LAYER M4 ;
        RECT  0 64.176 0.084 64.2 ;
    END
  END src_d[416]
  PIN src_d[417]
    DIRECTION INPUT ;
    USE SIGNAL ;
    PORT
      LAYER M4 ;
        RECT  0 64.272 0.084 64.296 ;
    END
  END src_d[417]
  PIN src_d[418]
    DIRECTION INPUT ;
    USE SIGNAL ;
    PORT
      LAYER M4 ;
        RECT  0 64.368 0.084 64.392 ;
    END
  END src_d[418]
  PIN src_d[419]
    DIRECTION INPUT ;
    USE SIGNAL ;
    PORT
      LAYER M4 ;
        RECT  0 64.464 0.084 64.488 ;
    END
  END src_d[419]
  PIN src_d[41]
    DIRECTION INPUT ;
    USE SIGNAL ;
    PORT
      LAYER M4 ;
        RECT  0 55.056 0.084 55.08 ;
    END
  END src_d[41]
  PIN src_d[420]
    DIRECTION INPUT ;
    USE SIGNAL ;
    PORT
      LAYER M4 ;
        RECT  0 64.56 0.084 64.584 ;
    END
  END src_d[420]
  PIN src_d[421]
    DIRECTION INPUT ;
    USE SIGNAL ;
    PORT
      LAYER M4 ;
        RECT  0 64.656 0.084 64.68 ;
    END
  END src_d[421]
  PIN src_d[422]
    DIRECTION INPUT ;
    USE SIGNAL ;
    PORT
      LAYER M4 ;
        RECT  0 64.752 0.084 64.776 ;
    END
  END src_d[422]
  PIN src_d[423]
    DIRECTION INPUT ;
    USE SIGNAL ;
    PORT
      LAYER M4 ;
        RECT  0 64.848 0.084 64.872 ;
    END
  END src_d[423]
  PIN src_d[424]
    DIRECTION INPUT ;
    USE SIGNAL ;
    PORT
      LAYER M4 ;
        RECT  0 64.944 0.084 64.968 ;
    END
  END src_d[424]
  PIN src_d[425]
    DIRECTION INPUT ;
    USE SIGNAL ;
    PORT
      LAYER M4 ;
        RECT  0 65.04 0.084 65.064 ;
    END
  END src_d[425]
  PIN src_d[426]
    DIRECTION INPUT ;
    USE SIGNAL ;
    PORT
      LAYER M4 ;
        RECT  0 65.136 0.084 65.16 ;
    END
  END src_d[426]
  PIN src_d[427]
    DIRECTION INPUT ;
    USE SIGNAL ;
    PORT
      LAYER M4 ;
        RECT  0 65.232 0.084 65.256 ;
    END
  END src_d[427]
  PIN src_d[428]
    DIRECTION INPUT ;
    USE SIGNAL ;
    PORT
      LAYER M4 ;
        RECT  0 65.328 0.084 65.352 ;
    END
  END src_d[428]
  PIN src_d[429]
    DIRECTION INPUT ;
    USE SIGNAL ;
    PORT
      LAYER M4 ;
        RECT  0 65.424 0.084 65.448 ;
    END
  END src_d[429]
  PIN src_d[42]
    DIRECTION INPUT ;
    USE SIGNAL ;
    PORT
      LAYER M4 ;
        RECT  0 55.152 0.084 55.176 ;
    END
  END src_d[42]
  PIN src_d[430]
    DIRECTION INPUT ;
    USE SIGNAL ;
    PORT
      LAYER M4 ;
        RECT  0 65.52 0.084 65.544 ;
    END
  END src_d[430]
  PIN src_d[431]
    DIRECTION INPUT ;
    USE SIGNAL ;
    PORT
      LAYER M4 ;
        RECT  0 65.616 0.084 65.64 ;
    END
  END src_d[431]
  PIN src_d[432]
    DIRECTION INPUT ;
    USE SIGNAL ;
    PORT
      LAYER M4 ;
        RECT  0 65.712 0.084 65.736 ;
    END
  END src_d[432]
  PIN src_d[433]
    DIRECTION INPUT ;
    USE SIGNAL ;
    PORT
      LAYER M4 ;
        RECT  0 65.808 0.084 65.832 ;
    END
  END src_d[433]
  PIN src_d[434]
    DIRECTION INPUT ;
    USE SIGNAL ;
    PORT
      LAYER M4 ;
        RECT  0 65.904 0.084 65.928 ;
    END
  END src_d[434]
  PIN src_d[435]
    DIRECTION INPUT ;
    USE SIGNAL ;
    PORT
      LAYER M4 ;
        RECT  0 66 0.084 66.024 ;
    END
  END src_d[435]
  PIN src_d[436]
    DIRECTION INPUT ;
    USE SIGNAL ;
    PORT
      LAYER M4 ;
        RECT  0 66.096 0.084 66.12 ;
    END
  END src_d[436]
  PIN src_d[437]
    DIRECTION INPUT ;
    USE SIGNAL ;
    PORT
      LAYER M4 ;
        RECT  0 66.192 0.084 66.216 ;
    END
  END src_d[437]
  PIN src_d[438]
    DIRECTION INPUT ;
    USE SIGNAL ;
    PORT
      LAYER M4 ;
        RECT  0 66.288 0.084 66.312 ;
    END
  END src_d[438]
  PIN src_d[439]
    DIRECTION INPUT ;
    USE SIGNAL ;
    PORT
      LAYER M4 ;
        RECT  0 66.384 0.084 66.408 ;
    END
  END src_d[439]
  PIN src_d[43]
    DIRECTION INPUT ;
    USE SIGNAL ;
    PORT
      LAYER M4 ;
        RECT  0 55.248 0.084 55.272 ;
    END
  END src_d[43]
  PIN src_d[440]
    DIRECTION INPUT ;
    USE SIGNAL ;
    PORT
      LAYER M4 ;
        RECT  0 66.48 0.084 66.504 ;
    END
  END src_d[440]
  PIN src_d[441]
    DIRECTION INPUT ;
    USE SIGNAL ;
    PORT
      LAYER M4 ;
        RECT  0 66.576 0.084 66.6 ;
    END
  END src_d[441]
  PIN src_d[442]
    DIRECTION INPUT ;
    USE SIGNAL ;
    PORT
      LAYER M4 ;
        RECT  0 66.672 0.084 66.696 ;
    END
  END src_d[442]
  PIN src_d[443]
    DIRECTION INPUT ;
    USE SIGNAL ;
    PORT
      LAYER M4 ;
        RECT  0 66.768 0.084 66.792 ;
    END
  END src_d[443]
  PIN src_d[444]
    DIRECTION INPUT ;
    USE SIGNAL ;
    PORT
      LAYER M4 ;
        RECT  0 66.864 0.084 66.888 ;
    END
  END src_d[444]
  PIN src_d[445]
    DIRECTION INPUT ;
    USE SIGNAL ;
    PORT
      LAYER M4 ;
        RECT  0 66.96 0.084 66.984 ;
    END
  END src_d[445]
  PIN src_d[446]
    DIRECTION INPUT ;
    USE SIGNAL ;
    PORT
      LAYER M4 ;
        RECT  0 67.056 0.084 67.08 ;
    END
  END src_d[446]
  PIN src_d[447]
    DIRECTION INPUT ;
    USE SIGNAL ;
    PORT
      LAYER M4 ;
        RECT  0 70.224 0.084 70.248 ;
    END
  END src_d[447]
  PIN src_d[448]
    DIRECTION INPUT ;
    USE SIGNAL ;
    PORT
      LAYER M4 ;
        RECT  0 70.32 0.084 70.344 ;
    END
  END src_d[448]
  PIN src_d[449]
    DIRECTION INPUT ;
    USE SIGNAL ;
    PORT
      LAYER M4 ;
        RECT  0 70.416 0.084 70.44 ;
    END
  END src_d[449]
  PIN src_d[44]
    DIRECTION INPUT ;
    USE SIGNAL ;
    PORT
      LAYER M4 ;
        RECT  0 55.344 0.084 55.368 ;
    END
  END src_d[44]
  PIN src_d[450]
    DIRECTION INPUT ;
    USE SIGNAL ;
    PORT
      LAYER M4 ;
        RECT  0 70.512 0.084 70.536 ;
    END
  END src_d[450]
  PIN src_d[451]
    DIRECTION INPUT ;
    USE SIGNAL ;
    PORT
      LAYER M4 ;
        RECT  0 70.608 0.084 70.632 ;
    END
  END src_d[451]
  PIN src_d[452]
    DIRECTION INPUT ;
    USE SIGNAL ;
    PORT
      LAYER M4 ;
        RECT  0 70.704 0.084 70.728 ;
    END
  END src_d[452]
  PIN src_d[453]
    DIRECTION INPUT ;
    USE SIGNAL ;
    PORT
      LAYER M4 ;
        RECT  0 70.8 0.084 70.824 ;
    END
  END src_d[453]
  PIN src_d[454]
    DIRECTION INPUT ;
    USE SIGNAL ;
    PORT
      LAYER M4 ;
        RECT  0 70.896 0.084 70.92 ;
    END
  END src_d[454]
  PIN src_d[455]
    DIRECTION INPUT ;
    USE SIGNAL ;
    PORT
      LAYER M4 ;
        RECT  0 70.992 0.084 71.016 ;
    END
  END src_d[455]
  PIN src_d[456]
    DIRECTION INPUT ;
    USE SIGNAL ;
    PORT
      LAYER M4 ;
        RECT  0 71.088 0.084 71.112 ;
    END
  END src_d[456]
  PIN src_d[457]
    DIRECTION INPUT ;
    USE SIGNAL ;
    PORT
      LAYER M4 ;
        RECT  0 71.184 0.084 71.208 ;
    END
  END src_d[457]
  PIN src_d[458]
    DIRECTION INPUT ;
    USE SIGNAL ;
    PORT
      LAYER M4 ;
        RECT  0 71.28 0.084 71.304 ;
    END
  END src_d[458]
  PIN src_d[459]
    DIRECTION INPUT ;
    USE SIGNAL ;
    PORT
      LAYER M4 ;
        RECT  0 71.376 0.084 71.4 ;
    END
  END src_d[459]
  PIN src_d[45]
    DIRECTION INPUT ;
    USE SIGNAL ;
    PORT
      LAYER M4 ;
        RECT  0 55.44 0.084 55.464 ;
    END
  END src_d[45]
  PIN src_d[460]
    DIRECTION INPUT ;
    USE SIGNAL ;
    PORT
      LAYER M4 ;
        RECT  0 71.472 0.084 71.496 ;
    END
  END src_d[460]
  PIN src_d[461]
    DIRECTION INPUT ;
    USE SIGNAL ;
    PORT
      LAYER M4 ;
        RECT  0 71.568 0.084 71.592 ;
    END
  END src_d[461]
  PIN src_d[462]
    DIRECTION INPUT ;
    USE SIGNAL ;
    PORT
      LAYER M4 ;
        RECT  0 71.664 0.084 71.688 ;
    END
  END src_d[462]
  PIN src_d[463]
    DIRECTION INPUT ;
    USE SIGNAL ;
    PORT
      LAYER M4 ;
        RECT  0 71.76 0.084 71.784 ;
    END
  END src_d[463]
  PIN src_d[464]
    DIRECTION INPUT ;
    USE SIGNAL ;
    PORT
      LAYER M4 ;
        RECT  0 71.856 0.084 71.88 ;
    END
  END src_d[464]
  PIN src_d[465]
    DIRECTION INPUT ;
    USE SIGNAL ;
    PORT
      LAYER M4 ;
        RECT  0 71.952 0.084 71.976 ;
    END
  END src_d[465]
  PIN src_d[466]
    DIRECTION INPUT ;
    USE SIGNAL ;
    PORT
      LAYER M4 ;
        RECT  0 72.048 0.084 72.072 ;
    END
  END src_d[466]
  PIN src_d[467]
    DIRECTION INPUT ;
    USE SIGNAL ;
    PORT
      LAYER M4 ;
        RECT  0 72.144 0.084 72.168 ;
    END
  END src_d[467]
  PIN src_d[468]
    DIRECTION INPUT ;
    USE SIGNAL ;
    PORT
      LAYER M4 ;
        RECT  0 72.24 0.084 72.264 ;
    END
  END src_d[468]
  PIN src_d[469]
    DIRECTION INPUT ;
    USE SIGNAL ;
    PORT
      LAYER M4 ;
        RECT  0 72.336 0.084 72.36 ;
    END
  END src_d[469]
  PIN src_d[46]
    DIRECTION INPUT ;
    USE SIGNAL ;
    PORT
      LAYER M4 ;
        RECT  0 55.536 0.084 55.56 ;
    END
  END src_d[46]
  PIN src_d[470]
    DIRECTION INPUT ;
    USE SIGNAL ;
    PORT
      LAYER M4 ;
        RECT  0 72.432 0.084 72.456 ;
    END
  END src_d[470]
  PIN src_d[471]
    DIRECTION INPUT ;
    USE SIGNAL ;
    PORT
      LAYER M4 ;
        RECT  0 72.528 0.084 72.552 ;
    END
  END src_d[471]
  PIN src_d[472]
    DIRECTION INPUT ;
    USE SIGNAL ;
    PORT
      LAYER M4 ;
        RECT  0 72.624 0.084 72.648 ;
    END
  END src_d[472]
  PIN src_d[473]
    DIRECTION INPUT ;
    USE SIGNAL ;
    PORT
      LAYER M4 ;
        RECT  0 72.72 0.084 72.744 ;
    END
  END src_d[473]
  PIN src_d[474]
    DIRECTION INPUT ;
    USE SIGNAL ;
    PORT
      LAYER M4 ;
        RECT  0 72.816 0.084 72.84 ;
    END
  END src_d[474]
  PIN src_d[475]
    DIRECTION INPUT ;
    USE SIGNAL ;
    PORT
      LAYER M4 ;
        RECT  0 72.912 0.084 72.936 ;
    END
  END src_d[475]
  PIN src_d[476]
    DIRECTION INPUT ;
    USE SIGNAL ;
    PORT
      LAYER M4 ;
        RECT  0 73.008 0.084 73.032 ;
    END
  END src_d[476]
  PIN src_d[477]
    DIRECTION INPUT ;
    USE SIGNAL ;
    PORT
      LAYER M4 ;
        RECT  0 73.104 0.084 73.128 ;
    END
  END src_d[477]
  PIN src_d[478]
    DIRECTION INPUT ;
    USE SIGNAL ;
    PORT
      LAYER M4 ;
        RECT  0 73.2 0.084 73.224 ;
    END
  END src_d[478]
  PIN src_d[479]
    DIRECTION INPUT ;
    USE SIGNAL ;
    PORT
      LAYER M4 ;
        RECT  0 67.152 0.084 67.176 ;
    END
  END src_d[479]
  PIN src_d[47]
    DIRECTION INPUT ;
    USE SIGNAL ;
    PORT
      LAYER M4 ;
        RECT  0 55.632 0.084 55.656 ;
    END
  END src_d[47]
  PIN src_d[480]
    DIRECTION INPUT ;
    USE SIGNAL ;
    PORT
      LAYER M4 ;
        RECT  0 67.248 0.084 67.272 ;
    END
  END src_d[480]
  PIN src_d[481]
    DIRECTION INPUT ;
    USE SIGNAL ;
    PORT
      LAYER M4 ;
        RECT  0 67.344 0.084 67.368 ;
    END
  END src_d[481]
  PIN src_d[482]
    DIRECTION INPUT ;
    USE SIGNAL ;
    PORT
      LAYER M4 ;
        RECT  0 67.44 0.084 67.464 ;
    END
  END src_d[482]
  PIN src_d[483]
    DIRECTION INPUT ;
    USE SIGNAL ;
    PORT
      LAYER M4 ;
        RECT  0 67.536 0.084 67.56 ;
    END
  END src_d[483]
  PIN src_d[484]
    DIRECTION INPUT ;
    USE SIGNAL ;
    PORT
      LAYER M4 ;
        RECT  0 67.632 0.084 67.656 ;
    END
  END src_d[484]
  PIN src_d[485]
    DIRECTION INPUT ;
    USE SIGNAL ;
    PORT
      LAYER M4 ;
        RECT  0 67.728 0.084 67.752 ;
    END
  END src_d[485]
  PIN src_d[486]
    DIRECTION INPUT ;
    USE SIGNAL ;
    PORT
      LAYER M4 ;
        RECT  0 67.824 0.084 67.848 ;
    END
  END src_d[486]
  PIN src_d[487]
    DIRECTION INPUT ;
    USE SIGNAL ;
    PORT
      LAYER M4 ;
        RECT  0 67.92 0.084 67.944 ;
    END
  END src_d[487]
  PIN src_d[488]
    DIRECTION INPUT ;
    USE SIGNAL ;
    PORT
      LAYER M4 ;
        RECT  0 68.016 0.084 68.04 ;
    END
  END src_d[488]
  PIN src_d[489]
    DIRECTION INPUT ;
    USE SIGNAL ;
    PORT
      LAYER M4 ;
        RECT  0 68.112 0.084 68.136 ;
    END
  END src_d[489]
  PIN src_d[48]
    DIRECTION INPUT ;
    USE SIGNAL ;
    PORT
      LAYER M4 ;
        RECT  0 55.728 0.084 55.752 ;
    END
  END src_d[48]
  PIN src_d[490]
    DIRECTION INPUT ;
    USE SIGNAL ;
    PORT
      LAYER M4 ;
        RECT  0 68.208 0.084 68.232 ;
    END
  END src_d[490]
  PIN src_d[491]
    DIRECTION INPUT ;
    USE SIGNAL ;
    PORT
      LAYER M4 ;
        RECT  0 68.304 0.084 68.328 ;
    END
  END src_d[491]
  PIN src_d[492]
    DIRECTION INPUT ;
    USE SIGNAL ;
    PORT
      LAYER M4 ;
        RECT  0 68.4 0.084 68.424 ;
    END
  END src_d[492]
  PIN src_d[493]
    DIRECTION INPUT ;
    USE SIGNAL ;
    PORT
      LAYER M4 ;
        RECT  0 68.496 0.084 68.52 ;
    END
  END src_d[493]
  PIN src_d[494]
    DIRECTION INPUT ;
    USE SIGNAL ;
    PORT
      LAYER M4 ;
        RECT  0 68.592 0.084 68.616 ;
    END
  END src_d[494]
  PIN src_d[495]
    DIRECTION INPUT ;
    USE SIGNAL ;
    PORT
      LAYER M4 ;
        RECT  0 68.688 0.084 68.712 ;
    END
  END src_d[495]
  PIN src_d[496]
    DIRECTION INPUT ;
    USE SIGNAL ;
    PORT
      LAYER M4 ;
        RECT  0 68.784 0.084 68.808 ;
    END
  END src_d[496]
  PIN src_d[497]
    DIRECTION INPUT ;
    USE SIGNAL ;
    PORT
      LAYER M4 ;
        RECT  0 68.88 0.084 68.904 ;
    END
  END src_d[497]
  PIN src_d[498]
    DIRECTION INPUT ;
    USE SIGNAL ;
    PORT
      LAYER M4 ;
        RECT  0 68.976 0.084 69 ;
    END
  END src_d[498]
  PIN src_d[499]
    DIRECTION INPUT ;
    USE SIGNAL ;
    PORT
      LAYER M4 ;
        RECT  0 69.072 0.084 69.096 ;
    END
  END src_d[499]
  PIN src_d[49]
    DIRECTION INPUT ;
    USE SIGNAL ;
    PORT
      LAYER M4 ;
        RECT  0 55.824 0.084 55.848 ;
    END
  END src_d[49]
  PIN src_d[4]
    DIRECTION INPUT ;
    USE SIGNAL ;
    PORT
      LAYER M4 ;
        RECT  0 42.288 0.084 42.312 ;
    END
  END src_d[4]
  PIN src_d[500]
    DIRECTION INPUT ;
    USE SIGNAL ;
    PORT
      LAYER M4 ;
        RECT  0 69.168 0.084 69.192 ;
    END
  END src_d[500]
  PIN src_d[501]
    DIRECTION INPUT ;
    USE SIGNAL ;
    PORT
      LAYER M4 ;
        RECT  0 69.264 0.084 69.288 ;
    END
  END src_d[501]
  PIN src_d[502]
    DIRECTION INPUT ;
    USE SIGNAL ;
    PORT
      LAYER M4 ;
        RECT  0 69.36 0.084 69.384 ;
    END
  END src_d[502]
  PIN src_d[503]
    DIRECTION INPUT ;
    USE SIGNAL ;
    PORT
      LAYER M4 ;
        RECT  0 69.456 0.084 69.48 ;
    END
  END src_d[503]
  PIN src_d[504]
    DIRECTION INPUT ;
    USE SIGNAL ;
    PORT
      LAYER M4 ;
        RECT  0 69.552 0.084 69.576 ;
    END
  END src_d[504]
  PIN src_d[505]
    DIRECTION INPUT ;
    USE SIGNAL ;
    PORT
      LAYER M4 ;
        RECT  0 69.648 0.084 69.672 ;
    END
  END src_d[505]
  PIN src_d[506]
    DIRECTION INPUT ;
    USE SIGNAL ;
    PORT
      LAYER M4 ;
        RECT  0 69.744 0.084 69.768 ;
    END
  END src_d[506]
  PIN src_d[507]
    DIRECTION INPUT ;
    USE SIGNAL ;
    PORT
      LAYER M4 ;
        RECT  0 69.84 0.084 69.864 ;
    END
  END src_d[507]
  PIN src_d[508]
    DIRECTION INPUT ;
    USE SIGNAL ;
    PORT
      LAYER M4 ;
        RECT  0 69.936 0.084 69.96 ;
    END
  END src_d[508]
  PIN src_d[509]
    DIRECTION INPUT ;
    USE SIGNAL ;
    PORT
      LAYER M4 ;
        RECT  0 70.032 0.084 70.056 ;
    END
  END src_d[509]
  PIN src_d[50]
    DIRECTION INPUT ;
    USE SIGNAL ;
    PORT
      LAYER M4 ;
        RECT  0 55.92 0.084 55.944 ;
    END
  END src_d[50]
  PIN src_d[510]
    DIRECTION INPUT ;
    USE SIGNAL ;
    PORT
      LAYER M4 ;
        RECT  0 70.128 0.084 70.152 ;
    END
  END src_d[510]
  PIN src_d[511]
    DIRECTION INPUT ;
    USE SIGNAL ;
    PORT
      LAYER M4 ;
        RECT  0 61.008 0.084 61.032 ;
    END
  END src_d[511]
  PIN src_d[512]
    DIRECTION INPUT ;
    USE SIGNAL ;
    PORT
      LAYER M4 ;
        RECT  0 61.104 0.084 61.128 ;
    END
  END src_d[512]
  PIN src_d[513]
    DIRECTION INPUT ;
    USE SIGNAL ;
    PORT
      LAYER M4 ;
        RECT  0 61.2 0.084 61.224 ;
    END
  END src_d[513]
  PIN src_d[514]
    DIRECTION INPUT ;
    USE SIGNAL ;
    PORT
      LAYER M4 ;
        RECT  0 61.296 0.084 61.32 ;
    END
  END src_d[514]
  PIN src_d[515]
    DIRECTION INPUT ;
    USE SIGNAL ;
    PORT
      LAYER M4 ;
        RECT  0 61.392 0.084 61.416 ;
    END
  END src_d[515]
  PIN src_d[516]
    DIRECTION INPUT ;
    USE SIGNAL ;
    PORT
      LAYER M4 ;
        RECT  0 61.488 0.084 61.512 ;
    END
  END src_d[516]
  PIN src_d[517]
    DIRECTION INPUT ;
    USE SIGNAL ;
    PORT
      LAYER M4 ;
        RECT  0 61.584 0.084 61.608 ;
    END
  END src_d[517]
  PIN src_d[518]
    DIRECTION INPUT ;
    USE SIGNAL ;
    PORT
      LAYER M4 ;
        RECT  0 61.68 0.084 61.704 ;
    END
  END src_d[518]
  PIN src_d[519]
    DIRECTION INPUT ;
    USE SIGNAL ;
    PORT
      LAYER M4 ;
        RECT  0 61.776 0.084 61.8 ;
    END
  END src_d[519]
  PIN src_d[51]
    DIRECTION INPUT ;
    USE SIGNAL ;
    PORT
      LAYER M4 ;
        RECT  0 56.016 0.084 56.04 ;
    END
  END src_d[51]
  PIN src_d[520]
    DIRECTION INPUT ;
    USE SIGNAL ;
    PORT
      LAYER M4 ;
        RECT  0 61.872 0.084 61.896 ;
    END
  END src_d[520]
  PIN src_d[521]
    DIRECTION INPUT ;
    USE SIGNAL ;
    PORT
      LAYER M4 ;
        RECT  0 61.968 0.084 61.992 ;
    END
  END src_d[521]
  PIN src_d[522]
    DIRECTION INPUT ;
    USE SIGNAL ;
    PORT
      LAYER M4 ;
        RECT  0 62.064 0.084 62.088 ;
    END
  END src_d[522]
  PIN src_d[523]
    DIRECTION INPUT ;
    USE SIGNAL ;
    PORT
      LAYER M4 ;
        RECT  0 62.16 0.084 62.184 ;
    END
  END src_d[523]
  PIN src_d[524]
    DIRECTION INPUT ;
    USE SIGNAL ;
    PORT
      LAYER M4 ;
        RECT  0 62.256 0.084 62.28 ;
    END
  END src_d[524]
  PIN src_d[525]
    DIRECTION INPUT ;
    USE SIGNAL ;
    PORT
      LAYER M4 ;
        RECT  0 62.352 0.084 62.376 ;
    END
  END src_d[525]
  PIN src_d[526]
    DIRECTION INPUT ;
    USE SIGNAL ;
    PORT
      LAYER M4 ;
        RECT  0 62.448 0.084 62.472 ;
    END
  END src_d[526]
  PIN src_d[527]
    DIRECTION INPUT ;
    USE SIGNAL ;
    PORT
      LAYER M4 ;
        RECT  0 62.544 0.084 62.568 ;
    END
  END src_d[527]
  PIN src_d[528]
    DIRECTION INPUT ;
    USE SIGNAL ;
    PORT
      LAYER M4 ;
        RECT  0 62.64 0.084 62.664 ;
    END
  END src_d[528]
  PIN src_d[529]
    DIRECTION INPUT ;
    USE SIGNAL ;
    PORT
      LAYER M4 ;
        RECT  0 62.736 0.084 62.76 ;
    END
  END src_d[529]
  PIN src_d[52]
    DIRECTION INPUT ;
    USE SIGNAL ;
    PORT
      LAYER M4 ;
        RECT  0 56.112 0.084 56.136 ;
    END
  END src_d[52]
  PIN src_d[530]
    DIRECTION INPUT ;
    USE SIGNAL ;
    PORT
      LAYER M4 ;
        RECT  0 62.832 0.084 62.856 ;
    END
  END src_d[530]
  PIN src_d[531]
    DIRECTION INPUT ;
    USE SIGNAL ;
    PORT
      LAYER M4 ;
        RECT  0 62.928 0.084 62.952 ;
    END
  END src_d[531]
  PIN src_d[532]
    DIRECTION INPUT ;
    USE SIGNAL ;
    PORT
      LAYER M4 ;
        RECT  0 63.024 0.084 63.048 ;
    END
  END src_d[532]
  PIN src_d[533]
    DIRECTION INPUT ;
    USE SIGNAL ;
    PORT
      LAYER M4 ;
        RECT  0 63.12 0.084 63.144 ;
    END
  END src_d[533]
  PIN src_d[534]
    DIRECTION INPUT ;
    USE SIGNAL ;
    PORT
      LAYER M4 ;
        RECT  0 63.216 0.084 63.24 ;
    END
  END src_d[534]
  PIN src_d[535]
    DIRECTION INPUT ;
    USE SIGNAL ;
    PORT
      LAYER M4 ;
        RECT  0 63.312 0.084 63.336 ;
    END
  END src_d[535]
  PIN src_d[536]
    DIRECTION INPUT ;
    USE SIGNAL ;
    PORT
      LAYER M4 ;
        RECT  0 63.408 0.084 63.432 ;
    END
  END src_d[536]
  PIN src_d[537]
    DIRECTION INPUT ;
    USE SIGNAL ;
    PORT
      LAYER M4 ;
        RECT  0 63.504 0.084 63.528 ;
    END
  END src_d[537]
  PIN src_d[538]
    DIRECTION INPUT ;
    USE SIGNAL ;
    PORT
      LAYER M4 ;
        RECT  0 63.6 0.084 63.624 ;
    END
  END src_d[538]
  PIN src_d[539]
    DIRECTION INPUT ;
    USE SIGNAL ;
    PORT
      LAYER M4 ;
        RECT  0 63.696 0.084 63.72 ;
    END
  END src_d[539]
  PIN src_d[53]
    DIRECTION INPUT ;
    USE SIGNAL ;
    PORT
      LAYER M4 ;
        RECT  0 56.208 0.084 56.232 ;
    END
  END src_d[53]
  PIN src_d[540]
    DIRECTION INPUT ;
    USE SIGNAL ;
    PORT
      LAYER M4 ;
        RECT  0 63.792 0.084 63.816 ;
    END
  END src_d[540]
  PIN src_d[541]
    DIRECTION INPUT ;
    USE SIGNAL ;
    PORT
      LAYER M4 ;
        RECT  0 63.888 0.084 63.912 ;
    END
  END src_d[541]
  PIN src_d[542]
    DIRECTION INPUT ;
    USE SIGNAL ;
    PORT
      LAYER M4 ;
        RECT  0 63.984 0.084 64.008 ;
    END
  END src_d[542]
  PIN src_d[543]
    DIRECTION INPUT ;
    USE SIGNAL ;
    PORT
      LAYER M4 ;
        RECT  0 22.32 0.084 22.344 ;
    END
  END src_d[543]
  PIN src_d[544]
    DIRECTION INPUT ;
    USE SIGNAL ;
    PORT
      LAYER M4 ;
        RECT  0 22.416 0.084 22.44 ;
    END
  END src_d[544]
  PIN src_d[54]
    DIRECTION INPUT ;
    USE SIGNAL ;
    PORT
      LAYER M4 ;
        RECT  0 56.304 0.084 56.328 ;
    END
  END src_d[54]
  PIN src_d[55]
    DIRECTION INPUT ;
    USE SIGNAL ;
    PORT
      LAYER M4 ;
        RECT  0 56.4 0.084 56.424 ;
    END
  END src_d[55]
  PIN src_d[56]
    DIRECTION INPUT ;
    USE SIGNAL ;
    PORT
      LAYER M4 ;
        RECT  0 56.496 0.084 56.52 ;
    END
  END src_d[56]
  PIN src_d[57]
    DIRECTION INPUT ;
    USE SIGNAL ;
    PORT
      LAYER M4 ;
        RECT  0 56.592 0.084 56.616 ;
    END
  END src_d[57]
  PIN src_d[58]
    DIRECTION INPUT ;
    USE SIGNAL ;
    PORT
      LAYER M4 ;
        RECT  0 56.688 0.084 56.712 ;
    END
  END src_d[58]
  PIN src_d[59]
    DIRECTION INPUT ;
    USE SIGNAL ;
    PORT
      LAYER M4 ;
        RECT  0 56.784 0.084 56.808 ;
    END
  END src_d[59]
  PIN src_d[5]
    DIRECTION INPUT ;
    USE SIGNAL ;
    PORT
      LAYER M4 ;
        RECT  0 42.384 0.084 42.408 ;
    END
  END src_d[5]
  PIN src_d[60]
    DIRECTION INPUT ;
    USE SIGNAL ;
    PORT
      LAYER M4 ;
        RECT  0 56.88 0.084 56.904 ;
    END
  END src_d[60]
  PIN src_d[61]
    DIRECTION INPUT ;
    USE SIGNAL ;
    PORT
      LAYER M4 ;
        RECT  0 56.976 0.084 57 ;
    END
  END src_d[61]
  PIN src_d[62]
    DIRECTION INPUT ;
    USE SIGNAL ;
    PORT
      LAYER M4 ;
        RECT  0 57.072 0.084 57.096 ;
    END
  END src_d[62]
  PIN src_d[63]
    DIRECTION INPUT ;
    USE SIGNAL ;
    PORT
      LAYER M4 ;
        RECT  0 47.952 0.084 47.976 ;
    END
  END src_d[63]
  PIN src_d[64]
    DIRECTION INPUT ;
    USE SIGNAL ;
    PORT
      LAYER M4 ;
        RECT  0 48.048 0.084 48.072 ;
    END
  END src_d[64]
  PIN src_d[65]
    DIRECTION INPUT ;
    USE SIGNAL ;
    PORT
      LAYER M4 ;
        RECT  0 48.144 0.084 48.168 ;
    END
  END src_d[65]
  PIN src_d[66]
    DIRECTION INPUT ;
    USE SIGNAL ;
    PORT
      LAYER M4 ;
        RECT  0 48.24 0.084 48.264 ;
    END
  END src_d[66]
  PIN src_d[67]
    DIRECTION INPUT ;
    USE SIGNAL ;
    PORT
      LAYER M4 ;
        RECT  0 48.336 0.084 48.36 ;
    END
  END src_d[67]
  PIN src_d[68]
    DIRECTION INPUT ;
    USE SIGNAL ;
    PORT
      LAYER M4 ;
        RECT  0 48.432 0.084 48.456 ;
    END
  END src_d[68]
  PIN src_d[69]
    DIRECTION INPUT ;
    USE SIGNAL ;
    PORT
      LAYER M4 ;
        RECT  0 48.528 0.084 48.552 ;
    END
  END src_d[69]
  PIN src_d[6]
    DIRECTION INPUT ;
    USE SIGNAL ;
    PORT
      LAYER M4 ;
        RECT  0 42.48 0.084 42.504 ;
    END
  END src_d[6]
  PIN src_d[70]
    DIRECTION INPUT ;
    USE SIGNAL ;
    PORT
      LAYER M4 ;
        RECT  0 48.624 0.084 48.648 ;
    END
  END src_d[70]
  PIN src_d[71]
    DIRECTION INPUT ;
    USE SIGNAL ;
    PORT
      LAYER M4 ;
        RECT  0 48.72 0.084 48.744 ;
    END
  END src_d[71]
  PIN src_d[72]
    DIRECTION INPUT ;
    USE SIGNAL ;
    PORT
      LAYER M4 ;
        RECT  0 48.816 0.084 48.84 ;
    END
  END src_d[72]
  PIN src_d[73]
    DIRECTION INPUT ;
    USE SIGNAL ;
    PORT
      LAYER M4 ;
        RECT  0 48.912 0.084 48.936 ;
    END
  END src_d[73]
  PIN src_d[74]
    DIRECTION INPUT ;
    USE SIGNAL ;
    PORT
      LAYER M4 ;
        RECT  0 49.008 0.084 49.032 ;
    END
  END src_d[74]
  PIN src_d[75]
    DIRECTION INPUT ;
    USE SIGNAL ;
    PORT
      LAYER M4 ;
        RECT  0 49.104 0.084 49.128 ;
    END
  END src_d[75]
  PIN src_d[76]
    DIRECTION INPUT ;
    USE SIGNAL ;
    PORT
      LAYER M4 ;
        RECT  0 49.2 0.084 49.224 ;
    END
  END src_d[76]
  PIN src_d[77]
    DIRECTION INPUT ;
    USE SIGNAL ;
    PORT
      LAYER M4 ;
        RECT  0 49.296 0.084 49.32 ;
    END
  END src_d[77]
  PIN src_d[78]
    DIRECTION INPUT ;
    USE SIGNAL ;
    PORT
      LAYER M4 ;
        RECT  0 49.392 0.084 49.416 ;
    END
  END src_d[78]
  PIN src_d[79]
    DIRECTION INPUT ;
    USE SIGNAL ;
    PORT
      LAYER M4 ;
        RECT  0 49.488 0.084 49.512 ;
    END
  END src_d[79]
  PIN src_d[7]
    DIRECTION INPUT ;
    USE SIGNAL ;
    PORT
      LAYER M4 ;
        RECT  0 42.576 0.084 42.6 ;
    END
  END src_d[7]
  PIN src_d[80]
    DIRECTION INPUT ;
    USE SIGNAL ;
    PORT
      LAYER M4 ;
        RECT  0 49.584 0.084 49.608 ;
    END
  END src_d[80]
  PIN src_d[81]
    DIRECTION INPUT ;
    USE SIGNAL ;
    PORT
      LAYER M4 ;
        RECT  0 49.68 0.084 49.704 ;
    END
  END src_d[81]
  PIN src_d[82]
    DIRECTION INPUT ;
    USE SIGNAL ;
    PORT
      LAYER M4 ;
        RECT  0 49.776 0.084 49.8 ;
    END
  END src_d[82]
  PIN src_d[83]
    DIRECTION INPUT ;
    USE SIGNAL ;
    PORT
      LAYER M4 ;
        RECT  0 49.872 0.084 49.896 ;
    END
  END src_d[83]
  PIN src_d[84]
    DIRECTION INPUT ;
    USE SIGNAL ;
    PORT
      LAYER M4 ;
        RECT  0 49.968 0.084 49.992 ;
    END
  END src_d[84]
  PIN src_d[85]
    DIRECTION INPUT ;
    USE SIGNAL ;
    PORT
      LAYER M4 ;
        RECT  0 50.064 0.084 50.088 ;
    END
  END src_d[85]
  PIN src_d[86]
    DIRECTION INPUT ;
    USE SIGNAL ;
    PORT
      LAYER M4 ;
        RECT  0 50.16 0.084 50.184 ;
    END
  END src_d[86]
  PIN src_d[87]
    DIRECTION INPUT ;
    USE SIGNAL ;
    PORT
      LAYER M4 ;
        RECT  0 50.256 0.084 50.28 ;
    END
  END src_d[87]
  PIN src_d[88]
    DIRECTION INPUT ;
    USE SIGNAL ;
    PORT
      LAYER M4 ;
        RECT  0 50.352 0.084 50.376 ;
    END
  END src_d[88]
  PIN src_d[89]
    DIRECTION INPUT ;
    USE SIGNAL ;
    PORT
      LAYER M4 ;
        RECT  0 50.448 0.084 50.472 ;
    END
  END src_d[89]
  PIN src_d[8]
    DIRECTION INPUT ;
    USE SIGNAL ;
    PORT
      LAYER M4 ;
        RECT  0 42.672 0.084 42.696 ;
    END
  END src_d[8]
  PIN src_d[90]
    DIRECTION INPUT ;
    USE SIGNAL ;
    PORT
      LAYER M4 ;
        RECT  0 50.544 0.084 50.568 ;
    END
  END src_d[90]
  PIN src_d[91]
    DIRECTION INPUT ;
    USE SIGNAL ;
    PORT
      LAYER M4 ;
        RECT  0 50.64 0.084 50.664 ;
    END
  END src_d[91]
  PIN src_d[92]
    DIRECTION INPUT ;
    USE SIGNAL ;
    PORT
      LAYER M4 ;
        RECT  0 50.736 0.084 50.76 ;
    END
  END src_d[92]
  PIN src_d[93]
    DIRECTION INPUT ;
    USE SIGNAL ;
    PORT
      LAYER M4 ;
        RECT  0 50.832 0.084 50.856 ;
    END
  END src_d[93]
  PIN src_d[94]
    DIRECTION INPUT ;
    USE SIGNAL ;
    PORT
      LAYER M4 ;
        RECT  0 50.928 0.084 50.952 ;
    END
  END src_d[94]
  PIN src_d[95]
    DIRECTION INPUT ;
    USE SIGNAL ;
    PORT
      LAYER M4 ;
        RECT  0 51.024 0.084 51.048 ;
    END
  END src_d[95]
  PIN src_d[96]
    DIRECTION INPUT ;
    USE SIGNAL ;
    PORT
      LAYER M4 ;
        RECT  0 51.12 0.084 51.144 ;
    END
  END src_d[96]
  PIN src_d[97]
    DIRECTION INPUT ;
    USE SIGNAL ;
    PORT
      LAYER M4 ;
        RECT  0 51.216 0.084 51.24 ;
    END
  END src_d[97]
  PIN src_d[98]
    DIRECTION INPUT ;
    USE SIGNAL ;
    PORT
      LAYER M4 ;
        RECT  0 51.312 0.084 51.336 ;
    END
  END src_d[98]
  PIN src_d[99]
    DIRECTION INPUT ;
    USE SIGNAL ;
    PORT
      LAYER M4 ;
        RECT  0 51.408 0.084 51.432 ;
    END
  END src_d[99]
  PIN src_d[9]
    DIRECTION INPUT ;
    USE SIGNAL ;
    PORT
      LAYER M4 ;
        RECT  0 42.768 0.084 42.792 ;
    END
  END src_d[9]
  PIN src_v[0]
    DIRECTION INPUT ;
    USE SIGNAL ;
    PORT
      LAYER M4 ;
        RECT  0 22.512 0.084 22.536 ;
    END
  END src_v[0]
  PIN VDD
    DIRECTION INOUT ;
    USE POWER ;
    PORT
      LAYER M5 ;
        RECT  13.392 2.151 13.512 97.209 ;
        RECT  7.992 2.151 8.112 97.209 ;
        RECT  2.592 2.151 2.712 97.209 ;
    END
  END VDD
  PIN VSS
    DIRECTION INOUT ;
    USE GROUND ;
    PORT
      LAYER M5 ;
        RECT  13.2 2.137 13.32 97.223 ;
        RECT  7.8 2.137 7.92 97.223 ;
        RECT  2.4 2.137 2.52 97.223 ;
    END
  END VSS
  OBS
    LAYER RVTN ;
     RECT  2.16 2.16 15.12 2.295 ;
     RECT  2.16 2.565 15.12 2.835 ;
     RECT  2.16 3.105 15.12 3.375 ;
     RECT  2.16 3.645 15.12 3.915 ;
     RECT  2.16 4.185 15.12 4.455 ;
     RECT  2.16 4.725 15.12 4.995 ;
     RECT  2.16 5.265 15.12 5.535 ;
     RECT  2.16 5.805 15.12 6.075 ;
     RECT  2.16 6.345 15.12 6.615 ;
     RECT  2.16 6.885 15.12 7.155 ;
     RECT  2.16 7.425 15.12 7.695 ;
     RECT  2.16 7.965 15.12 8.235 ;
     RECT  2.16 8.505 15.12 8.775 ;
     RECT  2.16 9.045 15.12 9.315 ;
     RECT  2.16 9.585 15.12 9.855 ;
     RECT  2.16 10.125 15.12 10.395 ;
     RECT  2.16 10.665 15.12 10.935 ;
     RECT  2.16 11.205 15.12 11.475 ;
     RECT  2.16 11.745 15.12 12.015 ;
     RECT  2.16 12.285 15.12 12.555 ;
     RECT  2.16 12.825 15.12 13.095 ;
     RECT  2.16 13.365 15.12 13.635 ;
     RECT  2.16 13.905 15.12 14.175 ;
     RECT  2.16 14.445 15.12 14.715 ;
     RECT  2.16 14.985 15.12 15.255 ;
     RECT  2.16 15.525 15.12 15.795 ;
     RECT  2.16 16.065 15.12 16.335 ;
     RECT  2.16 16.605 15.12 16.875 ;
     RECT  2.16 17.145 15.12 17.415 ;
     RECT  2.16 17.685 15.12 17.955 ;
     RECT  2.16 18.225 15.12 18.495 ;
     RECT  2.16 18.765 15.12 19.035 ;
     RECT  2.16 19.305 15.12 19.575 ;
     RECT  2.16 19.845 15.12 20.115 ;
     RECT  2.16 20.385 15.12 20.655 ;
     RECT  2.16 20.925 15.12 21.195 ;
     RECT  2.16 21.465 15.12 21.735 ;
     RECT  2.16 22.005 15.12 22.275 ;
     RECT  2.16 22.545 15.12 22.815 ;
     RECT  2.16 23.085 15.12 23.355 ;
     RECT  2.16 23.625 15.12 23.895 ;
     RECT  2.16 24.165 15.12 24.435 ;
     RECT  2.16 24.705 15.12 24.975 ;
     RECT  2.16 25.245 15.12 25.515 ;
     RECT  2.16 25.785 15.12 26.055 ;
     RECT  2.16 26.325 15.12 26.595 ;
     RECT  2.16 26.865 15.12 27.135 ;
     RECT  2.16 27.405 15.12 27.675 ;
     RECT  2.16 27.945 15.12 28.215 ;
     RECT  2.16 28.485 15.12 28.755 ;
     RECT  2.16 29.025 15.12 29.295 ;
     RECT  2.16 29.565 15.12 29.835 ;
     RECT  2.16 30.105 15.12 30.375 ;
     RECT  2.16 30.645 15.12 30.915 ;
     RECT  2.16 31.185 15.12 31.455 ;
     RECT  2.16 31.725 15.12 31.995 ;
     RECT  2.16 32.265 15.12 32.535 ;
     RECT  2.16 32.805 15.12 33.075 ;
     RECT  2.16 33.345 15.12 33.615 ;
     RECT  2.16 33.885 15.12 34.155 ;
     RECT  2.16 34.425 15.12 34.695 ;
     RECT  2.16 34.965 15.12 35.235 ;
     RECT  2.16 35.505 15.12 35.775 ;
     RECT  2.16 36.045 15.12 36.315 ;
     RECT  2.16 36.585 15.12 36.855 ;
     RECT  2.16 37.125 15.12 37.395 ;
     RECT  2.16 37.665 15.12 37.935 ;
     RECT  2.16 38.205 15.12 38.475 ;
     RECT  2.16 38.745 15.12 39.015 ;
     RECT  2.16 39.285 15.12 39.555 ;
     RECT  2.16 39.825 15.12 40.095 ;
     RECT  2.16 40.365 15.12 40.635 ;
     RECT  2.16 40.905 15.12 41.175 ;
     RECT  2.16 41.445 15.12 41.715 ;
     RECT  2.16 41.985 15.12 42.255 ;
     RECT  2.16 42.525 15.12 42.795 ;
     RECT  2.16 43.065 15.12 43.335 ;
     RECT  2.16 43.605 15.12 43.875 ;
     RECT  2.16 44.145 15.12 44.415 ;
     RECT  2.16 44.685 15.12 44.955 ;
     RECT  2.16 45.225 15.12 45.495 ;
     RECT  2.16 45.765 15.12 46.035 ;
     RECT  2.16 46.305 15.12 46.575 ;
     RECT  2.16 46.845 15.12 47.115 ;
     RECT  2.16 47.385 15.12 47.655 ;
     RECT  2.16 47.925 15.12 48.195 ;
     RECT  2.16 48.465 15.12 48.735 ;
     RECT  2.16 49.005 15.12 49.275 ;
     RECT  2.16 49.545 15.12 49.815 ;
     RECT  2.16 50.085 15.12 50.355 ;
     RECT  2.16 50.625 15.12 50.895 ;
     RECT  2.16 51.165 15.12 51.435 ;
     RECT  2.16 51.705 15.12 51.975 ;
     RECT  2.16 52.245 15.12 52.515 ;
     RECT  2.16 52.785 15.12 53.055 ;
     RECT  2.16 53.325 15.12 53.595 ;
     RECT  2.16 53.865 15.12 54.135 ;
     RECT  2.16 54.405 15.12 54.675 ;
     RECT  2.16 54.945 15.12 55.215 ;
     RECT  2.16 55.485 15.12 55.755 ;
     RECT  2.16 56.025 15.12 56.295 ;
     RECT  2.16 56.565 15.12 56.835 ;
     RECT  2.16 57.105 15.12 57.375 ;
     RECT  2.16 57.645 15.12 57.915 ;
     RECT  2.16 58.185 15.12 58.455 ;
     RECT  2.16 58.725 15.12 58.995 ;
     RECT  2.16 59.265 15.12 59.535 ;
     RECT  2.16 59.805 15.12 60.075 ;
     RECT  2.16 60.345 15.12 60.615 ;
     RECT  2.16 60.885 15.12 61.155 ;
     RECT  2.16 61.425 15.12 61.695 ;
     RECT  2.16 61.965 15.12 62.235 ;
     RECT  2.16 62.505 15.12 62.775 ;
     RECT  2.16 63.045 15.12 63.315 ;
     RECT  2.16 63.585 15.12 63.855 ;
     RECT  2.16 64.125 15.12 64.395 ;
     RECT  2.16 64.665 15.12 64.935 ;
     RECT  2.16 65.205 15.12 65.475 ;
     RECT  2.16 65.745 15.12 66.015 ;
     RECT  2.16 66.285 15.12 66.555 ;
     RECT  2.16 66.825 15.12 67.095 ;
     RECT  2.16 67.365 15.12 67.635 ;
     RECT  2.16 67.905 15.12 68.175 ;
     RECT  2.16 68.445 15.12 68.715 ;
     RECT  2.16 68.985 15.12 69.255 ;
     RECT  2.16 69.525 15.12 69.795 ;
     RECT  2.16 70.065 15.12 70.335 ;
     RECT  2.16 70.605 15.12 70.875 ;
     RECT  2.16 71.145 15.12 71.415 ;
     RECT  2.16 71.685 15.12 71.955 ;
     RECT  2.16 72.225 15.12 72.495 ;
     RECT  2.16 72.765 15.12 73.035 ;
     RECT  2.16 73.305 15.12 73.575 ;
     RECT  2.16 73.845 15.12 74.115 ;
     RECT  2.16 74.385 15.12 74.655 ;
     RECT  2.16 74.925 15.12 75.195 ;
     RECT  2.16 75.465 15.12 75.735 ;
     RECT  2.16 76.005 15.12 76.275 ;
     RECT  2.16 76.545 15.12 76.815 ;
     RECT  2.16 77.085 15.12 77.355 ;
     RECT  2.16 77.625 15.12 77.895 ;
     RECT  2.16 78.165 15.12 78.435 ;
     RECT  2.16 78.705 15.12 78.975 ;
     RECT  2.16 79.245 15.12 79.515 ;
     RECT  2.16 79.785 15.12 80.055 ;
     RECT  2.16 80.325 15.12 80.595 ;
     RECT  2.16 80.865 15.12 81.135 ;
     RECT  2.16 81.405 15.12 81.675 ;
     RECT  2.16 81.945 15.12 82.215 ;
     RECT  2.16 82.485 15.12 82.755 ;
     RECT  2.16 83.025 15.12 83.295 ;
     RECT  2.16 83.565 15.12 83.835 ;
     RECT  2.16 84.105 15.12 84.375 ;
     RECT  2.16 84.645 15.12 84.915 ;
     RECT  2.16 85.185 15.12 85.455 ;
     RECT  2.16 85.725 15.12 85.995 ;
     RECT  2.16 86.265 15.12 86.535 ;
     RECT  2.16 86.805 15.12 87.075 ;
     RECT  2.16 87.345 15.12 87.615 ;
     RECT  2.16 87.885 15.12 88.155 ;
     RECT  2.16 88.425 15.12 88.695 ;
     RECT  2.16 88.965 15.12 89.235 ;
     RECT  2.16 89.505 15.12 89.775 ;
     RECT  2.16 90.045 15.12 90.315 ;
     RECT  2.16 90.585 15.12 90.855 ;
     RECT  2.16 91.125 15.12 91.395 ;
     RECT  2.16 91.665 15.12 91.935 ;
     RECT  2.16 92.205 15.12 92.475 ;
     RECT  2.16 92.745 15.12 93.015 ;
     RECT  2.16 93.285 15.12 93.555 ;
     RECT  2.16 93.825 15.12 94.095 ;
     RECT  2.16 94.365 15.12 94.635 ;
     RECT  2.16 94.905 15.12 95.175 ;
     RECT  2.16 95.445 15.12 95.715 ;
     RECT  2.16 95.985 15.12 96.255 ;
     RECT  2.16 96.525 15.12 96.795 ;
     RECT  2.16 97.065 15.12 97.2 ;
    LAYER RVTP ;
     RECT  2.16 2.295 15.12 2.565 ;
     RECT  2.16 2.835 15.12 3.105 ;
     RECT  2.16 3.375 15.12 3.645 ;
     RECT  2.16 3.915 15.12 4.185 ;
     RECT  2.16 4.455 15.12 4.725 ;
     RECT  2.16 4.995 15.12 5.265 ;
     RECT  2.16 5.535 15.12 5.805 ;
     RECT  2.16 6.075 15.12 6.345 ;
     RECT  2.16 6.615 15.12 6.885 ;
     RECT  2.16 7.155 15.12 7.425 ;
     RECT  2.16 7.695 15.12 7.965 ;
     RECT  2.16 8.235 15.12 8.505 ;
     RECT  2.16 8.775 15.12 9.045 ;
     RECT  2.16 9.315 15.12 9.585 ;
     RECT  2.16 9.855 15.12 10.125 ;
     RECT  2.16 10.395 15.12 10.665 ;
     RECT  2.16 10.935 15.12 11.205 ;
     RECT  2.16 11.475 15.12 11.745 ;
     RECT  2.16 12.015 15.12 12.285 ;
     RECT  2.16 12.555 15.12 12.825 ;
     RECT  2.16 13.095 15.12 13.365 ;
     RECT  2.16 13.635 15.12 13.905 ;
     RECT  2.16 14.175 15.12 14.445 ;
     RECT  2.16 14.715 15.12 14.985 ;
     RECT  2.16 15.255 15.12 15.525 ;
     RECT  2.16 15.795 15.12 16.065 ;
     RECT  2.16 16.335 15.12 16.605 ;
     RECT  2.16 16.875 15.12 17.145 ;
     RECT  2.16 17.415 15.12 17.685 ;
     RECT  2.16 17.955 15.12 18.225 ;
     RECT  2.16 18.495 15.12 18.765 ;
     RECT  2.16 19.035 15.12 19.305 ;
     RECT  2.16 19.575 15.12 19.845 ;
     RECT  2.16 20.115 15.12 20.385 ;
     RECT  2.16 20.655 15.12 20.925 ;
     RECT  2.16 21.195 15.12 21.465 ;
     RECT  2.16 21.735 15.12 22.005 ;
     RECT  2.16 22.275 15.12 22.545 ;
     RECT  2.16 22.815 15.12 23.085 ;
     RECT  2.16 23.355 15.12 23.625 ;
     RECT  2.16 23.895 15.12 24.165 ;
     RECT  2.16 24.435 15.12 24.705 ;
     RECT  2.16 24.975 15.12 25.245 ;
     RECT  2.16 25.515 15.12 25.785 ;
     RECT  2.16 26.055 15.12 26.325 ;
     RECT  2.16 26.595 15.12 26.865 ;
     RECT  2.16 27.135 15.12 27.405 ;
     RECT  2.16 27.675 15.12 27.945 ;
     RECT  2.16 28.215 15.12 28.485 ;
     RECT  2.16 28.755 15.12 29.025 ;
     RECT  2.16 29.295 15.12 29.565 ;
     RECT  2.16 29.835 15.12 30.105 ;
     RECT  2.16 30.375 15.12 30.645 ;
     RECT  2.16 30.915 15.12 31.185 ;
     RECT  2.16 31.455 15.12 31.725 ;
     RECT  2.16 31.995 15.12 32.265 ;
     RECT  2.16 32.535 15.12 32.805 ;
     RECT  2.16 33.075 15.12 33.345 ;
     RECT  2.16 33.615 15.12 33.885 ;
     RECT  2.16 34.155 15.12 34.425 ;
     RECT  2.16 34.695 15.12 34.965 ;
     RECT  2.16 35.235 15.12 35.505 ;
     RECT  2.16 35.775 15.12 36.045 ;
     RECT  2.16 36.315 15.12 36.585 ;
     RECT  2.16 36.855 15.12 37.125 ;
     RECT  2.16 37.395 15.12 37.665 ;
     RECT  2.16 37.935 15.12 38.205 ;
     RECT  2.16 38.475 15.12 38.745 ;
     RECT  2.16 39.015 15.12 39.285 ;
     RECT  2.16 39.555 15.12 39.825 ;
     RECT  2.16 40.095 15.12 40.365 ;
     RECT  2.16 40.635 15.12 40.905 ;
     RECT  2.16 41.175 15.12 41.445 ;
     RECT  2.16 41.715 15.12 41.985 ;
     RECT  2.16 42.255 15.12 42.525 ;
     RECT  2.16 42.795 15.12 43.065 ;
     RECT  2.16 43.335 15.12 43.605 ;
     RECT  2.16 43.875 15.12 44.145 ;
     RECT  2.16 44.415 15.12 44.685 ;
     RECT  2.16 44.955 15.12 45.225 ;
     RECT  2.16 45.495 15.12 45.765 ;
     RECT  2.16 46.035 15.12 46.305 ;
     RECT  2.16 46.575 15.12 46.845 ;
     RECT  2.16 47.115 15.12 47.385 ;
     RECT  2.16 47.655 15.12 47.925 ;
     RECT  2.16 48.195 15.12 48.465 ;
     RECT  2.16 48.735 15.12 49.005 ;
     RECT  2.16 49.275 15.12 49.545 ;
     RECT  2.16 49.815 15.12 50.085 ;
     RECT  2.16 50.355 15.12 50.625 ;
     RECT  2.16 50.895 15.12 51.165 ;
     RECT  2.16 51.435 15.12 51.705 ;
     RECT  2.16 51.975 15.12 52.245 ;
     RECT  2.16 52.515 15.12 52.785 ;
     RECT  2.16 53.055 15.12 53.325 ;
     RECT  2.16 53.595 15.12 53.865 ;
     RECT  2.16 54.135 15.12 54.405 ;
     RECT  2.16 54.675 15.12 54.945 ;
     RECT  2.16 55.215 15.12 55.485 ;
     RECT  2.16 55.755 15.12 56.025 ;
     RECT  2.16 56.295 15.12 56.565 ;
     RECT  2.16 56.835 15.12 57.105 ;
     RECT  2.16 57.375 15.12 57.645 ;
     RECT  2.16 57.915 15.12 58.185 ;
     RECT  2.16 58.455 15.12 58.725 ;
     RECT  2.16 58.995 15.12 59.265 ;
     RECT  2.16 59.535 15.12 59.805 ;
     RECT  2.16 60.075 15.12 60.345 ;
     RECT  2.16 60.615 15.12 60.885 ;
     RECT  2.16 61.155 15.12 61.425 ;
     RECT  2.16 61.695 15.12 61.965 ;
     RECT  2.16 62.235 15.12 62.505 ;
     RECT  2.16 62.775 15.12 63.045 ;
     RECT  2.16 63.315 15.12 63.585 ;
     RECT  2.16 63.855 15.12 64.125 ;
     RECT  2.16 64.395 15.12 64.665 ;
     RECT  2.16 64.935 15.12 65.205 ;
     RECT  2.16 65.475 15.12 65.745 ;
     RECT  2.16 66.015 15.12 66.285 ;
     RECT  2.16 66.555 15.12 66.825 ;
     RECT  2.16 67.095 15.12 67.365 ;
     RECT  2.16 67.635 15.12 67.905 ;
     RECT  2.16 68.175 15.12 68.445 ;
     RECT  2.16 68.715 15.12 68.985 ;
     RECT  2.16 69.255 15.12 69.525 ;
     RECT  2.16 69.795 15.12 70.065 ;
     RECT  2.16 70.335 15.12 70.605 ;
     RECT  2.16 70.875 15.12 71.145 ;
     RECT  2.16 71.415 15.12 71.685 ;
     RECT  2.16 71.955 15.12 72.225 ;
     RECT  2.16 72.495 15.12 72.765 ;
     RECT  2.16 73.035 15.12 73.305 ;
     RECT  2.16 73.575 15.12 73.845 ;
     RECT  2.16 74.115 15.12 74.385 ;
     RECT  2.16 74.655 15.12 74.925 ;
     RECT  2.16 75.195 15.12 75.465 ;
     RECT  2.16 75.735 15.12 76.005 ;
     RECT  2.16 76.275 15.12 76.545 ;
     RECT  2.16 76.815 15.12 77.085 ;
     RECT  2.16 77.355 15.12 77.625 ;
     RECT  2.16 77.895 15.12 78.165 ;
     RECT  2.16 78.435 15.12 78.705 ;
     RECT  2.16 78.975 15.12 79.245 ;
     RECT  2.16 79.515 15.12 79.785 ;
     RECT  2.16 80.055 15.12 80.325 ;
     RECT  2.16 80.595 15.12 80.865 ;
     RECT  2.16 81.135 15.12 81.405 ;
     RECT  2.16 81.675 15.12 81.945 ;
     RECT  2.16 82.215 15.12 82.485 ;
     RECT  2.16 82.755 15.12 83.025 ;
     RECT  2.16 83.295 15.12 83.565 ;
     RECT  2.16 83.835 15.12 84.105 ;
     RECT  2.16 84.375 15.12 84.645 ;
     RECT  2.16 84.915 15.12 85.185 ;
     RECT  2.16 85.455 15.12 85.725 ;
     RECT  2.16 85.995 15.12 86.265 ;
     RECT  2.16 86.535 15.12 86.805 ;
     RECT  2.16 87.075 15.12 87.345 ;
     RECT  2.16 87.615 15.12 87.885 ;
     RECT  2.16 88.155 15.12 88.425 ;
     RECT  2.16 88.695 15.12 88.965 ;
     RECT  2.16 89.235 15.12 89.505 ;
     RECT  2.16 89.775 15.12 90.045 ;
     RECT  2.16 90.315 15.12 90.585 ;
     RECT  2.16 90.855 15.12 91.125 ;
     RECT  2.16 91.395 15.12 91.665 ;
     RECT  2.16 91.935 15.12 92.205 ;
     RECT  2.16 92.475 15.12 92.745 ;
     RECT  2.16 93.015 15.12 93.285 ;
     RECT  2.16 93.555 15.12 93.825 ;
     RECT  2.16 94.095 15.12 94.365 ;
     RECT  2.16 94.635 15.12 94.905 ;
     RECT  2.16 95.175 15.12 95.445 ;
     RECT  2.16 95.715 15.12 95.985 ;
     RECT  2.16 96.255 15.12 96.525 ;
     RECT  2.16 96.795 15.12 97.065 ;
    LAYER M1 ;
     RECT  2.16 2.151 15.12 97.209 ;
    LAYER M2 ;
     RECT  0.103 21.51 0.139 21.528 ;
     RECT  0.103 37.602 0.139 37.62 ;
     RECT  0.103 57.852 0.139 58.284 ;
     RECT  0.103 59.076 0.139 59.094 ;
     RECT  0.103 61.632 0.139 61.65 ;
     RECT  0.103 62.442 0.139 62.46 ;
     RECT  0.103 63.792 0.139 63.81 ;
     RECT  0.103 64.944 0.139 65.43 ;
     RECT  0.139 21.132 0.175 21.528 ;
     RECT  0.103 28.458 0.175 28.476 ;
     RECT  0.103 32.472 0.175 33.066 ;
     RECT  0.103 34.092 0.175 34.524 ;
     RECT  0.139 63.792 0.175 63.846 ;
     RECT  0.103 39.492 0.203 40.239 ;
     RECT  0.175 21.132 0.211 21.798 ;
     RECT  0.103 22.788 0.211 22.806 ;
     RECT  0.175 32.472 0.211 34.524 ;
     RECT  0.103 60.822 0.211 60.84 ;
     RECT  0.139 61.632 0.211 62.46 ;
     RECT  0.139 37.566 0.283 37.62 ;
     RECT  0.175 63.792 0.283 64.08 ;
     RECT  0.103 30.186 0.319 30.204 ;
     RECT  0.211 32.472 0.319 34.92 ;
     RECT  0.175 68.112 0.319 68.13 ;
     RECT  0.319 30.186 0.391 30.87 ;
     RECT  0.103 67.104 0.427 67.122 ;
     RECT  0.319 68.112 0.427 68.742 ;
     RECT  0.211 21.132 0.463 22.806 ;
     RECT  0.103 23.904 0.463 24.498 ;
     RECT  0.427 29.304 0.463 29.322 ;
     RECT  0.427 67.104 0.463 68.742 ;
     RECT  0.103 69.498 0.463 70.02 ;
     RECT  0.319 32.472 0.499 35.334 ;
     RECT  0.103 72.81 0.499 72.828 ;
     RECT  0.175 28.224 0.535 28.476 ;
     RECT  0.463 29.304 0.535 29.394 ;
     RECT  0.391 30.186 0.535 31.284 ;
     RECT  0.499 32.391 0.535 35.334 ;
     RECT  0.103 71.154 0.535 71.748 ;
     RECT  0.499 72.81 0.535 73.134 ;
     RECT  0.103 75.708 0.599 75.726 ;
     RECT  0.211 60.822 0.751 62.46 ;
     RECT  0.283 63.594 0.751 64.08 ;
     RECT  0.715 40.266 0.823 40.698 ;
     RECT  0.751 41.454 0.823 41.472 ;
     RECT  0.283 36.396 0.895 38.034 ;
     RECT  0.895 36.396 0.931 38.502 ;
     RECT  0.203 39.492 0.931 39.51 ;
     RECT  0.139 64.944 0.931 66.042 ;
     RECT  0.463 67.104 0.931 70.02 ;
     RECT  0.535 28.224 1.039 28.512 ;
     RECT  0.931 36.396 1.327 39.51 ;
     RECT  0.751 60.822 1.327 64.08 ;
     RECT  0.535 29.304 1.435 35.334 ;
     RECT  1.327 36.36 1.435 39.51 ;
     RECT  1.327 60.696 1.471 64.08 ;
     RECT  0.931 64.944 1.471 70.02 ;
     RECT  1.471 60.696 1.615 70.02 ;
     RECT  1.615 60.696 1.651 70.398 ;
     RECT  0.535 71.154 1.651 73.134 ;
     RECT  0.103 51.372 1.687 51.39 ;
     RECT  1.291 45.774 1.759 45.792 ;
     RECT  0.103 46.62 1.759 46.638 ;
     RECT  1.291 47.394 1.759 47.412 ;
     RECT  0.247 48.78 1.759 48.798 ;
     RECT  1.651 60.696 1.759 73.134 ;
     RECT  1.759 42.732 1.795 42.75 ;
     RECT  1.759 44.424 1.795 45.792 ;
     RECT  1.759 46.62 1.795 47.412 ;
     RECT  1.759 57.006 1.795 57.024 ;
     RECT  0.139 57.852 1.795 59.094 ;
     RECT  1.687 51.372 1.867 51.732 ;
     RECT  0.103 52.992 1.867 53.01 ;
     RECT  0.211 55.8 1.867 55.818 ;
     RECT  1.795 57.006 1.867 59.094 ;
     RECT  1.759 60.552 1.903 73.134 ;
     RECT  1.867 57.006 1.939 59.562 ;
     RECT  1.903 60.471 1.939 73.134 ;
     RECT  0.463 21.132 2.16 24.498 ;
     RECT  1.039 27.72 2.16 28.512 ;
     RECT  1.435 29.304 2.16 39.51 ;
     RECT  0.823 40.266 2.16 41.472 ;
     RECT  1.795 42.732 2.16 43.128 ;
     RECT  1.795 44.424 2.16 47.412 ;
     RECT  1.759 48.204 2.16 48.798 ;
     RECT  0.103 49.554 2.16 49.572 ;
     RECT  1.867 51.372 2.16 51.93 ;
     RECT  1.867 52.992 2.16 53.352 ;
     RECT  1.867 55.152 2.16 56.088 ;
     RECT  1.939 57.006 2.16 73.134 ;
     RECT  0.571 77.166 2.16 77.184 ;
     RECT  0.103 78.102 2.16 78.12 ;
     RECT  2.16 2.151 15.12 97.209 ;
     RECT  15.12 20.736 15.287 52.434 ;
     RECT  15.287 22.626 15.359 52.434 ;
     RECT  15.359 22.788 15.395 52.434 ;
     RECT  15.12 95.112 15.431 95.13 ;
     RECT  15.12 18.738 15.683 19.836 ;
     RECT  15.12 80.766 15.683 80.784 ;
     RECT  15.12 53.298 15.899 79.074 ;
     RECT  15.395 22.896 15.971 52.434 ;
     RECT  15.899 58.5 15.971 79.074 ;
     RECT  15.287 20.736 16.007 21.492 ;
     RECT  15.971 32.814 16.007 52.434 ;
     RECT  15.971 58.536 16.007 76.734 ;
     RECT  15.971 22.896 16.115 31.914 ;
     RECT  16.115 22.896 16.187 24.264 ;
     RECT  15.683 19.35 16.259 19.836 ;
     RECT  16.007 58.626 16.259 76.734 ;
     RECT  16.259 19.746 16.295 19.836 ;
     RECT  16.187 23.094 16.331 24.264 ;
     RECT  16.007 20.736 16.367 21.294 ;
     RECT  15.971 77.67 16.403 79.074 ;
     RECT  16.259 58.626 16.439 75.924 ;
     RECT  16.259 76.716 16.439 76.734 ;
     RECT  16.115 25.326 16.475 31.914 ;
     RECT  16.007 33.354 16.475 52.434 ;
     RECT  16.439 72.396 16.475 75.924 ;
     RECT  16.403 78.21 16.475 79.074 ;
     RECT  16.475 25.326 16.511 27.36 ;
     RECT  16.475 28.386 16.511 28.818 ;
     RECT  16.475 33.354 16.511 37.728 ;
     RECT  16.475 38.646 16.511 52.434 ;
     RECT  16.439 58.626 16.511 71.604 ;
     RECT  16.475 72.936 16.511 74.034 ;
     RECT  16.475 75.096 16.511 75.114 ;
     RECT  16.475 75.906 16.511 75.924 ;
     RECT  16.475 78.21 16.511 78.624 ;
     RECT  16.331 23.094 16.547 23.112 ;
     RECT  16.511 28.8 16.547 28.818 ;
     RECT  16.475 30.726 16.547 31.914 ;
     RECT  16.511 33.93 16.547 35.424 ;
     RECT  16.511 36.396 16.547 37.728 ;
     RECT  16.511 39.366 16.547 40.122 ;
     RECT  16.511 43.146 16.547 45.018 ;
     RECT  16.511 45.81 16.547 46.062 ;
     RECT  16.511 47.16 16.547 52.434 ;
     RECT  16.511 58.626 16.547 60.912 ;
     RECT  16.511 61.776 16.547 67.464 ;
     RECT  16.511 68.256 16.547 68.544 ;
     RECT  16.511 69.768 16.547 71.334 ;
     RECT  16.511 73.08 16.547 73.602 ;
     RECT  16.475 29.88 16.583 29.898 ;
     RECT  16.547 39.366 16.583 39.384 ;
     RECT  16.547 51.48 16.583 52.434 ;
     RECT  15.899 53.298 16.583 57.744 ;
     RECT  16.547 59.85 16.583 60.174 ;
     RECT  16.547 62.586 16.583 66.852 ;
     RECT  16.547 37.71 16.619 37.728 ;
     RECT  16.547 47.16 16.619 50.31 ;
     RECT  16.583 59.85 16.619 59.868 ;
     RECT  16.583 62.676 16.619 63.378 ;
     RECT  16.619 48.006 16.979 50.31 ;
     RECT  16.547 33.93 17.087 33.984 ;
     RECT  16.547 30.924 17.095 31.914 ;
     RECT  17.059 33.084 17.095 33.102 ;
     RECT  16.979 48.366 17.123 50.31 ;
     RECT  16.583 53.874 17.123 56.664 ;
     RECT  16.583 64.251 17.123 66.852 ;
     RECT  16.511 25.326 17.159 25.614 ;
     RECT  16.511 27.108 17.159 27.36 ;
     RECT  17.095 30.924 17.159 33.102 ;
     RECT  17.087 33.93 17.159 33.948 ;
     RECT  16.547 34.74 17.159 35.424 ;
     RECT  16.511 41.076 17.159 41.814 ;
     RECT  16.547 43.416 17.159 45.018 ;
     RECT  17.123 48.366 17.159 49.464 ;
     RECT  17.123 54.036 17.159 55.782 ;
     RECT  17.123 56.61 17.159 56.664 ;
     RECT  16.583 57.546 17.159 57.744 ;
     RECT  17.123 64.836 17.159 66.852 ;
     RECT  16.547 69.804 17.159 71.334 ;
     RECT  16.511 78.516 17.159 78.624 ;
     RECT  16.367 21.276 17.195 21.294 ;
     RECT  16.331 24.246 17.195 24.264 ;
     RECT  17.159 25.596 17.195 25.614 ;
     RECT  17.159 27.216 17.195 27.36 ;
     RECT  17.159 30.924 17.195 32.724 ;
     RECT  17.159 34.74 17.195 35.262 ;
     RECT  16.547 36.396 17.195 36.954 ;
     RECT  17.159 41.076 17.195 41.544 ;
     RECT  17.159 43.416 17.195 44.064 ;
     RECT  17.159 44.856 17.195 44.874 ;
     RECT  16.547 45.81 17.195 45.828 ;
     RECT  16.619 47.16 17.195 47.178 ;
     RECT  17.159 48.708 17.195 49.464 ;
     RECT  17.123 50.292 17.195 50.31 ;
     RECT  16.583 51.48 17.195 52.074 ;
     RECT  17.095 52.956 17.195 52.974 ;
     RECT  17.159 54.306 17.195 55.17 ;
     RECT  17.159 56.646 17.195 56.664 ;
     RECT  17.159 57.726 17.195 57.744 ;
     RECT  16.547 58.626 17.195 59.022 ;
     RECT  16.547 61.776 17.195 61.794 ;
     RECT  16.619 63.36 17.195 63.378 ;
     RECT  17.159 65.178 17.195 66.852 ;
     RECT  16.547 68.256 17.195 68.274 ;
     RECT  17.159 69.804 17.195 69.822 ;
     RECT  17.159 71.082 17.195 71.334 ;
     RECT  16.547 73.116 17.195 73.134 ;
     RECT  17.159 78.606 17.195 78.624 ;
     RECT  16.295 19.818 17.267 19.836 ;
    LAYER M3 ;
     RECT  2.415 2.143 2.505 2.413 ;
     RECT  7.815 2.143 7.905 2.413 ;
     RECT  13.215 2.143 13.305 2.413 ;
     RECT  14.616 18.571 14.958 18.661 ;
     RECT  13.215 2.413 13.497 18.697 ;
     RECT  14.472 18.661 14.958 18.697 ;
     RECT  13.215 18.697 14.958 18.733 ;
     RECT  13.215 18.733 15.678 19.201 ;
     RECT  10.836 19.237 10.854 19.337 ;
     RECT  13.14 19.201 15.678 19.345 ;
     RECT  13.14 19.345 16.254 19.741 ;
     RECT  12.204 19.651 12.222 19.921 ;
     RECT  13.14 19.741 16.29 19.921 ;
     RECT  12.204 19.921 16.29 20.119 ;
     RECT  12.06 20.119 16.29 20.191 ;
     RECT  11.88 20.191 16.29 20.731 ;
     RECT  7.815 2.413 8.097 20.857 ;
     RECT  11.196 20.731 16.362 20.857 ;
     RECT  10.908 20.857 16.362 20.893 ;
     RECT  5.796 20.893 5.814 21.001 ;
     RECT  10.836 20.893 16.362 21.029 ;
     RECT  0.144 21.127 0.162 21.199 ;
     RECT  5.148 21.001 5.814 21.271 ;
     RECT  17.244 19.813 17.262 21.271 ;
     RECT  2.415 2.413 2.697 21.397 ;
     RECT  3.636 21.001 3.654 21.397 ;
     RECT  7.776 20.857 8.097 21.433 ;
     RECT  0.144 21.199 0.45 21.505 ;
     RECT  2.415 21.397 3.654 21.541 ;
     RECT  7.308 21.433 8.097 21.631 ;
     RECT  0.108 21.505 0.45 21.703 ;
     RECT  5.148 21.271 5.85 21.811 ;
     RECT  0.108 21.703 0.486 21.901 ;
     RECT  9.684 19.237 9.702 21.973 ;
     RECT  2.415 21.541 3.798 22.009 ;
     RECT  2.376 22.009 3.798 22.045 ;
     RECT  2.376 22.045 4.086 22.081 ;
     RECT  2.376 22.081 4.194 22.207 ;
     RECT  2.232 22.207 4.194 22.279 ;
     RECT  5.148 21.811 6.318 22.279 ;
     RECT  10.872 21.029 16.362 22.315 ;
     RECT  2.232 22.279 6.318 22.351 ;
     RECT  7.092 21.631 8.097 22.351 ;
     RECT  10.656 22.315 16.362 22.585 ;
     RECT  10.512 22.585 16.362 22.621 ;
     RECT  2.232 22.351 8.097 22.666 ;
     RECT  0.108 21.901 0.522 22.747 ;
     RECT  2.088 22.666 8.097 22.775 ;
     RECT  9.036 21.973 9.702 22.819 ;
     RECT  10.44 22.621 16.362 22.819 ;
     RECT  17.172 21.271 17.262 22.891 ;
     RECT  0.108 22.747 0.558 22.925 ;
     RECT  17.136 22.891 17.262 22.925 ;
     RECT  17.136 22.925 17.19 23.021 ;
     RECT  9.036 22.819 16.362 23.089 ;
     RECT  17.136 23.021 17.154 23.089 ;
     RECT  0.216 22.925 0.558 23.117 ;
     RECT  9.036 23.089 17.154 23.117 ;
     RECT  2.304 22.775 8.097 23.125 ;
     RECT  9.108 23.117 17.154 23.279 ;
     RECT  10.836 23.279 17.154 23.309 ;
     RECT  2.304 23.125 8.154 23.315 ;
     RECT  9.108 23.279 10.062 23.549 ;
     RECT  9.108 23.549 9.702 23.863 ;
     RECT  0.252 23.117 0.558 23.899 ;
     RECT  2.304 23.315 8.097 24.169 ;
     RECT  10.836 23.309 16.542 24.241 ;
     RECT  10.836 24.241 17.19 24.269 ;
     RECT  2.232 24.169 8.097 24.365 ;
     RECT  2.304 24.365 8.097 24.439 ;
     RECT  8.856 23.863 9.702 24.439 ;
     RECT  2.304 24.439 9.702 24.511 ;
     RECT  0.108 23.899 0.558 24.557 ;
     RECT  0.54 24.557 0.558 24.653 ;
     RECT  2.304 24.511 10.062 24.709 ;
     RECT  10.836 24.269 16.326 24.709 ;
     RECT  2.304 24.709 16.326 25.243 ;
     RECT  17.172 24.269 17.19 25.321 ;
     RECT  2.232 25.243 16.326 25.421 ;
     RECT  2.268 25.421 16.326 25.519 ;
     RECT  17.136 25.321 17.19 25.519 ;
     RECT  2.268 25.519 17.19 25.709 ;
     RECT  2.268 25.709 17.154 25.745 ;
     RECT  2.268 25.745 8.874 25.757 ;
     RECT  6.84 25.757 8.874 25.889 ;
     RECT  9.936 25.745 17.154 25.997 ;
     RECT  0.324 25.963 0.342 26.011 ;
     RECT  2.268 25.757 5.958 26.087 ;
     RECT  0.216 26.011 0.342 26.093 ;
     RECT  0.216 26.093 0.234 26.189 ;
     RECT  9.936 25.997 16.506 26.477 ;
     RECT  8.82 25.889 8.874 26.635 ;
     RECT  9.936 26.477 14.994 26.635 ;
     RECT  15.912 26.477 16.506 26.861 ;
     RECT  5.58 26.087 5.958 26.941 ;
     RECT  15.912 26.861 16.326 27.053 ;
     RECT  0.144 26.923 0.162 27.101 ;
     RECT  2.268 26.087 4.734 27.103 ;
     RECT  5.472 26.941 5.958 27.103 ;
     RECT  6.84 25.889 8.097 27.139 ;
     RECT  6.732 27.139 8.097 27.163 ;
     RECT  8.82 26.635 14.994 27.163 ;
     RECT  2.268 27.103 5.958 27.481 ;
     RECT  6.732 27.163 14.994 27.481 ;
     RECT  2.268 27.481 14.994 27.595 ;
     RECT  2.232 27.595 14.994 27.635 ;
     RECT  2.268 27.635 14.994 27.679 ;
     RECT  15.912 27.053 16.11 27.679 ;
     RECT  2.268 27.679 16.11 27.787 ;
     RECT  17.136 26.923 17.19 27.787 ;
     RECT  1.044 27.715 1.062 28.075 ;
     RECT  0.324 28.075 1.062 28.204 ;
     RECT  2.268 27.787 17.19 28.205 ;
     RECT  0.18 28.204 1.062 28.444 ;
     RECT  0.108 28.444 1.062 28.685 ;
     RECT  0.18 28.685 1.062 28.781 ;
     RECT  0.324 28.781 1.062 29.069 ;
     RECT  2.268 28.205 16.542 29.515 ;
     RECT  2.232 29.515 16.542 29.597 ;
     RECT  2.304 29.597 16.542 29.875 ;
     RECT  0.432 29.069 1.062 29.947 ;
     RECT  0.216 29.947 1.062 30.181 ;
     RECT  2.304 29.875 16.578 30.919 ;
     RECT  0.108 30.181 1.062 31.085 ;
     RECT  2.304 30.919 17.19 31.723 ;
     RECT  2.196 31.723 17.19 32.045 ;
     RECT  0.36 31.085 1.062 32.269 ;
     RECT  2.196 32.045 15.966 32.269 ;
     RECT  0.36 32.269 15.966 32.467 ;
     RECT  17.1 32.045 17.19 32.729 ;
     RECT  0.108 32.467 15.966 32.809 ;
     RECT  17.1 32.729 17.154 32.875 ;
     RECT  17.028 32.875 17.154 33.107 ;
     RECT  0.108 32.809 16.002 33.197 ;
     RECT  17.028 33.107 17.118 33.259 ;
     RECT  16.452 33.259 17.118 33.835 ;
     RECT  16.452 33.835 17.154 33.953 ;
     RECT  0.108 33.197 15.462 34.231 ;
     RECT  16.452 33.953 17.118 34.231 ;
     RECT  0.108 34.231 17.118 34.735 ;
     RECT  0.108 34.735 17.19 34.829 ;
     RECT  0.144 34.829 17.19 35.267 ;
     RECT  0.144 35.267 17.154 35.429 ;
     RECT  0.144 35.429 16.542 35.501 ;
     RECT  0.216 35.501 16.542 35.789 ;
     RECT  0.288 35.789 16.542 36.235 ;
     RECT  0.288 36.235 17.19 36.959 ;
     RECT  0.288 36.959 16.542 37.426 ;
     RECT  0.252 37.426 16.542 37.561 ;
     RECT  0.144 37.561 16.542 37.597 ;
     RECT  0.108 37.597 16.542 37.705 ;
     RECT  0.108 37.705 16.614 37.709 ;
     RECT  0.144 37.709 16.614 37.805 ;
     RECT  0.288 37.805 16.614 37.967 ;
     RECT  16.452 37.967 16.614 38.093 ;
     RECT  0.288 37.967 15.462 38.911 ;
     RECT  16.452 38.093 16.506 38.911 ;
     RECT  0.288 38.911 16.506 38.923 ;
     RECT  0.144 38.923 16.506 39.307 ;
     RECT  0.144 39.307 16.542 39.361 ;
     RECT  0.144 39.361 16.578 39.487 ;
     RECT  0.108 39.487 16.578 39.725 ;
     RECT  0.108 39.725 16.542 40.127 ;
     RECT  0.108 40.127 16.506 40.244 ;
     RECT  0.18 40.244 16.506 40.349 ;
     RECT  0.324 40.349 16.506 41.009 ;
     RECT  16.488 41.009 16.506 41.035 ;
     RECT  0.324 41.009 15.498 41.261 ;
     RECT  0.324 41.261 15.462 41.947 ;
     RECT  16.488 41.035 17.19 41.989 ;
     RECT  0.144 41.947 15.462 41.995 ;
     RECT  16.452 41.989 17.19 41.995 ;
     RECT  0.144 41.995 17.19 42.125 ;
     RECT  0.324 42.125 17.19 42.221 ;
     RECT  0.324 42.221 17.154 42.413 ;
     RECT  0.324 42.413 16.506 43.141 ;
     RECT  0.324 43.141 16.542 43.339 ;
     RECT  0.324 43.339 17.19 44.879 ;
     RECT  0.324 44.879 17.154 45.805 ;
     RECT  0.324 45.805 17.19 45.883 ;
     RECT  0.144 45.883 17.19 46.157 ;
     RECT  0.144 46.157 17.154 46.253 ;
     RECT  0.144 46.253 16.506 46.615 ;
     RECT  0.108 46.615 16.506 46.829 ;
     RECT  0.144 46.829 16.506 47.083 ;
     RECT  0.144 47.083 17.19 47.183 ;
     RECT  0.144 47.183 17.154 47.501 ;
     RECT  0.324 47.501 17.154 47.696 ;
     RECT  0.324 47.696 15.57 48.523 ;
     RECT  0.144 48.523 15.57 48.701 ;
     RECT  16.488 47.696 17.154 48.703 ;
     RECT  0.18 48.701 15.57 48.973 ;
     RECT  16.488 48.703 17.19 48.973 ;
     RECT  0.18 48.973 17.19 49.469 ;
     RECT  0.18 49.469 17.118 49.549 ;
     RECT  0.108 49.549 17.118 49.805 ;
     RECT  0.144 49.805 17.118 50.287 ;
     RECT  0.144 50.287 17.19 50.923 ;
     RECT  0.108 50.923 17.19 51.395 ;
     RECT  0.144 51.395 17.19 52.079 ;
     RECT  0.144 52.079 16.578 52.781 ;
     RECT  16.38 52.781 16.578 52.939 ;
     RECT  16.38 52.939 17.19 52.979 ;
     RECT  0.144 52.781 15.462 52.987 ;
     RECT  16.38 52.979 17.118 53.021 ;
     RECT  0.108 52.987 15.462 53.069 ;
     RECT  0.144 53.069 15.462 53.309 ;
     RECT  0.324 53.309 15.462 53.671 ;
     RECT  16.38 53.021 16.578 53.671 ;
     RECT  0.324 53.671 16.578 53.869 ;
     RECT  0.324 53.869 17.118 54.031 ;
     RECT  0.324 54.031 17.154 54.283 ;
     RECT  0.324 54.283 17.19 54.707 ;
     RECT  0.324 54.707 16.038 54.907 ;
     RECT  0.144 54.907 16.038 55.627 ;
     RECT  17.1 54.707 17.19 55.627 ;
     RECT  0.144 55.627 17.19 55.853 ;
     RECT  0.216 55.853 17.19 56.129 ;
     RECT  0.216 56.129 15.498 56.141 ;
     RECT  16.452 56.129 17.19 56.669 ;
     RECT  0.216 56.141 15.462 56.731 ;
     RECT  0.144 56.731 15.462 56.875 ;
     RECT  16.452 56.669 17.154 56.875 ;
     RECT  0.144 56.875 17.154 57.209 ;
     RECT  17.136 57.209 17.154 57.451 ;
     RECT  0.144 57.209 15.966 57.479 ;
     RECT  17.136 57.451 17.19 57.569 ;
     RECT  0.144 57.479 15.894 57.643 ;
     RECT  17.172 57.569 17.19 57.749 ;
     RECT  0.108 57.643 15.894 58.289 ;
     RECT  0.144 58.289 15.894 58.495 ;
     RECT  0.144 58.495 15.966 58.531 ;
     RECT  17.172 58.507 17.19 59.027 ;
     RECT  0.144 58.531 16.002 59.071 ;
     RECT  0.108 59.071 16.002 59.117 ;
     RECT  0.288 59.117 16.002 59.179 ;
     RECT  0.288 59.179 16.542 59.845 ;
     RECT  0.288 59.845 16.614 60.043 ;
     RECT  0.108 60.043 16.614 60.071 ;
     RECT  16.452 60.071 16.614 60.365 ;
     RECT  0.108 60.071 15.498 60.811 ;
     RECT  16.452 60.365 16.542 60.811 ;
     RECT  0.108 60.811 16.542 60.989 ;
     RECT  0.108 60.989 15.498 61.037 ;
     RECT  16.452 60.989 16.542 61.099 ;
     RECT  16.452 61.099 17.19 61.799 ;
     RECT  0.108 61.037 15.426 62.203 ;
     RECT  16.452 61.799 17.118 62.203 ;
     RECT  0.108 62.203 17.118 62.539 ;
     RECT  0.108 62.539 17.19 62.861 ;
     RECT  0.144 62.861 17.19 63.383 ;
     RECT  0.144 63.383 16.614 63.787 ;
     RECT  0.108 63.787 16.614 64.205 ;
     RECT  0.144 64.205 16.614 64.246 ;
     RECT  0.144 64.246 17.118 64.831 ;
     RECT  0.144 64.831 17.154 64.939 ;
     RECT  0.108 64.939 17.19 65.579 ;
     RECT  0.108 65.579 15.426 65.741 ;
     RECT  16.488 65.579 17.19 66.857 ;
     RECT  0.144 65.741 15.426 67.027 ;
     RECT  16.488 66.857 16.542 67.027 ;
     RECT  0.144 67.027 16.542 67.055 ;
     RECT  0.144 67.055 8.766 67.099 ;
     RECT  0.108 67.099 8.766 67.469 ;
     RECT  9.648 67.055 16.542 67.739 ;
     RECT  0.18 67.469 8.766 67.801 ;
     RECT  9.648 67.739 15.462 67.801 ;
     RECT  16.452 67.739 16.542 68.011 ;
     RECT  0.18 67.801 15.462 68.279 ;
     RECT  16.452 68.011 17.19 68.279 ;
     RECT  0.18 68.279 0.558 68.429 ;
     RECT  16.452 68.279 16.542 68.717 ;
     RECT  1.62 68.279 15.462 68.719 ;
     RECT  16.452 68.717 16.506 68.719 ;
     RECT  0.324 68.429 0.558 68.747 ;
     RECT  1.62 68.719 16.506 69.355 ;
     RECT  1.44 69.355 16.506 69.451 ;
     RECT  0.468 68.747 0.558 69.493 ;
     RECT  0.108 69.493 0.558 70.157 ;
     RECT  1.44 69.451 17.19 70.637 ;
     RECT  2.268 70.637 17.19 70.673 ;
     RECT  2.268 70.673 15.534 70.907 ;
     RECT  0.504 70.157 0.558 71.149 ;
     RECT  16.272 70.673 17.19 71.339 ;
     RECT  1.44 70.637 1.458 71.447 ;
     RECT  2.304 70.907 15.534 71.455 ;
     RECT  16.272 71.339 16.542 71.455 ;
     RECT  2.304 71.455 16.542 71.653 ;
     RECT  2.196 71.653 16.542 71.693 ;
     RECT  2.268 71.693 16.542 71.789 ;
     RECT  2.268 71.789 16.506 71.915 ;
     RECT  0.108 71.149 0.558 71.981 ;
     RECT  0.144 71.981 0.558 72.257 ;
     RECT  2.304 71.915 16.506 72.715 ;
     RECT  0.144 72.257 0.522 72.805 ;
     RECT  2.268 72.715 16.506 72.995 ;
     RECT  2.304 72.995 16.506 73.075 ;
     RECT  2.304 73.075 16.542 73.099 ;
     RECT  0.108 72.805 0.522 73.139 ;
     RECT  2.304 73.099 17.19 73.139 ;
     RECT  0.108 73.139 0.198 73.421 ;
     RECT  2.304 73.139 16.542 73.912 ;
     RECT  2.232 73.912 16.542 73.949 ;
     RECT  2.268 73.949 16.542 74.285 ;
     RECT  0.216 73.867 0.342 74.381 ;
     RECT  0.216 74.381 0.234 74.573 ;
     RECT  0.324 75.595 0.342 75.691 ;
     RECT  0.108 75.691 0.342 75.703 ;
     RECT  2.268 74.285 16.506 75.835 ;
     RECT  2.196 75.835 16.506 75.979 ;
     RECT  2.196 75.979 17.19 76.037 ;
     RECT  7.815 76.037 17.19 76.199 ;
     RECT  9.612 76.199 17.19 76.379 ;
     RECT  7.815 76.199 8.838 76.469 ;
     RECT  2.232 76.037 7.002 76.577 ;
     RECT  7.815 76.469 8.622 76.577 ;
     RECT  7.815 76.577 8.478 76.649 ;
     RECT  2.268 76.577 7.002 76.739 ;
     RECT  9.612 76.379 10.17 76.847 ;
     RECT  0.108 75.703 0.594 77.189 ;
     RECT  2.268 76.739 6.858 77.189 ;
     RECT  5.472 77.189 6.858 77.279 ;
     RECT  5.724 77.279 6.858 77.521 ;
     RECT  2.268 77.189 4.698 77.585 ;
     RECT  5.724 77.521 6.894 77.621 ;
     RECT  2.34 77.585 4.698 77.819 ;
     RECT  9.72 76.847 10.17 77.827 ;
     RECT  10.944 76.379 17.19 77.827 ;
     RECT  2.34 77.819 4.158 77.855 ;
     RECT  9.72 77.827 17.19 77.927 ;
     RECT  2.415 77.855 4.158 78.089 ;
     RECT  0.108 77.189 0.126 78.125 ;
     RECT  2.415 78.089 3.294 78.125 ;
     RECT  2.415 78.125 3.186 78.359 ;
     RECT  4.032 78.089 4.158 78.359 ;
     RECT  2.415 78.359 2.754 78.629 ;
     RECT  4.032 78.359 4.05 78.629 ;
     RECT  10.98 77.927 17.19 78.629 ;
     RECT  5.724 77.621 6.102 78.637 ;
     RECT  10.98 78.629 16.47 78.809 ;
     RECT  5.724 78.637 6.174 79.079 ;
     RECT  16.452 78.809 16.47 79.079 ;
     RECT  9.72 77.927 10.17 79.141 ;
     RECT  10.98 78.809 15.678 79.141 ;
     RECT  5.724 79.079 5.742 79.169 ;
     RECT  9.72 79.141 15.678 79.241 ;
     RECT  9.72 79.241 10.17 79.619 ;
     RECT  10.98 79.241 15.678 79.757 ;
     RECT  11.664 79.757 15.678 80.249 ;
     RECT  11.844 80.249 15.678 80.789 ;
     RECT  13.032 80.789 15.426 80.825 ;
     RECT  11.844 80.789 12.078 80.861 ;
     RECT  14.688 80.825 15.426 80.897 ;
     RECT  11.844 80.861 11.862 81.059 ;
     RECT  13.032 80.825 13.914 81.059 ;
     RECT  12.096 82.651 12.258 82.949 ;
     RECT  13.032 81.059 13.497 82.949 ;
     RECT  12.096 82.949 12.114 83.165 ;
     RECT  9.72 79.619 9.738 94.711 ;
     RECT  9.72 94.711 10.17 94.837 ;
     RECT  9.216 94.837 10.17 94.877 ;
     RECT  9.684 94.877 10.17 94.981 ;
     RECT  15.408 80.897 15.426 95.135 ;
     RECT  9.684 94.981 10.314 95.405 ;
     RECT  9.936 95.405 10.314 95.413 ;
     RECT  9.936 95.413 10.386 95.909 ;
     RECT  9.936 95.909 10.35 96.179 ;
     RECT  10.08 96.179 10.35 96.755 ;
     RECT  10.224 96.755 10.35 96.871 ;
     RECT  2.415 78.629 2.697 96.947 ;
     RECT  7.815 76.649 8.097 96.947 ;
     RECT  13.215 82.949 13.497 96.947 ;
     RECT  10.224 96.871 10.494 96.989 ;
     RECT  10.332 96.989 10.494 97.133 ;
     RECT  2.415 96.947 2.505 97.217 ;
     RECT  7.815 96.947 7.905 97.217 ;
     RECT  13.215 96.947 13.305 97.217 ;
     RECT  10.476 97.133 10.494 97.517 ;
    LAYER M4 ;
     RECT  0.06 22.32 0.533 76.296 ;
     RECT  0.533 22.992 0.569 76.296 ;
     RECT  0.569 23.184 1.045 76.296 ;
     RECT  1.045 23.184 2.408 77.112 ;
     RECT  2.408 2.148 2.512 97.212 ;
     RECT  2.512 2.418 2.704 96.942 ;
     RECT  2.704 23.04 2.765 74.712 ;
     RECT  2.765 23.04 2.837 27.096 ;
     RECT  2.765 28.176 2.873 74.712 ;
     RECT  2.873 44.88 2.945 74.712 ;
     RECT  2.837 25.824 2.981 27.096 ;
     RECT  2.873 28.176 3.053 43.848 ;
     RECT  3.053 28.176 3.125 43.368 ;
     RECT  2.945 44.88 3.125 72.984 ;
     RECT  3.125 44.88 3.197 48.312 ;
     RECT  3.125 49.44 3.197 72.984 ;
     RECT  2.704 75.696 3.413 77.544 ;
     RECT  3.413 76.32 3.443 77.544 ;
     RECT  3.197 56.448 3.485 72.984 ;
     RECT  3.197 49.44 3.809 55.32 ;
     RECT  3.809 49.584 3.845 55.32 ;
     RECT  3.125 28.176 4.057 42.936 ;
     RECT  2.837 23.04 4.093 23.976 ;
     RECT  4.057 27.888 4.117 42.936 ;
     RECT  4.117 27.792 4.129 42.936 ;
     RECT  2.945 74.016 4.169 74.712 ;
     RECT  2.981 25.872 4.309 26.76 ;
     RECT  4.129 27.792 4.309 42.984 ;
     RECT  3.197 44.88 4.316 45.192 ;
     RECT  3.197 46.272 4.316 48.312 ;
     RECT  3.485 60.24 4.444 72.984 ;
     RECT  3.845 50.592 4.453 55.32 ;
     RECT  3.485 56.448 4.453 59.256 ;
     RECT  4.309 25.872 4.489 42.984 ;
     RECT  4.489 25.872 4.501 43.128 ;
     RECT  4.453 50.592 4.525 59.256 ;
     RECT  4.444 60.24 4.525 67.32 ;
     RECT  4.169 74.016 4.529 74.424 ;
     RECT  4.093 23.04 4.597 24.792 ;
     RECT  4.501 25.872 4.597 43.896 ;
     RECT  4.597 23.04 4.601 43.896 ;
     RECT  4.601 23.04 4.637 33.816 ;
     RECT  4.444 68.304 4.733 72.984 ;
     RECT  4.529 74.016 4.733 74.328 ;
     RECT  3.845 49.584 5.137 49.608 ;
     RECT  4.525 50.592 5.137 67.32 ;
     RECT  4.316 44.88 5.173 48.312 ;
     RECT  5.137 49.584 5.173 67.32 ;
     RECT  4.733 68.304 5.212 74.328 ;
     RECT  5.212 68.304 5.249 72.936 ;
     RECT  4.601 34.848 5.353 43.896 ;
     RECT  5.173 44.88 5.353 67.32 ;
     RECT  5.353 34.848 5.357 67.32 ;
     RECT  5.357 34.944 5.501 67.32 ;
     RECT  3.443 76.32 5.537 77.016 ;
     RECT  5.212 74.016 5.653 74.328 ;
     RECT  5.537 76.944 5.699 77.016 ;
     RECT  5.653 74.016 5.701 74.856 ;
     RECT  5.249 68.304 5.753 72.408 ;
     RECT  5.501 40.128 5.941 67.32 ;
     RECT  5.753 68.304 5.941 71.784 ;
     RECT  6.217 72.96 6.301 73.032 ;
     RECT  5.941 40.128 6.323 71.784 ;
     RECT  4.637 24.912 6.419 33.816 ;
     RECT  6.301 72.96 6.419 72.984 ;
     RECT  6.323 45.696 6.437 71.784 ;
     RECT  5.501 34.944 6.685 39.144 ;
     RECT  6.323 40.128 6.685 44.616 ;
     RECT  6.437 68.688 6.761 71.784 ;
     RECT  5.701 74.016 6.829 75.672 ;
     RECT  6.685 34.944 6.833 44.616 ;
     RECT  6.437 45.696 7.429 67.56 ;
     RECT  6.761 68.688 7.429 70.824 ;
     RECT  6.833 34.992 7.573 44.616 ;
     RECT  7.429 45.696 7.573 70.824 ;
     RECT  6.419 25.44 7.669 33.816 ;
     RECT  3.829 21.168 7.808 21.192 ;
     RECT  4.637 23.04 7.808 23.832 ;
     RECT  7.669 25.296 7.808 33.816 ;
     RECT  7.573 34.992 7.808 70.824 ;
     RECT  7.369 71.856 7.808 71.88 ;
     RECT  6.829 74.016 7.808 75.768 ;
     RECT  5.699 76.992 7.808 77.016 ;
     RECT  7.808 2.148 7.912 97.212 ;
     RECT  7.912 2.418 8.104 96.942 ;
     RECT  8.104 45.696 8.165 49.08 ;
     RECT  8.104 25.056 8.332 44.664 ;
     RECT  8.332 25.296 8.435 44.664 ;
     RECT  8.165 45.744 8.675 49.08 ;
     RECT  8.435 29.28 8.885 44.664 ;
     RECT  8.104 75.264 9.029 76.008 ;
     RECT  8.435 25.296 9.065 28.2 ;
     RECT  9.029 75.264 9.065 75.768 ;
     RECT  8.104 23.04 9.097 23.832 ;
     RECT  8.104 50.832 9.107 57.864 ;
     RECT  8.885 34.944 9.245 44.664 ;
     RECT  8.675 45.744 9.245 48.504 ;
     RECT  9.065 25.44 9.397 28.2 ;
     RECT  8.885 29.28 9.397 33.864 ;
     RECT  8.104 58.896 9.404 71.88 ;
     RECT  9.404 58.464 9.457 71.88 ;
     RECT  8.104 72.912 9.457 73.56 ;
     RECT  9.457 58.464 9.565 73.56 ;
     RECT  9.097 23.04 9.569 23.928 ;
     RECT  9.245 41.952 9.673 44.664 ;
     RECT  9.565 58.464 9.673 73.8 ;
     RECT  9.673 58.464 9.677 74.76 ;
     RECT  9.065 75.744 9.713 75.768 ;
     RECT  9.677 67.68 9.731 74.76 ;
     RECT  9.107 50.832 9.74 57.48 ;
     RECT  9.673 41.952 9.745 44.712 ;
     RECT  9.245 45.744 9.745 47.88 ;
     RECT  9.745 41.952 9.827 47.88 ;
     RECT  9.731 67.68 9.857 73.56 ;
     RECT  9.245 34.944 9.884 40.968 ;
     RECT  9.397 25.44 9.893 33.864 ;
     RECT  9.893 31.344 9.925 33.864 ;
     RECT  9.884 34.848 9.925 40.968 ;
     RECT  9.74 50.784 9.925 57.48 ;
     RECT  9.857 69.456 9.971 73.56 ;
     RECT  9.731 74.688 10.001 74.76 ;
     RECT  9.971 69.456 10.109 73.272 ;
     RECT  9.925 31.344 10.181 40.968 ;
     RECT  10.181 31.44 10.249 40.968 ;
     RECT  9.925 50.736 10.253 57.48 ;
     RECT  10.253 51.072 10.289 57.48 ;
     RECT  10.289 51.312 10.321 57.48 ;
     RECT  9.677 58.464 10.321 66.408 ;
     RECT  10.309 97.488 10.321 97.512 ;
     RECT  9.893 25.44 10.433 29.976 ;
     RECT  10.109 69.456 10.451 73.128 ;
     RECT  10.321 97.104 10.451 97.512 ;
     RECT  9.569 23.04 10.501 23.832 ;
     RECT  9.827 42.24 10.501 47.88 ;
     RECT  10.451 97.488 10.505 97.512 ;
     RECT  10.433 25.44 10.541 25.8 ;
     RECT  10.249 31.44 10.595 41.016 ;
     RECT  10.451 69.456 10.595 72.936 ;
     RECT  10.501 22.752 10.645 23.832 ;
     RECT  10.541 25.44 10.645 25.464 ;
     RECT  10.595 31.632 10.649 41.016 ;
     RECT  10.321 51.312 10.649 66.408 ;
     RECT  10.433 27.072 10.793 29.976 ;
     RECT  10.645 22.752 10.883 25.464 ;
     RECT  10.501 42.24 10.897 48.312 ;
     RECT  10.793 27.744 10.901 29.976 ;
     RECT  10.883 22.752 10.924 23.88 ;
     RECT  10.883 25.104 10.924 25.464 ;
     RECT  10.924 22.752 11.009 23.832 ;
     RECT  10.924 25.44 11.009 25.464 ;
     RECT  10.897 42.24 11.036 49.032 ;
     RECT  10.001 74.688 11.077 74.712 ;
     RECT  8.104 21.168 11.084 21.192 ;
     RECT  10.969 79.728 11.149 79.752 ;
     RECT  11.084 21.168 11.171 21.336 ;
     RECT  9.857 67.68 11.185 68.376 ;
     RECT  11.009 22.752 11.189 23.064 ;
     RECT  11.077 74.688 11.221 74.952 ;
     RECT  11.149 79.248 11.233 79.752 ;
     RECT  10.901 27.792 11.267 29.976 ;
     RECT  11.171 21.168 11.297 21.192 ;
     RECT  8.104 76.992 11.317 77.016 ;
     RECT  11.221 74.688 11.363 75.672 ;
     RECT  11.036 42.048 11.365 49.032 ;
     RECT  11.365 42.048 11.401 49.08 ;
     RECT  10.649 51.312 11.401 52.44 ;
     RECT  11.317 76.992 11.404 77.496 ;
     RECT  11.363 74.688 11.549 75.24 ;
     RECT  11.473 76.944 11.557 76.968 ;
     RECT  11.267 27.888 11.581 29.976 ;
     RECT  10.649 31.632 11.581 40.824 ;
     RECT  11.185 67.488 11.581 68.376 ;
     RECT  10.595 69.456 11.581 72.168 ;
     RECT  11.189 22.752 11.621 22.776 ;
     RECT  11.401 42.048 11.689 52.44 ;
     RECT  10.649 53.616 11.689 66.408 ;
     RECT  11.689 42.048 11.725 66.408 ;
     RECT  11.581 67.488 11.725 72.168 ;
     RECT  11.581 27.888 11.869 40.824 ;
     RECT  11.725 42 11.869 72.168 ;
     RECT  12.044 83.136 12.085 83.16 ;
     RECT  12.085 82.656 12.131 83.16 ;
     RECT  9.205 94.848 12.131 94.872 ;
     RECT  11.233 79.728 12.179 79.752 ;
     RECT  11.869 27.888 12.229 72.168 ;
     RECT  12.553 24.384 12.589 24.408 ;
     RECT  12.589 24.384 12.625 25.272 ;
     RECT  12.229 27.312 12.625 72.168 ;
     RECT  12.625 73.248 12.661 73.272 ;
     RECT  11.549 74.688 12.661 74.952 ;
     RECT  12.661 73.248 12.697 74.952 ;
     RECT  12.625 27.072 12.841 72.168 ;
     RECT  12.697 73.248 12.841 75.144 ;
     RECT  12.625 24.384 12.985 25.752 ;
     RECT  12.985 24.384 13.021 26.088 ;
     RECT  12.841 27.072 13.021 75.144 ;
     RECT  12.697 76.896 13.093 76.92 ;
     RECT  13.045 78.096 13.093 78.12 ;
     RECT  12.265 79.248 13.093 79.272 ;
     RECT  13.045 20.976 13.208 21 ;
     RECT  12.733 23.136 13.208 23.16 ;
     RECT  13.021 24.384 13.208 75.144 ;
     RECT  13.093 76.896 13.208 79.272 ;
     RECT  12.131 82.656 13.208 82.68 ;
     RECT  13.208 2.148 13.312 97.212 ;
     RECT  13.312 2.418 13.504 96.942 ;
     RECT  13.504 22.848 13.667 75.624 ;
     RECT  13.667 24.24 13.673 75.624 ;
     RECT  13.504 78.48 13.708 78.6 ;
     RECT  13.673 24.24 13.781 55.752 ;
     RECT  13.673 57.024 13.817 75.624 ;
     RECT  13.817 57.936 13.853 75.624 ;
     RECT  13.853 57.936 13.889 75.24 ;
     RECT  13.781 24.24 13.925 50.664 ;
     RECT  13.889 57.936 13.925 62.472 ;
     RECT  13.925 24.24 13.997 49.896 ;
     RECT  13.504 80.4 14.147 80.424 ;
     RECT  13.925 58.128 14.213 62.472 ;
     RECT  14.213 58.128 14.249 62.328 ;
     RECT  13.997 24.24 14.285 47.928 ;
     RECT  13.997 49.008 14.285 49.896 ;
     RECT  13.889 63.792 14.285 75.24 ;
     RECT  14.285 24.24 14.321 47.4 ;
     RECT  14.321 26.544 14.357 47.4 ;
     RECT  13.781 51.84 14.357 55.752 ;
     RECT  14.285 63.792 14.465 73.224 ;
     RECT  14.357 51.936 14.498 55.752 ;
     RECT  14.357 26.544 14.537 30.552 ;
     RECT  14.465 70.848 14.537 73.224 ;
     RECT  14.321 24.24 14.641 25.416 ;
     RECT  14.357 31.68 14.645 47.4 ;
     RECT  14.249 58.128 14.681 62.28 ;
     RECT  14.605 18.768 14.689 18.792 ;
     RECT  14.641 78.672 14.713 78.696 ;
     RECT  14.713 78.672 14.753 78.84 ;
     RECT  14.645 31.776 14.789 47.4 ;
     RECT  14.753 78.72 14.819 78.84 ;
     RECT  14.713 76.656 14.825 76.824 ;
     RECT  14.819 78.72 14.825 78.744 ;
     RECT  14.641 23.664 14.857 25.416 ;
     RECT  14.825 76.656 14.857 76.68 ;
     RECT  14.789 43.536 14.933 47.4 ;
     RECT  14.285 49.2 14.965 49.896 ;
     RECT  14.465 63.792 14.965 69.864 ;
     RECT  14.537 26.544 15.361 30.312 ;
     RECT  14.285 74.352 15.361 75.24 ;
     RECT  14.857 76.368 15.361 76.68 ;
     RECT  14.857 23.088 15.397 25.416 ;
     RECT  15.361 26.448 15.397 30.312 ;
     RECT  14.965 63.312 15.433 69.864 ;
     RECT  14.537 70.848 15.433 72.264 ;
     RECT  14.965 49.2 15.469 50.28 ;
     RECT  14.498 51.984 15.469 55.752 ;
     RECT  14.933 47.376 15.505 47.4 ;
     RECT  15.469 48.624 15.505 50.28 ;
     RECT  14.789 31.776 15.793 42.312 ;
     RECT  15.361 73.68 15.793 76.68 ;
     RECT  15.397 23.088 15.829 30.312 ;
     RECT  15.793 31.728 15.829 42.312 ;
     RECT  15.793 73.584 15.829 76.68 ;
     RECT  15.433 63.312 15.865 72.264 ;
     RECT  15.829 73.296 15.865 76.68 ;
     RECT  15.505 47.376 15.901 50.28 ;
     RECT  15.469 51.312 15.901 56.136 ;
     RECT  14.681 58.32 15.901 62.28 ;
     RECT  15.829 23.088 15.937 42.312 ;
     RECT  14.933 43.536 15.937 46.344 ;
     RECT  15.901 47.376 15.937 56.136 ;
     RECT  15.901 57.36 15.937 62.28 ;
     RECT  15.937 23.088 15.973 46.344 ;
     RECT  15.937 47.376 15.973 62.28 ;
     RECT  15.865 63.312 15.973 76.68 ;
     RECT  15.973 23.088 17.125 76.68 ;
     RECT  17.125 22.896 17.244 76.68 ;
     RECT  17.244 22.896 17.273 22.92 ;
    LAYER M5 ;
     RECT  2.4 2.137 2.52 2.151 ;
     RECT  7.8 2.137 7.92 2.151 ;
     RECT  13.2 2.137 13.32 2.151 ;
     RECT  13.2 2.151 13.512 20.965 ;
     RECT  11.136 21.301 11.16 22.787 ;
     RECT  13.056 20.965 13.512 22.837 ;
     RECT  2.4 2.151 2.712 23.029 ;
     RECT  3.84 21.157 3.864 23.029 ;
     RECT  13.056 22.837 13.656 23.363 ;
     RECT  13.056 23.363 13.608 23.459 ;
     RECT  2.4 23.029 3.864 23.605 ;
     RECT  2.4 23.605 3.912 23.797 ;
     RECT  7.8 2.151 8.112 25.045 ;
     RECT  10.848 23.845 10.872 25.139 ;
     RECT  13.056 23.459 13.512 25.141 ;
     RECT  14.64 18.757 14.664 25.141 ;
     RECT  13.056 25.141 14.664 25.187 ;
     RECT  7.8 25.045 8.28 25.285 ;
     RECT  7.68 25.285 8.28 25.331 ;
     RECT  13.056 25.187 14.184 25.331 ;
     RECT  2.4 23.797 4.104 25.429 ;
     RECT  2.4 25.429 4.632 25.765 ;
     RECT  0.144 25.813 0.168 26.099 ;
     RECT  6.384 24.901 6.408 26.245 ;
     RECT  6.384 26.245 6.6 27.157 ;
     RECT  7.68 25.331 8.112 27.157 ;
     RECT  13.056 25.331 13.512 27.301 ;
     RECT  6.384 27.157 8.112 27.781 ;
     RECT  10.32 27.445 10.344 27.781 ;
     RECT  12.336 27.301 13.512 27.877 ;
     RECT  2.4 25.765 4.872 28.117 ;
     RECT  6.048 27.781 8.112 28.117 ;
     RECT  0.144 28.165 0.168 28.213 ;
     RECT  10.32 27.781 11.256 28.309 ;
     RECT  0.144 28.213 0.264 28.933 ;
     RECT  2.4 28.117 8.112 28.933 ;
     RECT  0.144 28.933 0.552 29.075 ;
     RECT  9.408 28.309 11.256 29.317 ;
     RECT  12.336 27.877 14.328 29.317 ;
     RECT  9.408 29.317 14.328 29.605 ;
     RECT  2.4 28.933 8.424 30.037 ;
     RECT  9.408 29.605 14.376 30.037 ;
     RECT  2.4 30.037 14.376 30.661 ;
     RECT  0.528 29.075 0.552 31.093 ;
     RECT  1.68 30.661 14.376 31.093 ;
     RECT  0.528 31.093 14.376 31.765 ;
     RECT  0.48 31.765 14.376 33.877 ;
     RECT  0.144 33.877 14.376 34.163 ;
     RECT  0.48 34.163 14.376 37.141 ;
     RECT  0.144 37.141 14.376 37.907 ;
     RECT  0.48 37.907 14.376 40.069 ;
     RECT  0.288 40.069 14.376 40.211 ;
     RECT  0.48 40.211 14.376 43.669 ;
     RECT  0.144 43.669 14.376 43.859 ;
     RECT  0.48 43.859 14.376 45.781 ;
     RECT  0.192 45.781 14.376 46.163 ;
     RECT  0.48 46.163 14.376 48.277 ;
     RECT  0.144 48.277 14.376 50.579 ;
     RECT  0.48 50.579 14.376 51.973 ;
     RECT  0.144 51.973 14.376 54.131 ;
     RECT  0.48 54.131 14.376 55.429 ;
     RECT  0.288 55.429 14.376 55.525 ;
     RECT  0.192 55.525 14.376 56.005 ;
     RECT  0.144 56.005 14.376 56.291 ;
     RECT  0.288 56.291 14.376 57.011 ;
     RECT  0.48 57.011 14.376 59.557 ;
     RECT  0.144 59.557 14.376 59.747 ;
     RECT  17.088 61.429 17.112 61.525 ;
     RECT  17.04 61.525 17.112 61.667 ;
     RECT  17.088 61.667 17.112 61.811 ;
     RECT  0.48 59.747 14.376 64.691 ;
     RECT  0.48 64.691 14.28 65.749 ;
     RECT  0.144 65.749 14.28 66.035 ;
     RECT  0.48 66.035 13.848 67.331 ;
     RECT  2.16 67.331 13.848 67.907 ;
     RECT  0.48 67.331 1.128 68.101 ;
     RECT  0.144 68.101 1.128 68.291 ;
     RECT  2.16 67.907 13.752 69.491 ;
     RECT  2.16 69.491 13.704 69.587 ;
     RECT  2.16 69.587 3.048 70.355 ;
     RECT  2.256 70.355 3.048 70.403 ;
     RECT  2.4 70.403 3.048 70.645 ;
     RECT  4.368 69.587 6.312 70.645 ;
     RECT  2.4 70.645 6.312 70.739 ;
     RECT  7.296 69.587 13.704 70.739 ;
     RECT  7.488 70.739 13.704 71.221 ;
     RECT  2.4 70.739 6.264 71.749 ;
     RECT  7.488 71.221 14.136 71.891 ;
     RECT  2.4 71.749 6.408 72.371 ;
     RECT  3.936 72.371 6.408 72.995 ;
     RECT  4.752 72.995 6.264 73.043 ;
     RECT  4.752 73.043 5.976 73.571 ;
     RECT  0.48 68.291 1.128 73.909 ;
     RECT  5.136 73.571 5.976 74.147 ;
     RECT  0.144 73.909 1.128 74.387 ;
     RECT  0.48 74.387 1.128 74.435 ;
     RECT  0.48 74.435 1.08 74.723 ;
     RECT  7.584 71.891 14.136 74.771 ;
     RECT  5.664 74.147 5.832 75.299 ;
     RECT  7.584 74.771 8.904 75.299 ;
     RECT  2.4 72.371 2.712 75.493 ;
     RECT  5.664 75.299 5.736 75.683 ;
     RECT  2.304 75.493 2.712 75.875 ;
     RECT  7.8 75.299 8.904 76.019 ;
     RECT  2.4 75.875 2.712 76.597 ;
     RECT  5.664 75.683 5.688 76.979 ;
     RECT  1.056 74.723 1.08 77.123 ;
     RECT  2.4 76.597 3.432 77.555 ;
     RECT  10.224 74.771 14.136 78.709 ;
     RECT  10.224 78.709 14.808 78.851 ;
     RECT  10.224 78.851 14.136 79.283 ;
     RECT  11.328 79.283 14.136 79.763 ;
     RECT  12.144 79.763 14.136 80.435 ;
     RECT  12.144 80.435 13.512 82.691 ;
     RECT  12.096 83.125 12.12 94.883 ;
     RECT  10.224 79.283 10.248 97.093 ;
     RECT  2.4 77.555 2.712 97.209 ;
     RECT  7.8 76.019 8.112 97.209 ;
     RECT  13.2 82.691 13.512 97.209 ;
     RECT  2.4 97.209 2.52 97.223 ;
     RECT  7.8 97.209 7.92 97.223 ;
     RECT  13.2 97.209 13.32 97.223 ;
     RECT  10.224 97.093 10.44 99.344 ;
  END
END ot_hgi_coll_qslots_capture_pin_v2
END LIBRARY
